VERSION 5.8 ;
BUSBITCHARS "[]" ;
DIVIDERCHAR "/" ;
UNITS
    DATABASE MICRONS 1000 ;
END UNITS

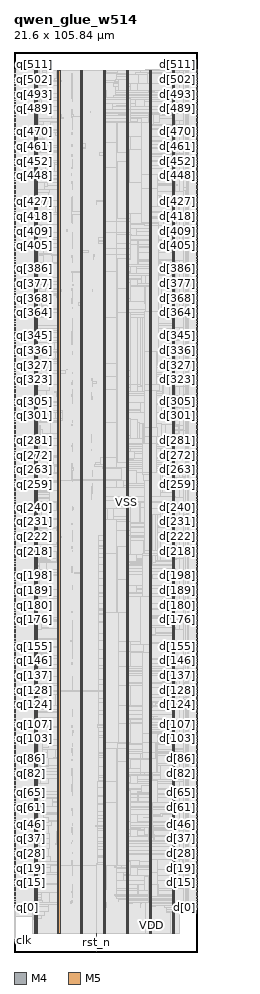
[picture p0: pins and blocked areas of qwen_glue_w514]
MACRO qwen_glue_w514
  FOREIGN qwen_glue_w514 0 0 ;
  CLASS BLOCK ;
  SIZE 21.6 BY 105.84 ;
  PIN clk
    DIRECTION INPUT ;
    USE SIGNAL ;
    PORT
      LAYER M4 ;
        RECT  0.054 1.296 0.138 1.32 ;
    END
    PORT
      LAYER M4 ;
        RECT  0.108 1.296 0.227 1.416 ;
    END
  END clk
  PIN d[0]
    DIRECTION INPUT ;
    USE SIGNAL ;
    PORT
      LAYER M4 ;
        RECT  21.462 5.28 21.546 5.304 ;
    END
  END d[0]
  PIN d[100]
    DIRECTION INPUT ;
    USE SIGNAL ;
    PORT
      LAYER M4 ;
        RECT  21.462 24.48 21.546 24.504 ;
    END
  END d[100]
  PIN d[101]
    DIRECTION INPUT ;
    USE SIGNAL ;
    PORT
      LAYER M4 ;
        RECT  21.462 24.672 21.546 24.696 ;
    END
  END d[101]
  PIN d[102]
    DIRECTION INPUT ;
    USE SIGNAL ;
    PORT
      LAYER M4 ;
        RECT  21.462 24.864 21.546 24.888 ;
    END
  END d[102]
  PIN d[103]
    DIRECTION INPUT ;
    USE SIGNAL ;
    PORT
      LAYER M4 ;
        RECT  21.462 25.056 21.546 25.08 ;
    END
  END d[103]
  PIN d[104]
    DIRECTION INPUT ;
    USE SIGNAL ;
    PORT
      LAYER M4 ;
        RECT  21.462 25.248 21.546 25.272 ;
    END
  END d[104]
  PIN d[105]
    DIRECTION INPUT ;
    USE SIGNAL ;
    PORT
      LAYER M4 ;
        RECT  21.462 25.44 21.546 25.464 ;
    END
  END d[105]
  PIN d[106]
    DIRECTION INPUT ;
    USE SIGNAL ;
    PORT
      LAYER M4 ;
        RECT  21.462 25.632 21.546 25.656 ;
    END
  END d[106]
  PIN d[107]
    DIRECTION INPUT ;
    USE SIGNAL ;
    PORT
      LAYER M4 ;
        RECT  21.462 25.824 21.546 25.848 ;
    END
  END d[107]
  PIN d[108]
    DIRECTION INPUT ;
    USE SIGNAL ;
    PORT
      LAYER M4 ;
        RECT  21.462 26.016 21.546 26.04 ;
    END
  END d[108]
  PIN d[109]
    DIRECTION INPUT ;
    USE SIGNAL ;
    PORT
      LAYER M4 ;
        RECT  21.462 26.208 21.546 26.232 ;
    END
  END d[109]
  PIN d[10]
    DIRECTION INPUT ;
    USE SIGNAL ;
    PORT
      LAYER M4 ;
        RECT  21.462 7.2 21.546 7.224 ;
    END
  END d[10]
  PIN d[110]
    DIRECTION INPUT ;
    USE SIGNAL ;
    PORT
      LAYER M4 ;
        RECT  21.462 26.4 21.546 26.424 ;
    END
  END d[110]
  PIN d[111]
    DIRECTION INPUT ;
    USE SIGNAL ;
    PORT
      LAYER M4 ;
        RECT  21.462 26.592 21.546 26.616 ;
    END
  END d[111]
  PIN d[112]
    DIRECTION INPUT ;
    USE SIGNAL ;
    PORT
      LAYER M4 ;
        RECT  21.462 26.784 21.546 26.808 ;
    END
  END d[112]
  PIN d[113]
    DIRECTION INPUT ;
    USE SIGNAL ;
    PORT
      LAYER M4 ;
        RECT  21.462 26.976 21.546 27 ;
    END
  END d[113]
  PIN d[114]
    DIRECTION INPUT ;
    USE SIGNAL ;
    PORT
      LAYER M4 ;
        RECT  21.462 27.168 21.546 27.192 ;
    END
  END d[114]
  PIN d[115]
    DIRECTION INPUT ;
    USE SIGNAL ;
    PORT
      LAYER M4 ;
        RECT  21.462 27.36 21.546 27.384 ;
    END
  END d[115]
  PIN d[116]
    DIRECTION INPUT ;
    USE SIGNAL ;
    PORT
      LAYER M4 ;
        RECT  21.462 27.552 21.546 27.576 ;
    END
  END d[116]
  PIN d[117]
    DIRECTION INPUT ;
    USE SIGNAL ;
    PORT
      LAYER M4 ;
        RECT  21.462 27.744 21.546 27.768 ;
    END
  END d[117]
  PIN d[118]
    DIRECTION INPUT ;
    USE SIGNAL ;
    PORT
      LAYER M4 ;
        RECT  21.462 27.936 21.546 27.96 ;
    END
  END d[118]
  PIN d[119]
    DIRECTION INPUT ;
    USE SIGNAL ;
    PORT
      LAYER M4 ;
        RECT  21.462 28.128 21.546 28.152 ;
    END
  END d[119]
  PIN d[11]
    DIRECTION INPUT ;
    USE SIGNAL ;
    PORT
      LAYER M4 ;
        RECT  21.462 7.392 21.546 7.416 ;
    END
  END d[11]
  PIN d[120]
    DIRECTION INPUT ;
    USE SIGNAL ;
    PORT
      LAYER M4 ;
        RECT  21.462 28.32 21.546 28.344 ;
    END
  END d[120]
  PIN d[121]
    DIRECTION INPUT ;
    USE SIGNAL ;
    PORT
      LAYER M4 ;
        RECT  21.462 28.512 21.546 28.536 ;
    END
  END d[121]
  PIN d[122]
    DIRECTION INPUT ;
    USE SIGNAL ;
    PORT
      LAYER M4 ;
        RECT  21.462 28.704 21.546 28.728 ;
    END
  END d[122]
  PIN d[123]
    DIRECTION INPUT ;
    USE SIGNAL ;
    PORT
      LAYER M4 ;
        RECT  21.462 28.896 21.546 28.92 ;
    END
  END d[123]
  PIN d[124]
    DIRECTION INPUT ;
    USE SIGNAL ;
    PORT
      LAYER M4 ;
        RECT  21.462 29.088 21.546 29.112 ;
    END
  END d[124]
  PIN d[125]
    DIRECTION INPUT ;
    USE SIGNAL ;
    PORT
      LAYER M4 ;
        RECT  21.462 29.28 21.546 29.304 ;
    END
  END d[125]
  PIN d[126]
    DIRECTION INPUT ;
    USE SIGNAL ;
    PORT
      LAYER M4 ;
        RECT  21.462 29.472 21.546 29.496 ;
    END
  END d[126]
  PIN d[127]
    DIRECTION INPUT ;
    USE SIGNAL ;
    PORT
      LAYER M4 ;
        RECT  21.462 29.664 21.546 29.688 ;
    END
  END d[127]
  PIN d[128]
    DIRECTION INPUT ;
    USE SIGNAL ;
    PORT
      LAYER M4 ;
        RECT  21.462 29.856 21.546 29.88 ;
    END
  END d[128]
  PIN d[129]
    DIRECTION INPUT ;
    USE SIGNAL ;
    PORT
      LAYER M4 ;
        RECT  21.462 30.048 21.546 30.072 ;
    END
  END d[129]
  PIN d[12]
    DIRECTION INPUT ;
    USE SIGNAL ;
    PORT
      LAYER M4 ;
        RECT  21.462 7.584 21.546 7.608 ;
    END
  END d[12]
  PIN d[130]
    DIRECTION INPUT ;
    USE SIGNAL ;
    PORT
      LAYER M4 ;
        RECT  21.462 30.24 21.546 30.264 ;
    END
  END d[130]
  PIN d[131]
    DIRECTION INPUT ;
    USE SIGNAL ;
    PORT
      LAYER M4 ;
        RECT  21.462 30.432 21.546 30.456 ;
    END
  END d[131]
  PIN d[132]
    DIRECTION INPUT ;
    USE SIGNAL ;
    PORT
      LAYER M4 ;
        RECT  21.462 30.624 21.546 30.648 ;
    END
  END d[132]
  PIN d[133]
    DIRECTION INPUT ;
    USE SIGNAL ;
    PORT
      LAYER M4 ;
        RECT  21.462 30.816 21.546 30.84 ;
    END
  END d[133]
  PIN d[134]
    DIRECTION INPUT ;
    USE SIGNAL ;
    PORT
      LAYER M4 ;
        RECT  21.462 31.008 21.546 31.032 ;
    END
  END d[134]
  PIN d[135]
    DIRECTION INPUT ;
    USE SIGNAL ;
    PORT
      LAYER M4 ;
        RECT  21.462 31.2 21.546 31.224 ;
    END
  END d[135]
  PIN d[136]
    DIRECTION INPUT ;
    USE SIGNAL ;
    PORT
      LAYER M4 ;
        RECT  21.462 31.392 21.546 31.416 ;
    END
  END d[136]
  PIN d[137]
    DIRECTION INPUT ;
    USE SIGNAL ;
    PORT
      LAYER M4 ;
        RECT  21.462 31.584 21.546 31.608 ;
    END
  END d[137]
  PIN d[138]
    DIRECTION INPUT ;
    USE SIGNAL ;
    PORT
      LAYER M4 ;
        RECT  21.462 31.776 21.546 31.8 ;
    END
  END d[138]
  PIN d[139]
    DIRECTION INPUT ;
    USE SIGNAL ;
    PORT
      LAYER M4 ;
        RECT  21.462 31.968 21.546 31.992 ;
    END
  END d[139]
  PIN d[13]
    DIRECTION INPUT ;
    USE SIGNAL ;
    PORT
      LAYER M4 ;
        RECT  21.462 7.776 21.546 7.8 ;
    END
  END d[13]
  PIN d[140]
    DIRECTION INPUT ;
    USE SIGNAL ;
    PORT
      LAYER M4 ;
        RECT  21.462 32.16 21.546 32.184 ;
    END
  END d[140]
  PIN d[141]
    DIRECTION INPUT ;
    USE SIGNAL ;
    PORT
      LAYER M4 ;
        RECT  21.462 32.352 21.546 32.376 ;
    END
  END d[141]
  PIN d[142]
    DIRECTION INPUT ;
    USE SIGNAL ;
    PORT
      LAYER M4 ;
        RECT  21.462 32.544 21.546 32.568 ;
    END
  END d[142]
  PIN d[143]
    DIRECTION INPUT ;
    USE SIGNAL ;
    PORT
      LAYER M4 ;
        RECT  21.462 32.736 21.546 32.76 ;
    END
  END d[143]
  PIN d[144]
    DIRECTION INPUT ;
    USE SIGNAL ;
    PORT
      LAYER M4 ;
        RECT  21.462 32.928 21.546 32.952 ;
    END
  END d[144]
  PIN d[145]
    DIRECTION INPUT ;
    USE SIGNAL ;
    PORT
      LAYER M4 ;
        RECT  21.462 33.12 21.546 33.144 ;
    END
  END d[145]
  PIN d[146]
    DIRECTION INPUT ;
    USE SIGNAL ;
    PORT
      LAYER M4 ;
        RECT  21.462 33.312 21.546 33.336 ;
    END
  END d[146]
  PIN d[147]
    DIRECTION INPUT ;
    USE SIGNAL ;
    PORT
      LAYER M4 ;
        RECT  21.462 33.504 21.546 33.528 ;
    END
  END d[147]
  PIN d[148]
    DIRECTION INPUT ;
    USE SIGNAL ;
    PORT
      LAYER M4 ;
        RECT  21.462 33.696 21.546 33.72 ;
    END
  END d[148]
  PIN d[149]
    DIRECTION INPUT ;
    USE SIGNAL ;
    PORT
      LAYER M4 ;
        RECT  21.462 33.888 21.546 33.912 ;
    END
  END d[149]
  PIN d[14]
    DIRECTION INPUT ;
    USE SIGNAL ;
    PORT
      LAYER M4 ;
        RECT  21.462 7.968 21.546 7.992 ;
    END
  END d[14]
  PIN d[150]
    DIRECTION INPUT ;
    USE SIGNAL ;
    PORT
      LAYER M4 ;
        RECT  21.462 34.08 21.546 34.104 ;
    END
  END d[150]
  PIN d[151]
    DIRECTION INPUT ;
    USE SIGNAL ;
    PORT
      LAYER M4 ;
        RECT  21.462 34.272 21.546 34.296 ;
    END
  END d[151]
  PIN d[152]
    DIRECTION INPUT ;
    USE SIGNAL ;
    PORT
      LAYER M4 ;
        RECT  21.462 34.464 21.546 34.488 ;
    END
  END d[152]
  PIN d[153]
    DIRECTION INPUT ;
    USE SIGNAL ;
    PORT
      LAYER M4 ;
        RECT  21.462 34.656 21.546 34.68 ;
    END
  END d[153]
  PIN d[154]
    DIRECTION INPUT ;
    USE SIGNAL ;
    PORT
      LAYER M4 ;
        RECT  21.462 34.848 21.546 34.872 ;
    END
  END d[154]
  PIN d[155]
    DIRECTION INPUT ;
    USE SIGNAL ;
    PORT
      LAYER M4 ;
        RECT  21.462 35.04 21.546 35.064 ;
    END
  END d[155]
  PIN d[156]
    DIRECTION INPUT ;
    USE SIGNAL ;
    PORT
      LAYER M4 ;
        RECT  21.462 35.232 21.546 35.256 ;
    END
  END d[156]
  PIN d[157]
    DIRECTION INPUT ;
    USE SIGNAL ;
    PORT
      LAYER M4 ;
        RECT  21.462 35.424 21.546 35.448 ;
    END
  END d[157]
  PIN d[158]
    DIRECTION INPUT ;
    USE SIGNAL ;
    PORT
      LAYER M4 ;
        RECT  21.462 35.616 21.546 35.64 ;
    END
  END d[158]
  PIN d[159]
    DIRECTION INPUT ;
    USE SIGNAL ;
    PORT
      LAYER M4 ;
        RECT  21.462 35.808 21.546 35.832 ;
    END
  END d[159]
  PIN d[15]
    DIRECTION INPUT ;
    USE SIGNAL ;
    PORT
      LAYER M4 ;
        RECT  21.462 8.16 21.546 8.184 ;
    END
  END d[15]
  PIN d[160]
    DIRECTION INPUT ;
    USE SIGNAL ;
    PORT
      LAYER M4 ;
        RECT  21.462 36 21.546 36.024 ;
    END
  END d[160]
  PIN d[161]
    DIRECTION INPUT ;
    USE SIGNAL ;
    PORT
      LAYER M4 ;
        RECT  21.462 36.192 21.546 36.216 ;
    END
  END d[161]
  PIN d[162]
    DIRECTION INPUT ;
    USE SIGNAL ;
    PORT
      LAYER M4 ;
        RECT  21.462 36.384 21.546 36.408 ;
    END
  END d[162]
  PIN d[163]
    DIRECTION INPUT ;
    USE SIGNAL ;
    PORT
      LAYER M4 ;
        RECT  21.462 36.576 21.546 36.6 ;
    END
  END d[163]
  PIN d[164]
    DIRECTION INPUT ;
    USE SIGNAL ;
    PORT
      LAYER M4 ;
        RECT  21.462 36.768 21.546 36.792 ;
    END
  END d[164]
  PIN d[165]
    DIRECTION INPUT ;
    USE SIGNAL ;
    PORT
      LAYER M4 ;
        RECT  21.462 36.96 21.546 36.984 ;
    END
  END d[165]
  PIN d[166]
    DIRECTION INPUT ;
    USE SIGNAL ;
    PORT
      LAYER M4 ;
        RECT  21.462 37.152 21.546 37.176 ;
    END
  END d[166]
  PIN d[167]
    DIRECTION INPUT ;
    USE SIGNAL ;
    PORT
      LAYER M4 ;
        RECT  21.462 37.344 21.546 37.368 ;
    END
  END d[167]
  PIN d[168]
    DIRECTION INPUT ;
    USE SIGNAL ;
    PORT
      LAYER M4 ;
        RECT  21.462 37.536 21.546 37.56 ;
    END
  END d[168]
  PIN d[169]
    DIRECTION INPUT ;
    USE SIGNAL ;
    PORT
      LAYER M4 ;
        RECT  21.462 37.728 21.546 37.752 ;
    END
  END d[169]
  PIN d[16]
    DIRECTION INPUT ;
    USE SIGNAL ;
    PORT
      LAYER M4 ;
        RECT  21.462 8.352 21.546 8.376 ;
    END
  END d[16]
  PIN d[170]
    DIRECTION INPUT ;
    USE SIGNAL ;
    PORT
      LAYER M4 ;
        RECT  21.462 37.92 21.546 37.944 ;
    END
  END d[170]
  PIN d[171]
    DIRECTION INPUT ;
    USE SIGNAL ;
    PORT
      LAYER M4 ;
        RECT  21.462 38.112 21.546 38.136 ;
    END
  END d[171]
  PIN d[172]
    DIRECTION INPUT ;
    USE SIGNAL ;
    PORT
      LAYER M4 ;
        RECT  21.462 38.304 21.546 38.328 ;
    END
  END d[172]
  PIN d[173]
    DIRECTION INPUT ;
    USE SIGNAL ;
    PORT
      LAYER M4 ;
        RECT  21.462 38.496 21.546 38.52 ;
    END
  END d[173]
  PIN d[174]
    DIRECTION INPUT ;
    USE SIGNAL ;
    PORT
      LAYER M4 ;
        RECT  21.462 38.688 21.546 38.712 ;
    END
  END d[174]
  PIN d[175]
    DIRECTION INPUT ;
    USE SIGNAL ;
    PORT
      LAYER M4 ;
        RECT  21.462 38.88 21.546 38.904 ;
    END
  END d[175]
  PIN d[176]
    DIRECTION INPUT ;
    USE SIGNAL ;
    PORT
      LAYER M4 ;
        RECT  21.462 39.072 21.546 39.096 ;
    END
  END d[176]
  PIN d[177]
    DIRECTION INPUT ;
    USE SIGNAL ;
    PORT
      LAYER M4 ;
        RECT  21.462 39.264 21.546 39.288 ;
    END
  END d[177]
  PIN d[178]
    DIRECTION INPUT ;
    USE SIGNAL ;
    PORT
      LAYER M4 ;
        RECT  21.462 39.456 21.546 39.48 ;
    END
  END d[178]
  PIN d[179]
    DIRECTION INPUT ;
    USE SIGNAL ;
    PORT
      LAYER M4 ;
        RECT  21.462 39.648 21.546 39.672 ;
    END
  END d[179]
  PIN d[17]
    DIRECTION INPUT ;
    USE SIGNAL ;
    PORT
      LAYER M4 ;
        RECT  21.462 8.544 21.546 8.568 ;
    END
  END d[17]
  PIN d[180]
    DIRECTION INPUT ;
    USE SIGNAL ;
    PORT
      LAYER M4 ;
        RECT  21.462 39.84 21.546 39.864 ;
    END
  END d[180]
  PIN d[181]
    DIRECTION INPUT ;
    USE SIGNAL ;
    PORT
      LAYER M4 ;
        RECT  21.462 40.032 21.546 40.056 ;
    END
  END d[181]
  PIN d[182]
    DIRECTION INPUT ;
    USE SIGNAL ;
    PORT
      LAYER M4 ;
        RECT  21.462 40.224 21.546 40.248 ;
    END
  END d[182]
  PIN d[183]
    DIRECTION INPUT ;
    USE SIGNAL ;
    PORT
      LAYER M4 ;
        RECT  21.462 40.416 21.546 40.44 ;
    END
  END d[183]
  PIN d[184]
    DIRECTION INPUT ;
    USE SIGNAL ;
    PORT
      LAYER M4 ;
        RECT  21.462 40.608 21.546 40.632 ;
    END
  END d[184]
  PIN d[185]
    DIRECTION INPUT ;
    USE SIGNAL ;
    PORT
      LAYER M4 ;
        RECT  21.462 40.8 21.546 40.824 ;
    END
  END d[185]
  PIN d[186]
    DIRECTION INPUT ;
    USE SIGNAL ;
    PORT
      LAYER M4 ;
        RECT  21.462 40.992 21.546 41.016 ;
    END
  END d[186]
  PIN d[187]
    DIRECTION INPUT ;
    USE SIGNAL ;
    PORT
      LAYER M4 ;
        RECT  21.462 41.184 21.546 41.208 ;
    END
  END d[187]
  PIN d[188]
    DIRECTION INPUT ;
    USE SIGNAL ;
    PORT
      LAYER M4 ;
        RECT  21.462 41.376 21.546 41.4 ;
    END
  END d[188]
  PIN d[189]
    DIRECTION INPUT ;
    USE SIGNAL ;
    PORT
      LAYER M4 ;
        RECT  21.462 41.568 21.546 41.592 ;
    END
  END d[189]
  PIN d[18]
    DIRECTION INPUT ;
    USE SIGNAL ;
    PORT
      LAYER M4 ;
        RECT  21.462 8.736 21.546 8.76 ;
    END
  END d[18]
  PIN d[190]
    DIRECTION INPUT ;
    USE SIGNAL ;
    PORT
      LAYER M4 ;
        RECT  21.462 41.76 21.546 41.784 ;
    END
  END d[190]
  PIN d[191]
    DIRECTION INPUT ;
    USE SIGNAL ;
    PORT
      LAYER M4 ;
        RECT  21.462 41.952 21.546 41.976 ;
    END
  END d[191]
  PIN d[192]
    DIRECTION INPUT ;
    USE SIGNAL ;
    PORT
      LAYER M4 ;
        RECT  21.462 42.144 21.546 42.168 ;
    END
  END d[192]
  PIN d[193]
    DIRECTION INPUT ;
    USE SIGNAL ;
    PORT
      LAYER M4 ;
        RECT  21.462 42.336 21.546 42.36 ;
    END
  END d[193]
  PIN d[194]
    DIRECTION INPUT ;
    USE SIGNAL ;
    PORT
      LAYER M4 ;
        RECT  21.462 42.528 21.546 42.552 ;
    END
  END d[194]
  PIN d[195]
    DIRECTION INPUT ;
    USE SIGNAL ;
    PORT
      LAYER M4 ;
        RECT  21.462 42.72 21.546 42.744 ;
    END
  END d[195]
  PIN d[196]
    DIRECTION INPUT ;
    USE SIGNAL ;
    PORT
      LAYER M4 ;
        RECT  21.462 42.912 21.546 42.936 ;
    END
  END d[196]
  PIN d[197]
    DIRECTION INPUT ;
    USE SIGNAL ;
    PORT
      LAYER M4 ;
        RECT  21.462 43.104 21.546 43.128 ;
    END
  END d[197]
  PIN d[198]
    DIRECTION INPUT ;
    USE SIGNAL ;
    PORT
      LAYER M4 ;
        RECT  21.462 43.296 21.546 43.32 ;
    END
  END d[198]
  PIN d[199]
    DIRECTION INPUT ;
    USE SIGNAL ;
    PORT
      LAYER M4 ;
        RECT  21.462 43.488 21.546 43.512 ;
    END
  END d[199]
  PIN d[19]
    DIRECTION INPUT ;
    USE SIGNAL ;
    PORT
      LAYER M4 ;
        RECT  21.462 8.928 21.546 8.952 ;
    END
  END d[19]
  PIN d[1]
    DIRECTION INPUT ;
    USE SIGNAL ;
    PORT
      LAYER M4 ;
        RECT  21.462 5.472 21.546 5.496 ;
    END
  END d[1]
  PIN d[200]
    DIRECTION INPUT ;
    USE SIGNAL ;
    PORT
      LAYER M4 ;
        RECT  21.462 43.68 21.546 43.704 ;
    END
  END d[200]
  PIN d[201]
    DIRECTION INPUT ;
    USE SIGNAL ;
    PORT
      LAYER M4 ;
        RECT  21.462 43.872 21.546 43.896 ;
    END
  END d[201]
  PIN d[202]
    DIRECTION INPUT ;
    USE SIGNAL ;
    PORT
      LAYER M4 ;
        RECT  21.462 44.064 21.546 44.088 ;
    END
  END d[202]
  PIN d[203]
    DIRECTION INPUT ;
    USE SIGNAL ;
    PORT
      LAYER M4 ;
        RECT  21.462 44.256 21.546 44.28 ;
    END
  END d[203]
  PIN d[204]
    DIRECTION INPUT ;
    USE SIGNAL ;
    PORT
      LAYER M4 ;
        RECT  21.462 44.448 21.546 44.472 ;
    END
  END d[204]
  PIN d[205]
    DIRECTION INPUT ;
    USE SIGNAL ;
    PORT
      LAYER M4 ;
        RECT  21.462 44.64 21.546 44.664 ;
    END
  END d[205]
  PIN d[206]
    DIRECTION INPUT ;
    USE SIGNAL ;
    PORT
      LAYER M4 ;
        RECT  21.462 44.832 21.546 44.856 ;
    END
  END d[206]
  PIN d[207]
    DIRECTION INPUT ;
    USE SIGNAL ;
    PORT
      LAYER M4 ;
        RECT  21.462 45.024 21.546 45.048 ;
    END
  END d[207]
  PIN d[208]
    DIRECTION INPUT ;
    USE SIGNAL ;
    PORT
      LAYER M4 ;
        RECT  21.462 45.216 21.546 45.24 ;
    END
  END d[208]
  PIN d[209]
    DIRECTION INPUT ;
    USE SIGNAL ;
    PORT
      LAYER M4 ;
        RECT  21.462 45.408 21.546 45.432 ;
    END
  END d[209]
  PIN d[20]
    DIRECTION INPUT ;
    USE SIGNAL ;
    PORT
      LAYER M4 ;
        RECT  21.462 9.12 21.546 9.144 ;
    END
  END d[20]
  PIN d[210]
    DIRECTION INPUT ;
    USE SIGNAL ;
    PORT
      LAYER M4 ;
        RECT  21.462 45.6 21.546 45.624 ;
    END
  END d[210]
  PIN d[211]
    DIRECTION INPUT ;
    USE SIGNAL ;
    PORT
      LAYER M4 ;
        RECT  21.462 45.792 21.546 45.816 ;
    END
  END d[211]
  PIN d[212]
    DIRECTION INPUT ;
    USE SIGNAL ;
    PORT
      LAYER M4 ;
        RECT  21.462 45.984 21.546 46.008 ;
    END
  END d[212]
  PIN d[213]
    DIRECTION INPUT ;
    USE SIGNAL ;
    PORT
      LAYER M4 ;
        RECT  21.462 46.176 21.546 46.2 ;
    END
  END d[213]
  PIN d[214]
    DIRECTION INPUT ;
    USE SIGNAL ;
    PORT
      LAYER M4 ;
        RECT  21.462 46.368 21.546 46.392 ;
    END
  END d[214]
  PIN d[215]
    DIRECTION INPUT ;
    USE SIGNAL ;
    PORT
      LAYER M4 ;
        RECT  21.462 46.56 21.546 46.584 ;
    END
  END d[215]
  PIN d[216]
    DIRECTION INPUT ;
    USE SIGNAL ;
    PORT
      LAYER M4 ;
        RECT  21.462 46.752 21.546 46.776 ;
    END
  END d[216]
  PIN d[217]
    DIRECTION INPUT ;
    USE SIGNAL ;
    PORT
      LAYER M4 ;
        RECT  21.462 46.944 21.546 46.968 ;
    END
  END d[217]
  PIN d[218]
    DIRECTION INPUT ;
    USE SIGNAL ;
    PORT
      LAYER M4 ;
        RECT  21.462 47.136 21.546 47.16 ;
    END
  END d[218]
  PIN d[219]
    DIRECTION INPUT ;
    USE SIGNAL ;
    PORT
      LAYER M4 ;
        RECT  21.462 47.328 21.546 47.352 ;
    END
  END d[219]
  PIN d[21]
    DIRECTION INPUT ;
    USE SIGNAL ;
    PORT
      LAYER M4 ;
        RECT  21.462 9.312 21.546 9.336 ;
    END
  END d[21]
  PIN d[220]
    DIRECTION INPUT ;
    USE SIGNAL ;
    PORT
      LAYER M4 ;
        RECT  21.462 47.52 21.546 47.544 ;
    END
  END d[220]
  PIN d[221]
    DIRECTION INPUT ;
    USE SIGNAL ;
    PORT
      LAYER M4 ;
        RECT  21.462 47.712 21.546 47.736 ;
    END
  END d[221]
  PIN d[222]
    DIRECTION INPUT ;
    USE SIGNAL ;
    PORT
      LAYER M4 ;
        RECT  21.462 47.904 21.546 47.928 ;
    END
  END d[222]
  PIN d[223]
    DIRECTION INPUT ;
    USE SIGNAL ;
    PORT
      LAYER M4 ;
        RECT  21.462 48.096 21.546 48.12 ;
    END
  END d[223]
  PIN d[224]
    DIRECTION INPUT ;
    USE SIGNAL ;
    PORT
      LAYER M4 ;
        RECT  21.462 48.288 21.546 48.312 ;
    END
  END d[224]
  PIN d[225]
    DIRECTION INPUT ;
    USE SIGNAL ;
    PORT
      LAYER M4 ;
        RECT  21.462 48.48 21.546 48.504 ;
    END
  END d[225]
  PIN d[226]
    DIRECTION INPUT ;
    USE SIGNAL ;
    PORT
      LAYER M4 ;
        RECT  21.462 48.672 21.546 48.696 ;
    END
  END d[226]
  PIN d[227]
    DIRECTION INPUT ;
    USE SIGNAL ;
    PORT
      LAYER M4 ;
        RECT  21.462 48.864 21.546 48.888 ;
    END
  END d[227]
  PIN d[228]
    DIRECTION INPUT ;
    USE SIGNAL ;
    PORT
      LAYER M4 ;
        RECT  21.462 49.056 21.546 49.08 ;
    END
  END d[228]
  PIN d[229]
    DIRECTION INPUT ;
    USE SIGNAL ;
    PORT
      LAYER M4 ;
        RECT  21.462 49.248 21.546 49.272 ;
    END
  END d[229]
  PIN d[22]
    DIRECTION INPUT ;
    USE SIGNAL ;
    PORT
      LAYER M4 ;
        RECT  21.462 9.504 21.546 9.528 ;
    END
  END d[22]
  PIN d[230]
    DIRECTION INPUT ;
    USE SIGNAL ;
    PORT
      LAYER M4 ;
        RECT  21.462 49.44 21.546 49.464 ;
    END
  END d[230]
  PIN d[231]
    DIRECTION INPUT ;
    USE SIGNAL ;
    PORT
      LAYER M4 ;
        RECT  21.462 49.632 21.546 49.656 ;
    END
  END d[231]
  PIN d[232]
    DIRECTION INPUT ;
    USE SIGNAL ;
    PORT
      LAYER M4 ;
        RECT  21.462 49.824 21.546 49.848 ;
    END
  END d[232]
  PIN d[233]
    DIRECTION INPUT ;
    USE SIGNAL ;
    PORT
      LAYER M4 ;
        RECT  21.462 50.016 21.546 50.04 ;
    END
  END d[233]
  PIN d[234]
    DIRECTION INPUT ;
    USE SIGNAL ;
    PORT
      LAYER M4 ;
        RECT  21.462 50.208 21.546 50.232 ;
    END
  END d[234]
  PIN d[235]
    DIRECTION INPUT ;
    USE SIGNAL ;
    PORT
      LAYER M4 ;
        RECT  21.462 50.4 21.546 50.424 ;
    END
  END d[235]
  PIN d[236]
    DIRECTION INPUT ;
    USE SIGNAL ;
    PORT
      LAYER M4 ;
        RECT  21.462 50.592 21.546 50.616 ;
    END
  END d[236]
  PIN d[237]
    DIRECTION INPUT ;
    USE SIGNAL ;
    PORT
      LAYER M4 ;
        RECT  21.462 50.784 21.546 50.808 ;
    END
  END d[237]
  PIN d[238]
    DIRECTION INPUT ;
    USE SIGNAL ;
    PORT
      LAYER M4 ;
        RECT  21.462 50.976 21.546 51 ;
    END
  END d[238]
  PIN d[239]
    DIRECTION INPUT ;
    USE SIGNAL ;
    PORT
      LAYER M4 ;
        RECT  21.462 51.168 21.546 51.192 ;
    END
  END d[239]
  PIN d[23]
    DIRECTION INPUT ;
    USE SIGNAL ;
    PORT
      LAYER M4 ;
        RECT  21.462 9.696 21.546 9.72 ;
    END
  END d[23]
  PIN d[240]
    DIRECTION INPUT ;
    USE SIGNAL ;
    PORT
      LAYER M4 ;
        RECT  21.462 51.36 21.546 51.384 ;
    END
  END d[240]
  PIN d[241]
    DIRECTION INPUT ;
    USE SIGNAL ;
    PORT
      LAYER M4 ;
        RECT  21.462 51.552 21.546 51.576 ;
    END
  END d[241]
  PIN d[242]
    DIRECTION INPUT ;
    USE SIGNAL ;
    PORT
      LAYER M4 ;
        RECT  21.462 51.744 21.546 51.768 ;
    END
  END d[242]
  PIN d[243]
    DIRECTION INPUT ;
    USE SIGNAL ;
    PORT
      LAYER M4 ;
        RECT  21.462 51.936 21.546 51.96 ;
    END
  END d[243]
  PIN d[244]
    DIRECTION INPUT ;
    USE SIGNAL ;
    PORT
      LAYER M4 ;
        RECT  21.462 52.128 21.546 52.152 ;
    END
  END d[244]
  PIN d[245]
    DIRECTION INPUT ;
    USE SIGNAL ;
    PORT
      LAYER M4 ;
        RECT  21.462 52.32 21.546 52.344 ;
    END
  END d[245]
  PIN d[246]
    DIRECTION INPUT ;
    USE SIGNAL ;
    PORT
      LAYER M4 ;
        RECT  21.462 52.512 21.546 52.536 ;
    END
  END d[246]
  PIN d[247]
    DIRECTION INPUT ;
    USE SIGNAL ;
    PORT
      LAYER M4 ;
        RECT  21.462 52.704 21.546 52.728 ;
    END
  END d[247]
  PIN d[248]
    DIRECTION INPUT ;
    USE SIGNAL ;
    PORT
      LAYER M4 ;
        RECT  21.462 52.896 21.546 52.92 ;
    END
  END d[248]
  PIN d[249]
    DIRECTION INPUT ;
    USE SIGNAL ;
    PORT
      LAYER M4 ;
        RECT  21.462 53.088 21.546 53.112 ;
    END
  END d[249]
  PIN d[24]
    DIRECTION INPUT ;
    USE SIGNAL ;
    PORT
      LAYER M4 ;
        RECT  21.462 9.888 21.546 9.912 ;
    END
  END d[24]
  PIN d[250]
    DIRECTION INPUT ;
    USE SIGNAL ;
    PORT
      LAYER M4 ;
        RECT  21.462 53.28 21.546 53.304 ;
    END
  END d[250]
  PIN d[251]
    DIRECTION INPUT ;
    USE SIGNAL ;
    PORT
      LAYER M4 ;
        RECT  21.462 53.472 21.546 53.496 ;
    END
  END d[251]
  PIN d[252]
    DIRECTION INPUT ;
    USE SIGNAL ;
    PORT
      LAYER M4 ;
        RECT  21.462 53.664 21.546 53.688 ;
    END
  END d[252]
  PIN d[253]
    DIRECTION INPUT ;
    USE SIGNAL ;
    PORT
      LAYER M4 ;
        RECT  21.462 53.856 21.546 53.88 ;
    END
  END d[253]
  PIN d[254]
    DIRECTION INPUT ;
    USE SIGNAL ;
    PORT
      LAYER M4 ;
        RECT  21.462 54.048 21.546 54.072 ;
    END
  END d[254]
  PIN d[255]
    DIRECTION INPUT ;
    USE SIGNAL ;
    PORT
      LAYER M4 ;
        RECT  21.462 54.24 21.546 54.264 ;
    END
  END d[255]
  PIN d[256]
    DIRECTION INPUT ;
    USE SIGNAL ;
    PORT
      LAYER M4 ;
        RECT  21.462 54.432 21.546 54.456 ;
    END
  END d[256]
  PIN d[257]
    DIRECTION INPUT ;
    USE SIGNAL ;
    PORT
      LAYER M4 ;
        RECT  21.462 54.624 21.546 54.648 ;
    END
  END d[257]
  PIN d[258]
    DIRECTION INPUT ;
    USE SIGNAL ;
    PORT
      LAYER M4 ;
        RECT  21.462 54.816 21.546 54.84 ;
    END
  END d[258]
  PIN d[259]
    DIRECTION INPUT ;
    USE SIGNAL ;
    PORT
      LAYER M4 ;
        RECT  21.462 55.008 21.546 55.032 ;
    END
  END d[259]
  PIN d[25]
    DIRECTION INPUT ;
    USE SIGNAL ;
    PORT
      LAYER M4 ;
        RECT  21.462 10.08 21.546 10.104 ;
    END
  END d[25]
  PIN d[260]
    DIRECTION INPUT ;
    USE SIGNAL ;
    PORT
      LAYER M4 ;
        RECT  21.462 55.2 21.546 55.224 ;
    END
  END d[260]
  PIN d[261]
    DIRECTION INPUT ;
    USE SIGNAL ;
    PORT
      LAYER M4 ;
        RECT  21.462 55.392 21.546 55.416 ;
    END
  END d[261]
  PIN d[262]
    DIRECTION INPUT ;
    USE SIGNAL ;
    PORT
      LAYER M4 ;
        RECT  21.462 55.584 21.546 55.608 ;
    END
  END d[262]
  PIN d[263]
    DIRECTION INPUT ;
    USE SIGNAL ;
    PORT
      LAYER M4 ;
        RECT  21.462 55.776 21.546 55.8 ;
    END
  END d[263]
  PIN d[264]
    DIRECTION INPUT ;
    USE SIGNAL ;
    PORT
      LAYER M4 ;
        RECT  21.462 55.968 21.546 55.992 ;
    END
  END d[264]
  PIN d[265]
    DIRECTION INPUT ;
    USE SIGNAL ;
    PORT
      LAYER M4 ;
        RECT  21.462 56.16 21.546 56.184 ;
    END
  END d[265]
  PIN d[266]
    DIRECTION INPUT ;
    USE SIGNAL ;
    PORT
      LAYER M4 ;
        RECT  21.462 56.352 21.546 56.376 ;
    END
  END d[266]
  PIN d[267]
    DIRECTION INPUT ;
    USE SIGNAL ;
    PORT
      LAYER M4 ;
        RECT  21.462 56.544 21.546 56.568 ;
    END
  END d[267]
  PIN d[268]
    DIRECTION INPUT ;
    USE SIGNAL ;
    PORT
      LAYER M4 ;
        RECT  21.462 56.736 21.546 56.76 ;
    END
  END d[268]
  PIN d[269]
    DIRECTION INPUT ;
    USE SIGNAL ;
    PORT
      LAYER M4 ;
        RECT  21.462 56.928 21.546 56.952 ;
    END
  END d[269]
  PIN d[26]
    DIRECTION INPUT ;
    USE SIGNAL ;
    PORT
      LAYER M4 ;
        RECT  21.462 10.272 21.546 10.296 ;
    END
  END d[26]
  PIN d[270]
    DIRECTION INPUT ;
    USE SIGNAL ;
    PORT
      LAYER M4 ;
        RECT  21.462 57.12 21.546 57.144 ;
    END
  END d[270]
  PIN d[271]
    DIRECTION INPUT ;
    USE SIGNAL ;
    PORT
      LAYER M4 ;
        RECT  21.462 57.312 21.546 57.336 ;
    END
  END d[271]
  PIN d[272]
    DIRECTION INPUT ;
    USE SIGNAL ;
    PORT
      LAYER M4 ;
        RECT  21.462 57.504 21.546 57.528 ;
    END
  END d[272]
  PIN d[273]
    DIRECTION INPUT ;
    USE SIGNAL ;
    PORT
      LAYER M4 ;
        RECT  21.462 57.696 21.546 57.72 ;
    END
  END d[273]
  PIN d[274]
    DIRECTION INPUT ;
    USE SIGNAL ;
    PORT
      LAYER M4 ;
        RECT  21.462 57.888 21.546 57.912 ;
    END
  END d[274]
  PIN d[275]
    DIRECTION INPUT ;
    USE SIGNAL ;
    PORT
      LAYER M4 ;
        RECT  21.462 58.08 21.546 58.104 ;
    END
  END d[275]
  PIN d[276]
    DIRECTION INPUT ;
    USE SIGNAL ;
    PORT
      LAYER M4 ;
        RECT  21.462 58.272 21.546 58.296 ;
    END
  END d[276]
  PIN d[277]
    DIRECTION INPUT ;
    USE SIGNAL ;
    PORT
      LAYER M4 ;
        RECT  21.462 58.464 21.546 58.488 ;
    END
  END d[277]
  PIN d[278]
    DIRECTION INPUT ;
    USE SIGNAL ;
    PORT
      LAYER M4 ;
        RECT  21.462 58.656 21.546 58.68 ;
    END
  END d[278]
  PIN d[279]
    DIRECTION INPUT ;
    USE SIGNAL ;
    PORT
      LAYER M4 ;
        RECT  21.462 58.848 21.546 58.872 ;
    END
  END d[279]
  PIN d[27]
    DIRECTION INPUT ;
    USE SIGNAL ;
    PORT
      LAYER M4 ;
        RECT  21.462 10.464 21.546 10.488 ;
    END
  END d[27]
  PIN d[280]
    DIRECTION INPUT ;
    USE SIGNAL ;
    PORT
      LAYER M4 ;
        RECT  21.462 59.04 21.546 59.064 ;
    END
  END d[280]
  PIN d[281]
    DIRECTION INPUT ;
    USE SIGNAL ;
    PORT
      LAYER M4 ;
        RECT  21.462 59.232 21.546 59.256 ;
    END
  END d[281]
  PIN d[282]
    DIRECTION INPUT ;
    USE SIGNAL ;
    PORT
      LAYER M4 ;
        RECT  21.462 59.424 21.546 59.448 ;
    END
  END d[282]
  PIN d[283]
    DIRECTION INPUT ;
    USE SIGNAL ;
    PORT
      LAYER M4 ;
        RECT  21.462 59.616 21.546 59.64 ;
    END
  END d[283]
  PIN d[284]
    DIRECTION INPUT ;
    USE SIGNAL ;
    PORT
      LAYER M4 ;
        RECT  21.462 59.808 21.546 59.832 ;
    END
  END d[284]
  PIN d[285]
    DIRECTION INPUT ;
    USE SIGNAL ;
    PORT
      LAYER M4 ;
        RECT  21.462 60 21.546 60.024 ;
    END
  END d[285]
  PIN d[286]
    DIRECTION INPUT ;
    USE SIGNAL ;
    PORT
      LAYER M4 ;
        RECT  21.462 60.192 21.546 60.216 ;
    END
  END d[286]
  PIN d[287]
    DIRECTION INPUT ;
    USE SIGNAL ;
    PORT
      LAYER M4 ;
        RECT  21.462 60.384 21.546 60.408 ;
    END
  END d[287]
  PIN d[288]
    DIRECTION INPUT ;
    USE SIGNAL ;
    PORT
      LAYER M4 ;
        RECT  21.462 60.576 21.546 60.6 ;
    END
  END d[288]
  PIN d[289]
    DIRECTION INPUT ;
    USE SIGNAL ;
    PORT
      LAYER M4 ;
        RECT  21.462 60.768 21.546 60.792 ;
    END
  END d[289]
  PIN d[28]
    DIRECTION INPUT ;
    USE SIGNAL ;
    PORT
      LAYER M4 ;
        RECT  21.462 10.656 21.546 10.68 ;
    END
  END d[28]
  PIN d[290]
    DIRECTION INPUT ;
    USE SIGNAL ;
    PORT
      LAYER M4 ;
        RECT  21.462 60.96 21.546 60.984 ;
    END
  END d[290]
  PIN d[291]
    DIRECTION INPUT ;
    USE SIGNAL ;
    PORT
      LAYER M4 ;
        RECT  21.462 61.152 21.546 61.176 ;
    END
  END d[291]
  PIN d[292]
    DIRECTION INPUT ;
    USE SIGNAL ;
    PORT
      LAYER M4 ;
        RECT  21.462 61.344 21.546 61.368 ;
    END
  END d[292]
  PIN d[293]
    DIRECTION INPUT ;
    USE SIGNAL ;
    PORT
      LAYER M4 ;
        RECT  21.462 61.536 21.546 61.56 ;
    END
  END d[293]
  PIN d[294]
    DIRECTION INPUT ;
    USE SIGNAL ;
    PORT
      LAYER M4 ;
        RECT  21.462 61.728 21.546 61.752 ;
    END
  END d[294]
  PIN d[295]
    DIRECTION INPUT ;
    USE SIGNAL ;
    PORT
      LAYER M4 ;
        RECT  21.462 61.92 21.546 61.944 ;
    END
  END d[295]
  PIN d[296]
    DIRECTION INPUT ;
    USE SIGNAL ;
    PORT
      LAYER M4 ;
        RECT  21.462 62.112 21.546 62.136 ;
    END
  END d[296]
  PIN d[297]
    DIRECTION INPUT ;
    USE SIGNAL ;
    PORT
      LAYER M4 ;
        RECT  21.462 62.304 21.546 62.328 ;
    END
  END d[297]
  PIN d[298]
    DIRECTION INPUT ;
    USE SIGNAL ;
    PORT
      LAYER M4 ;
        RECT  21.462 62.496 21.546 62.52 ;
    END
  END d[298]
  PIN d[299]
    DIRECTION INPUT ;
    USE SIGNAL ;
    PORT
      LAYER M4 ;
        RECT  21.462 62.688 21.546 62.712 ;
    END
  END d[299]
  PIN d[29]
    DIRECTION INPUT ;
    USE SIGNAL ;
    PORT
      LAYER M4 ;
        RECT  21.462 10.848 21.546 10.872 ;
    END
  END d[29]
  PIN d[2]
    DIRECTION INPUT ;
    USE SIGNAL ;
    PORT
      LAYER M4 ;
        RECT  21.462 5.664 21.546 5.688 ;
    END
  END d[2]
  PIN d[300]
    DIRECTION INPUT ;
    USE SIGNAL ;
    PORT
      LAYER M4 ;
        RECT  21.462 62.88 21.546 62.904 ;
    END
  END d[300]
  PIN d[301]
    DIRECTION INPUT ;
    USE SIGNAL ;
    PORT
      LAYER M4 ;
        RECT  21.462 63.072 21.546 63.096 ;
    END
  END d[301]
  PIN d[302]
    DIRECTION INPUT ;
    USE SIGNAL ;
    PORT
      LAYER M4 ;
        RECT  21.462 63.264 21.546 63.288 ;
    END
  END d[302]
  PIN d[303]
    DIRECTION INPUT ;
    USE SIGNAL ;
    PORT
      LAYER M4 ;
        RECT  21.462 63.456 21.546 63.48 ;
    END
  END d[303]
  PIN d[304]
    DIRECTION INPUT ;
    USE SIGNAL ;
    PORT
      LAYER M4 ;
        RECT  21.462 63.648 21.546 63.672 ;
    END
  END d[304]
  PIN d[305]
    DIRECTION INPUT ;
    USE SIGNAL ;
    PORT
      LAYER M4 ;
        RECT  21.462 63.84 21.546 63.864 ;
    END
  END d[305]
  PIN d[306]
    DIRECTION INPUT ;
    USE SIGNAL ;
    PORT
      LAYER M4 ;
        RECT  21.462 64.032 21.546 64.056 ;
    END
  END d[306]
  PIN d[307]
    DIRECTION INPUT ;
    USE SIGNAL ;
    PORT
      LAYER M4 ;
        RECT  21.462 64.224 21.546 64.248 ;
    END
  END d[307]
  PIN d[308]
    DIRECTION INPUT ;
    USE SIGNAL ;
    PORT
      LAYER M4 ;
        RECT  21.462 64.416 21.546 64.44 ;
    END
  END d[308]
  PIN d[309]
    DIRECTION INPUT ;
    USE SIGNAL ;
    PORT
      LAYER M4 ;
        RECT  21.462 64.608 21.546 64.632 ;
    END
  END d[309]
  PIN d[30]
    DIRECTION INPUT ;
    USE SIGNAL ;
    PORT
      LAYER M4 ;
        RECT  21.462 11.04 21.546 11.064 ;
    END
  END d[30]
  PIN d[310]
    DIRECTION INPUT ;
    USE SIGNAL ;
    PORT
      LAYER M4 ;
        RECT  21.462 64.8 21.546 64.824 ;
    END
  END d[310]
  PIN d[311]
    DIRECTION INPUT ;
    USE SIGNAL ;
    PORT
      LAYER M4 ;
        RECT  21.462 64.992 21.546 65.016 ;
    END
  END d[311]
  PIN d[312]
    DIRECTION INPUT ;
    USE SIGNAL ;
    PORT
      LAYER M4 ;
        RECT  21.462 65.184 21.546 65.208 ;
    END
  END d[312]
  PIN d[313]
    DIRECTION INPUT ;
    USE SIGNAL ;
    PORT
      LAYER M4 ;
        RECT  21.462 65.376 21.546 65.4 ;
    END
  END d[313]
  PIN d[314]
    DIRECTION INPUT ;
    USE SIGNAL ;
    PORT
      LAYER M4 ;
        RECT  21.462 65.568 21.546 65.592 ;
    END
  END d[314]
  PIN d[315]
    DIRECTION INPUT ;
    USE SIGNAL ;
    PORT
      LAYER M4 ;
        RECT  21.462 65.76 21.546 65.784 ;
    END
  END d[315]
  PIN d[316]
    DIRECTION INPUT ;
    USE SIGNAL ;
    PORT
      LAYER M4 ;
        RECT  21.462 65.952 21.546 65.976 ;
    END
  END d[316]
  PIN d[317]
    DIRECTION INPUT ;
    USE SIGNAL ;
    PORT
      LAYER M4 ;
        RECT  21.462 66.144 21.546 66.168 ;
    END
  END d[317]
  PIN d[318]
    DIRECTION INPUT ;
    USE SIGNAL ;
    PORT
      LAYER M4 ;
        RECT  21.462 66.336 21.546 66.36 ;
    END
  END d[318]
  PIN d[319]
    DIRECTION INPUT ;
    USE SIGNAL ;
    PORT
      LAYER M4 ;
        RECT  21.462 66.528 21.546 66.552 ;
    END
  END d[319]
  PIN d[31]
    DIRECTION INPUT ;
    USE SIGNAL ;
    PORT
      LAYER M4 ;
        RECT  21.462 11.232 21.546 11.256 ;
    END
  END d[31]
  PIN d[320]
    DIRECTION INPUT ;
    USE SIGNAL ;
    PORT
      LAYER M4 ;
        RECT  21.462 66.72 21.546 66.744 ;
    END
  END d[320]
  PIN d[321]
    DIRECTION INPUT ;
    USE SIGNAL ;
    PORT
      LAYER M4 ;
        RECT  21.462 66.912 21.546 66.936 ;
    END
  END d[321]
  PIN d[322]
    DIRECTION INPUT ;
    USE SIGNAL ;
    PORT
      LAYER M4 ;
        RECT  21.462 67.104 21.546 67.128 ;
    END
  END d[322]
  PIN d[323]
    DIRECTION INPUT ;
    USE SIGNAL ;
    PORT
      LAYER M4 ;
        RECT  21.462 67.296 21.546 67.32 ;
    END
  END d[323]
  PIN d[324]
    DIRECTION INPUT ;
    USE SIGNAL ;
    PORT
      LAYER M4 ;
        RECT  21.462 67.488 21.546 67.512 ;
    END
  END d[324]
  PIN d[325]
    DIRECTION INPUT ;
    USE SIGNAL ;
    PORT
      LAYER M4 ;
        RECT  21.462 67.68 21.546 67.704 ;
    END
  END d[325]
  PIN d[326]
    DIRECTION INPUT ;
    USE SIGNAL ;
    PORT
      LAYER M4 ;
        RECT  21.462 67.872 21.546 67.896 ;
    END
  END d[326]
  PIN d[327]
    DIRECTION INPUT ;
    USE SIGNAL ;
    PORT
      LAYER M4 ;
        RECT  21.462 68.064 21.546 68.088 ;
    END
  END d[327]
  PIN d[328]
    DIRECTION INPUT ;
    USE SIGNAL ;
    PORT
      LAYER M4 ;
        RECT  21.462 68.256 21.546 68.28 ;
    END
  END d[328]
  PIN d[329]
    DIRECTION INPUT ;
    USE SIGNAL ;
    PORT
      LAYER M4 ;
        RECT  21.462 68.448 21.546 68.472 ;
    END
  END d[329]
  PIN d[32]
    DIRECTION INPUT ;
    USE SIGNAL ;
    PORT
      LAYER M4 ;
        RECT  21.462 11.424 21.546 11.448 ;
    END
  END d[32]
  PIN d[330]
    DIRECTION INPUT ;
    USE SIGNAL ;
    PORT
      LAYER M4 ;
        RECT  21.462 68.64 21.546 68.664 ;
    END
  END d[330]
  PIN d[331]
    DIRECTION INPUT ;
    USE SIGNAL ;
    PORT
      LAYER M4 ;
        RECT  21.462 68.832 21.546 68.856 ;
    END
  END d[331]
  PIN d[332]
    DIRECTION INPUT ;
    USE SIGNAL ;
    PORT
      LAYER M4 ;
        RECT  21.462 69.024 21.546 69.048 ;
    END
  END d[332]
  PIN d[333]
    DIRECTION INPUT ;
    USE SIGNAL ;
    PORT
      LAYER M4 ;
        RECT  21.462 69.216 21.546 69.24 ;
    END
  END d[333]
  PIN d[334]
    DIRECTION INPUT ;
    USE SIGNAL ;
    PORT
      LAYER M4 ;
        RECT  21.462 69.408 21.546 69.432 ;
    END
  END d[334]
  PIN d[335]
    DIRECTION INPUT ;
    USE SIGNAL ;
    PORT
      LAYER M4 ;
        RECT  21.462 69.6 21.546 69.624 ;
    END
  END d[335]
  PIN d[336]
    DIRECTION INPUT ;
    USE SIGNAL ;
    PORT
      LAYER M4 ;
        RECT  21.462 69.792 21.546 69.816 ;
    END
  END d[336]
  PIN d[337]
    DIRECTION INPUT ;
    USE SIGNAL ;
    PORT
      LAYER M4 ;
        RECT  21.462 69.984 21.546 70.008 ;
    END
  END d[337]
  PIN d[338]
    DIRECTION INPUT ;
    USE SIGNAL ;
    PORT
      LAYER M4 ;
        RECT  21.462 70.176 21.546 70.2 ;
    END
  END d[338]
  PIN d[339]
    DIRECTION INPUT ;
    USE SIGNAL ;
    PORT
      LAYER M4 ;
        RECT  21.462 70.368 21.546 70.392 ;
    END
  END d[339]
  PIN d[33]
    DIRECTION INPUT ;
    USE SIGNAL ;
    PORT
      LAYER M4 ;
        RECT  21.462 11.616 21.546 11.64 ;
    END
  END d[33]
  PIN d[340]
    DIRECTION INPUT ;
    USE SIGNAL ;
    PORT
      LAYER M4 ;
        RECT  21.462 70.56 21.546 70.584 ;
    END
  END d[340]
  PIN d[341]
    DIRECTION INPUT ;
    USE SIGNAL ;
    PORT
      LAYER M4 ;
        RECT  21.462 70.752 21.546 70.776 ;
    END
  END d[341]
  PIN d[342]
    DIRECTION INPUT ;
    USE SIGNAL ;
    PORT
      LAYER M4 ;
        RECT  21.462 70.944 21.546 70.968 ;
    END
  END d[342]
  PIN d[343]
    DIRECTION INPUT ;
    USE SIGNAL ;
    PORT
      LAYER M4 ;
        RECT  21.462 71.136 21.546 71.16 ;
    END
  END d[343]
  PIN d[344]
    DIRECTION INPUT ;
    USE SIGNAL ;
    PORT
      LAYER M4 ;
        RECT  21.462 71.328 21.546 71.352 ;
    END
  END d[344]
  PIN d[345]
    DIRECTION INPUT ;
    USE SIGNAL ;
    PORT
      LAYER M4 ;
        RECT  21.462 71.52 21.546 71.544 ;
    END
  END d[345]
  PIN d[346]
    DIRECTION INPUT ;
    USE SIGNAL ;
    PORT
      LAYER M4 ;
        RECT  21.462 71.712 21.546 71.736 ;
    END
  END d[346]
  PIN d[347]
    DIRECTION INPUT ;
    USE SIGNAL ;
    PORT
      LAYER M4 ;
        RECT  21.462 71.904 21.546 71.928 ;
    END
  END d[347]
  PIN d[348]
    DIRECTION INPUT ;
    USE SIGNAL ;
    PORT
      LAYER M4 ;
        RECT  21.462 72.096 21.546 72.12 ;
    END
  END d[348]
  PIN d[349]
    DIRECTION INPUT ;
    USE SIGNAL ;
    PORT
      LAYER M4 ;
        RECT  21.462 72.288 21.546 72.312 ;
    END
  END d[349]
  PIN d[34]
    DIRECTION INPUT ;
    USE SIGNAL ;
    PORT
      LAYER M4 ;
        RECT  21.462 11.808 21.546 11.832 ;
    END
  END d[34]
  PIN d[350]
    DIRECTION INPUT ;
    USE SIGNAL ;
    PORT
      LAYER M4 ;
        RECT  21.462 72.48 21.546 72.504 ;
    END
  END d[350]
  PIN d[351]
    DIRECTION INPUT ;
    USE SIGNAL ;
    PORT
      LAYER M4 ;
        RECT  21.462 72.672 21.546 72.696 ;
    END
  END d[351]
  PIN d[352]
    DIRECTION INPUT ;
    USE SIGNAL ;
    PORT
      LAYER M4 ;
        RECT  21.462 72.864 21.546 72.888 ;
    END
  END d[352]
  PIN d[353]
    DIRECTION INPUT ;
    USE SIGNAL ;
    PORT
      LAYER M4 ;
        RECT  21.462 73.056 21.546 73.08 ;
    END
  END d[353]
  PIN d[354]
    DIRECTION INPUT ;
    USE SIGNAL ;
    PORT
      LAYER M4 ;
        RECT  21.462 73.248 21.546 73.272 ;
    END
  END d[354]
  PIN d[355]
    DIRECTION INPUT ;
    USE SIGNAL ;
    PORT
      LAYER M4 ;
        RECT  21.462 73.44 21.546 73.464 ;
    END
  END d[355]
  PIN d[356]
    DIRECTION INPUT ;
    USE SIGNAL ;
    PORT
      LAYER M4 ;
        RECT  21.462 73.632 21.546 73.656 ;
    END
  END d[356]
  PIN d[357]
    DIRECTION INPUT ;
    USE SIGNAL ;
    PORT
      LAYER M4 ;
        RECT  21.462 73.824 21.546 73.848 ;
    END
  END d[357]
  PIN d[358]
    DIRECTION INPUT ;
    USE SIGNAL ;
    PORT
      LAYER M4 ;
        RECT  21.462 74.016 21.546 74.04 ;
    END
  END d[358]
  PIN d[359]
    DIRECTION INPUT ;
    USE SIGNAL ;
    PORT
      LAYER M4 ;
        RECT  21.462 74.208 21.546 74.232 ;
    END
  END d[359]
  PIN d[35]
    DIRECTION INPUT ;
    USE SIGNAL ;
    PORT
      LAYER M4 ;
        RECT  21.462 12 21.546 12.024 ;
    END
  END d[35]
  PIN d[360]
    DIRECTION INPUT ;
    USE SIGNAL ;
    PORT
      LAYER M4 ;
        RECT  21.462 74.4 21.546 74.424 ;
    END
  END d[360]
  PIN d[361]
    DIRECTION INPUT ;
    USE SIGNAL ;
    PORT
      LAYER M4 ;
        RECT  21.462 74.592 21.546 74.616 ;
    END
  END d[361]
  PIN d[362]
    DIRECTION INPUT ;
    USE SIGNAL ;
    PORT
      LAYER M4 ;
        RECT  21.462 74.784 21.546 74.808 ;
    END
  END d[362]
  PIN d[363]
    DIRECTION INPUT ;
    USE SIGNAL ;
    PORT
      LAYER M4 ;
        RECT  21.462 74.976 21.546 75 ;
    END
  END d[363]
  PIN d[364]
    DIRECTION INPUT ;
    USE SIGNAL ;
    PORT
      LAYER M4 ;
        RECT  21.462 75.168 21.546 75.192 ;
    END
  END d[364]
  PIN d[365]
    DIRECTION INPUT ;
    USE SIGNAL ;
    PORT
      LAYER M4 ;
        RECT  21.462 75.36 21.546 75.384 ;
    END
  END d[365]
  PIN d[366]
    DIRECTION INPUT ;
    USE SIGNAL ;
    PORT
      LAYER M4 ;
        RECT  21.462 75.552 21.546 75.576 ;
    END
  END d[366]
  PIN d[367]
    DIRECTION INPUT ;
    USE SIGNAL ;
    PORT
      LAYER M4 ;
        RECT  21.462 75.744 21.546 75.768 ;
    END
  END d[367]
  PIN d[368]
    DIRECTION INPUT ;
    USE SIGNAL ;
    PORT
      LAYER M4 ;
        RECT  21.462 75.936 21.546 75.96 ;
    END
  END d[368]
  PIN d[369]
    DIRECTION INPUT ;
    USE SIGNAL ;
    PORT
      LAYER M4 ;
        RECT  21.462 76.128 21.546 76.152 ;
    END
  END d[369]
  PIN d[36]
    DIRECTION INPUT ;
    USE SIGNAL ;
    PORT
      LAYER M4 ;
        RECT  21.462 12.192 21.546 12.216 ;
    END
  END d[36]
  PIN d[370]
    DIRECTION INPUT ;
    USE SIGNAL ;
    PORT
      LAYER M4 ;
        RECT  21.462 76.32 21.546 76.344 ;
    END
  END d[370]
  PIN d[371]
    DIRECTION INPUT ;
    USE SIGNAL ;
    PORT
      LAYER M4 ;
        RECT  21.462 76.512 21.546 76.536 ;
    END
  END d[371]
  PIN d[372]
    DIRECTION INPUT ;
    USE SIGNAL ;
    PORT
      LAYER M4 ;
        RECT  21.462 76.704 21.546 76.728 ;
    END
  END d[372]
  PIN d[373]
    DIRECTION INPUT ;
    USE SIGNAL ;
    PORT
      LAYER M4 ;
        RECT  21.462 76.896 21.546 76.92 ;
    END
  END d[373]
  PIN d[374]
    DIRECTION INPUT ;
    USE SIGNAL ;
    PORT
      LAYER M4 ;
        RECT  21.462 77.088 21.546 77.112 ;
    END
  END d[374]
  PIN d[375]
    DIRECTION INPUT ;
    USE SIGNAL ;
    PORT
      LAYER M4 ;
        RECT  21.462 77.28 21.546 77.304 ;
    END
  END d[375]
  PIN d[376]
    DIRECTION INPUT ;
    USE SIGNAL ;
    PORT
      LAYER M4 ;
        RECT  21.462 77.472 21.546 77.496 ;
    END
  END d[376]
  PIN d[377]
    DIRECTION INPUT ;
    USE SIGNAL ;
    PORT
      LAYER M4 ;
        RECT  21.462 77.664 21.546 77.688 ;
    END
  END d[377]
  PIN d[378]
    DIRECTION INPUT ;
    USE SIGNAL ;
    PORT
      LAYER M4 ;
        RECT  21.462 77.856 21.546 77.88 ;
    END
  END d[378]
  PIN d[379]
    DIRECTION INPUT ;
    USE SIGNAL ;
    PORT
      LAYER M4 ;
        RECT  21.462 78.048 21.546 78.072 ;
    END
  END d[379]
  PIN d[37]
    DIRECTION INPUT ;
    USE SIGNAL ;
    PORT
      LAYER M4 ;
        RECT  21.462 12.384 21.546 12.408 ;
    END
  END d[37]
  PIN d[380]
    DIRECTION INPUT ;
    USE SIGNAL ;
    PORT
      LAYER M4 ;
        RECT  21.462 78.24 21.546 78.264 ;
    END
  END d[380]
  PIN d[381]
    DIRECTION INPUT ;
    USE SIGNAL ;
    PORT
      LAYER M4 ;
        RECT  21.462 78.432 21.546 78.456 ;
    END
  END d[381]
  PIN d[382]
    DIRECTION INPUT ;
    USE SIGNAL ;
    PORT
      LAYER M4 ;
        RECT  21.462 78.624 21.546 78.648 ;
    END
  END d[382]
  PIN d[383]
    DIRECTION INPUT ;
    USE SIGNAL ;
    PORT
      LAYER M4 ;
        RECT  21.462 78.816 21.546 78.84 ;
    END
  END d[383]
  PIN d[384]
    DIRECTION INPUT ;
    USE SIGNAL ;
    PORT
      LAYER M4 ;
        RECT  21.462 79.008 21.546 79.032 ;
    END
  END d[384]
  PIN d[385]
    DIRECTION INPUT ;
    USE SIGNAL ;
    PORT
      LAYER M4 ;
        RECT  21.462 79.2 21.546 79.224 ;
    END
  END d[385]
  PIN d[386]
    DIRECTION INPUT ;
    USE SIGNAL ;
    PORT
      LAYER M4 ;
        RECT  21.462 79.392 21.546 79.416 ;
    END
  END d[386]
  PIN d[387]
    DIRECTION INPUT ;
    USE SIGNAL ;
    PORT
      LAYER M4 ;
        RECT  21.462 79.584 21.546 79.608 ;
    END
  END d[387]
  PIN d[388]
    DIRECTION INPUT ;
    USE SIGNAL ;
    PORT
      LAYER M4 ;
        RECT  21.462 79.776 21.546 79.8 ;
    END
  END d[388]
  PIN d[389]
    DIRECTION INPUT ;
    USE SIGNAL ;
    PORT
      LAYER M4 ;
        RECT  21.462 79.968 21.546 79.992 ;
    END
  END d[389]
  PIN d[38]
    DIRECTION INPUT ;
    USE SIGNAL ;
    PORT
      LAYER M4 ;
        RECT  21.462 12.576 21.546 12.6 ;
    END
  END d[38]
  PIN d[390]
    DIRECTION INPUT ;
    USE SIGNAL ;
    PORT
      LAYER M4 ;
        RECT  21.462 80.16 21.546 80.184 ;
    END
  END d[390]
  PIN d[391]
    DIRECTION INPUT ;
    USE SIGNAL ;
    PORT
      LAYER M4 ;
        RECT  21.462 80.352 21.546 80.376 ;
    END
  END d[391]
  PIN d[392]
    DIRECTION INPUT ;
    USE SIGNAL ;
    PORT
      LAYER M4 ;
        RECT  21.462 80.544 21.546 80.568 ;
    END
  END d[392]
  PIN d[393]
    DIRECTION INPUT ;
    USE SIGNAL ;
    PORT
      LAYER M4 ;
        RECT  21.462 80.736 21.546 80.76 ;
    END
  END d[393]
  PIN d[394]
    DIRECTION INPUT ;
    USE SIGNAL ;
    PORT
      LAYER M4 ;
        RECT  21.462 80.928 21.546 80.952 ;
    END
  END d[394]
  PIN d[395]
    DIRECTION INPUT ;
    USE SIGNAL ;
    PORT
      LAYER M4 ;
        RECT  21.462 81.12 21.546 81.144 ;
    END
  END d[395]
  PIN d[396]
    DIRECTION INPUT ;
    USE SIGNAL ;
    PORT
      LAYER M4 ;
        RECT  21.462 81.312 21.546 81.336 ;
    END
  END d[396]
  PIN d[397]
    DIRECTION INPUT ;
    USE SIGNAL ;
    PORT
      LAYER M4 ;
        RECT  21.462 81.504 21.546 81.528 ;
    END
  END d[397]
  PIN d[398]
    DIRECTION INPUT ;
    USE SIGNAL ;
    PORT
      LAYER M4 ;
        RECT  21.462 81.696 21.546 81.72 ;
    END
  END d[398]
  PIN d[399]
    DIRECTION INPUT ;
    USE SIGNAL ;
    PORT
      LAYER M4 ;
        RECT  21.462 81.888 21.546 81.912 ;
    END
  END d[399]
  PIN d[39]
    DIRECTION INPUT ;
    USE SIGNAL ;
    PORT
      LAYER M4 ;
        RECT  21.462 12.768 21.546 12.792 ;
    END
  END d[39]
  PIN d[3]
    DIRECTION INPUT ;
    USE SIGNAL ;
    PORT
      LAYER M4 ;
        RECT  21.462 5.856 21.546 5.88 ;
    END
  END d[3]
  PIN d[400]
    DIRECTION INPUT ;
    USE SIGNAL ;
    PORT
      LAYER M4 ;
        RECT  21.462 82.08 21.546 82.104 ;
    END
  END d[400]
  PIN d[401]
    DIRECTION INPUT ;
    USE SIGNAL ;
    PORT
      LAYER M4 ;
        RECT  21.462 82.272 21.546 82.296 ;
    END
  END d[401]
  PIN d[402]
    DIRECTION INPUT ;
    USE SIGNAL ;
    PORT
      LAYER M4 ;
        RECT  21.462 82.464 21.546 82.488 ;
    END
  END d[402]
  PIN d[403]
    DIRECTION INPUT ;
    USE SIGNAL ;
    PORT
      LAYER M4 ;
        RECT  21.462 82.656 21.546 82.68 ;
    END
  END d[403]
  PIN d[404]
    DIRECTION INPUT ;
    USE SIGNAL ;
    PORT
      LAYER M4 ;
        RECT  21.462 82.848 21.546 82.872 ;
    END
  END d[404]
  PIN d[405]
    DIRECTION INPUT ;
    USE SIGNAL ;
    PORT
      LAYER M4 ;
        RECT  21.462 83.04 21.546 83.064 ;
    END
  END d[405]
  PIN d[406]
    DIRECTION INPUT ;
    USE SIGNAL ;
    PORT
      LAYER M4 ;
        RECT  21.462 83.232 21.546 83.256 ;
    END
  END d[406]
  PIN d[407]
    DIRECTION INPUT ;
    USE SIGNAL ;
    PORT
      LAYER M4 ;
        RECT  21.462 83.424 21.546 83.448 ;
    END
  END d[407]
  PIN d[408]
    DIRECTION INPUT ;
    USE SIGNAL ;
    PORT
      LAYER M4 ;
        RECT  21.462 83.616 21.546 83.64 ;
    END
  END d[408]
  PIN d[409]
    DIRECTION INPUT ;
    USE SIGNAL ;
    PORT
      LAYER M4 ;
        RECT  21.462 83.808 21.546 83.832 ;
    END
  END d[409]
  PIN d[40]
    DIRECTION INPUT ;
    USE SIGNAL ;
    PORT
      LAYER M4 ;
        RECT  21.462 12.96 21.546 12.984 ;
    END
  END d[40]
  PIN d[410]
    DIRECTION INPUT ;
    USE SIGNAL ;
    PORT
      LAYER M4 ;
        RECT  21.462 84 21.546 84.024 ;
    END
  END d[410]
  PIN d[411]
    DIRECTION INPUT ;
    USE SIGNAL ;
    PORT
      LAYER M4 ;
        RECT  21.462 84.192 21.546 84.216 ;
    END
  END d[411]
  PIN d[412]
    DIRECTION INPUT ;
    USE SIGNAL ;
    PORT
      LAYER M4 ;
        RECT  21.462 84.384 21.546 84.408 ;
    END
  END d[412]
  PIN d[413]
    DIRECTION INPUT ;
    USE SIGNAL ;
    PORT
      LAYER M4 ;
        RECT  21.462 84.576 21.546 84.6 ;
    END
  END d[413]
  PIN d[414]
    DIRECTION INPUT ;
    USE SIGNAL ;
    PORT
      LAYER M4 ;
        RECT  21.462 84.768 21.546 84.792 ;
    END
  END d[414]
  PIN d[415]
    DIRECTION INPUT ;
    USE SIGNAL ;
    PORT
      LAYER M4 ;
        RECT  21.462 84.96 21.546 84.984 ;
    END
  END d[415]
  PIN d[416]
    DIRECTION INPUT ;
    USE SIGNAL ;
    PORT
      LAYER M4 ;
        RECT  21.462 85.152 21.546 85.176 ;
    END
  END d[416]
  PIN d[417]
    DIRECTION INPUT ;
    USE SIGNAL ;
    PORT
      LAYER M4 ;
        RECT  21.462 85.344 21.546 85.368 ;
    END
  END d[417]
  PIN d[418]
    DIRECTION INPUT ;
    USE SIGNAL ;
    PORT
      LAYER M4 ;
        RECT  21.462 85.536 21.546 85.56 ;
    END
  END d[418]
  PIN d[419]
    DIRECTION INPUT ;
    USE SIGNAL ;
    PORT
      LAYER M4 ;
        RECT  21.462 85.728 21.546 85.752 ;
    END
  END d[419]
  PIN d[41]
    DIRECTION INPUT ;
    USE SIGNAL ;
    PORT
      LAYER M4 ;
        RECT  21.462 13.152 21.546 13.176 ;
    END
  END d[41]
  PIN d[420]
    DIRECTION INPUT ;
    USE SIGNAL ;
    PORT
      LAYER M4 ;
        RECT  21.462 85.92 21.546 85.944 ;
    END
  END d[420]
  PIN d[421]
    DIRECTION INPUT ;
    USE SIGNAL ;
    PORT
      LAYER M4 ;
        RECT  21.462 86.112 21.546 86.136 ;
    END
  END d[421]
  PIN d[422]
    DIRECTION INPUT ;
    USE SIGNAL ;
    PORT
      LAYER M4 ;
        RECT  21.462 86.304 21.546 86.328 ;
    END
  END d[422]
  PIN d[423]
    DIRECTION INPUT ;
    USE SIGNAL ;
    PORT
      LAYER M4 ;
        RECT  21.462 86.496 21.546 86.52 ;
    END
  END d[423]
  PIN d[424]
    DIRECTION INPUT ;
    USE SIGNAL ;
    PORT
      LAYER M4 ;
        RECT  21.462 86.688 21.546 86.712 ;
    END
  END d[424]
  PIN d[425]
    DIRECTION INPUT ;
    USE SIGNAL ;
    PORT
      LAYER M4 ;
        RECT  21.462 86.88 21.546 86.904 ;
    END
  END d[425]
  PIN d[426]
    DIRECTION INPUT ;
    USE SIGNAL ;
    PORT
      LAYER M4 ;
        RECT  21.462 87.072 21.546 87.096 ;
    END
  END d[426]
  PIN d[427]
    DIRECTION INPUT ;
    USE SIGNAL ;
    PORT
      LAYER M4 ;
        RECT  21.462 87.264 21.546 87.288 ;
    END
  END d[427]
  PIN d[428]
    DIRECTION INPUT ;
    USE SIGNAL ;
    PORT
      LAYER M4 ;
        RECT  21.462 87.456 21.546 87.48 ;
    END
  END d[428]
  PIN d[429]
    DIRECTION INPUT ;
    USE SIGNAL ;
    PORT
      LAYER M4 ;
        RECT  21.462 87.648 21.546 87.672 ;
    END
  END d[429]
  PIN d[42]
    DIRECTION INPUT ;
    USE SIGNAL ;
    PORT
      LAYER M4 ;
        RECT  21.462 13.344 21.546 13.368 ;
    END
  END d[42]
  PIN d[430]
    DIRECTION INPUT ;
    USE SIGNAL ;
    PORT
      LAYER M4 ;
        RECT  21.462 87.84 21.546 87.864 ;
    END
  END d[430]
  PIN d[431]
    DIRECTION INPUT ;
    USE SIGNAL ;
    PORT
      LAYER M4 ;
        RECT  21.462 88.032 21.546 88.056 ;
    END
  END d[431]
  PIN d[432]
    DIRECTION INPUT ;
    USE SIGNAL ;
    PORT
      LAYER M4 ;
        RECT  21.462 88.224 21.546 88.248 ;
    END
  END d[432]
  PIN d[433]
    DIRECTION INPUT ;
    USE SIGNAL ;
    PORT
      LAYER M4 ;
        RECT  21.462 88.416 21.546 88.44 ;
    END
  END d[433]
  PIN d[434]
    DIRECTION INPUT ;
    USE SIGNAL ;
    PORT
      LAYER M4 ;
        RECT  21.462 88.608 21.546 88.632 ;
    END
  END d[434]
  PIN d[435]
    DIRECTION INPUT ;
    USE SIGNAL ;
    PORT
      LAYER M4 ;
        RECT  21.462 88.8 21.546 88.824 ;
    END
  END d[435]
  PIN d[436]
    DIRECTION INPUT ;
    USE SIGNAL ;
    PORT
      LAYER M4 ;
        RECT  21.462 88.992 21.546 89.016 ;
    END
  END d[436]
  PIN d[437]
    DIRECTION INPUT ;
    USE SIGNAL ;
    PORT
      LAYER M4 ;
        RECT  21.462 89.184 21.546 89.208 ;
    END
  END d[437]
  PIN d[438]
    DIRECTION INPUT ;
    USE SIGNAL ;
    PORT
      LAYER M4 ;
        RECT  21.462 89.376 21.546 89.4 ;
    END
  END d[438]
  PIN d[439]
    DIRECTION INPUT ;
    USE SIGNAL ;
    PORT
      LAYER M4 ;
        RECT  21.462 89.568 21.546 89.592 ;
    END
  END d[439]
  PIN d[43]
    DIRECTION INPUT ;
    USE SIGNAL ;
    PORT
      LAYER M4 ;
        RECT  21.462 13.536 21.546 13.56 ;
    END
  END d[43]
  PIN d[440]
    DIRECTION INPUT ;
    USE SIGNAL ;
    PORT
      LAYER M4 ;
        RECT  21.462 89.76 21.546 89.784 ;
    END
  END d[440]
  PIN d[441]
    DIRECTION INPUT ;
    USE SIGNAL ;
    PORT
      LAYER M4 ;
        RECT  21.462 89.952 21.546 89.976 ;
    END
  END d[441]
  PIN d[442]
    DIRECTION INPUT ;
    USE SIGNAL ;
    PORT
      LAYER M4 ;
        RECT  21.462 90.144 21.546 90.168 ;
    END
  END d[442]
  PIN d[443]
    DIRECTION INPUT ;
    USE SIGNAL ;
    PORT
      LAYER M4 ;
        RECT  21.462 90.336 21.546 90.36 ;
    END
  END d[443]
  PIN d[444]
    DIRECTION INPUT ;
    USE SIGNAL ;
    PORT
      LAYER M4 ;
        RECT  21.462 90.528 21.546 90.552 ;
    END
  END d[444]
  PIN d[445]
    DIRECTION INPUT ;
    USE SIGNAL ;
    PORT
      LAYER M4 ;
        RECT  21.462 90.72 21.546 90.744 ;
    END
  END d[445]
  PIN d[446]
    DIRECTION INPUT ;
    USE SIGNAL ;
    PORT
      LAYER M4 ;
        RECT  21.462 90.912 21.546 90.936 ;
    END
  END d[446]
  PIN d[447]
    DIRECTION INPUT ;
    USE SIGNAL ;
    PORT
      LAYER M4 ;
        RECT  21.462 91.104 21.546 91.128 ;
    END
  END d[447]
  PIN d[448]
    DIRECTION INPUT ;
    USE SIGNAL ;
    PORT
      LAYER M4 ;
        RECT  21.462 91.296 21.546 91.32 ;
    END
  END d[448]
  PIN d[449]
    DIRECTION INPUT ;
    USE SIGNAL ;
    PORT
      LAYER M4 ;
        RECT  21.462 91.488 21.546 91.512 ;
    END
  END d[449]
  PIN d[44]
    DIRECTION INPUT ;
    USE SIGNAL ;
    PORT
      LAYER M4 ;
        RECT  21.462 13.728 21.546 13.752 ;
    END
  END d[44]
  PIN d[450]
    DIRECTION INPUT ;
    USE SIGNAL ;
    PORT
      LAYER M4 ;
        RECT  21.462 91.68 21.546 91.704 ;
    END
  END d[450]
  PIN d[451]
    DIRECTION INPUT ;
    USE SIGNAL ;
    PORT
      LAYER M4 ;
        RECT  21.462 91.872 21.546 91.896 ;
    END
  END d[451]
  PIN d[452]
    DIRECTION INPUT ;
    USE SIGNAL ;
    PORT
      LAYER M4 ;
        RECT  21.462 92.064 21.546 92.088 ;
    END
  END d[452]
  PIN d[453]
    DIRECTION INPUT ;
    USE SIGNAL ;
    PORT
      LAYER M4 ;
        RECT  21.462 92.256 21.546 92.28 ;
    END
  END d[453]
  PIN d[454]
    DIRECTION INPUT ;
    USE SIGNAL ;
    PORT
      LAYER M4 ;
        RECT  21.462 92.448 21.546 92.472 ;
    END
  END d[454]
  PIN d[455]
    DIRECTION INPUT ;
    USE SIGNAL ;
    PORT
      LAYER M4 ;
        RECT  21.462 92.64 21.546 92.664 ;
    END
  END d[455]
  PIN d[456]
    DIRECTION INPUT ;
    USE SIGNAL ;
    PORT
      LAYER M4 ;
        RECT  21.462 92.832 21.546 92.856 ;
    END
  END d[456]
  PIN d[457]
    DIRECTION INPUT ;
    USE SIGNAL ;
    PORT
      LAYER M4 ;
        RECT  21.462 93.024 21.546 93.048 ;
    END
  END d[457]
  PIN d[458]
    DIRECTION INPUT ;
    USE SIGNAL ;
    PORT
      LAYER M4 ;
        RECT  21.462 93.216 21.546 93.24 ;
    END
  END d[458]
  PIN d[459]
    DIRECTION INPUT ;
    USE SIGNAL ;
    PORT
      LAYER M4 ;
        RECT  21.462 93.408 21.546 93.432 ;
    END
  END d[459]
  PIN d[45]
    DIRECTION INPUT ;
    USE SIGNAL ;
    PORT
      LAYER M4 ;
        RECT  21.462 13.92 21.546 13.944 ;
    END
  END d[45]
  PIN d[460]
    DIRECTION INPUT ;
    USE SIGNAL ;
    PORT
      LAYER M4 ;
        RECT  21.462 93.6 21.546 93.624 ;
    END
  END d[460]
  PIN d[461]
    DIRECTION INPUT ;
    USE SIGNAL ;
    PORT
      LAYER M4 ;
        RECT  21.462 93.792 21.546 93.816 ;
    END
  END d[461]
  PIN d[462]
    DIRECTION INPUT ;
    USE SIGNAL ;
    PORT
      LAYER M4 ;
        RECT  21.462 93.984 21.546 94.008 ;
    END
  END d[462]
  PIN d[463]
    DIRECTION INPUT ;
    USE SIGNAL ;
    PORT
      LAYER M4 ;
        RECT  21.462 94.176 21.546 94.2 ;
    END
  END d[463]
  PIN d[464]
    DIRECTION INPUT ;
    USE SIGNAL ;
    PORT
      LAYER M4 ;
        RECT  21.462 94.368 21.546 94.392 ;
    END
  END d[464]
  PIN d[465]
    DIRECTION INPUT ;
    USE SIGNAL ;
    PORT
      LAYER M4 ;
        RECT  21.462 94.56 21.546 94.584 ;
    END
  END d[465]
  PIN d[466]
    DIRECTION INPUT ;
    USE SIGNAL ;
    PORT
      LAYER M4 ;
        RECT  21.462 94.752 21.546 94.776 ;
    END
  END d[466]
  PIN d[467]
    DIRECTION INPUT ;
    USE SIGNAL ;
    PORT
      LAYER M4 ;
        RECT  21.462 94.944 21.546 94.968 ;
    END
  END d[467]
  PIN d[468]
    DIRECTION INPUT ;
    USE SIGNAL ;
    PORT
      LAYER M4 ;
        RECT  21.462 95.136 21.546 95.16 ;
    END
  END d[468]
  PIN d[469]
    DIRECTION INPUT ;
    USE SIGNAL ;
    PORT
      LAYER M4 ;
        RECT  21.462 95.328 21.546 95.352 ;
    END
  END d[469]
  PIN d[46]
    DIRECTION INPUT ;
    USE SIGNAL ;
    PORT
      LAYER M4 ;
        RECT  21.462 14.112 21.546 14.136 ;
    END
  END d[46]
  PIN d[470]
    DIRECTION INPUT ;
    USE SIGNAL ;
    PORT
      LAYER M4 ;
        RECT  21.462 95.52 21.546 95.544 ;
    END
  END d[470]
  PIN d[471]
    DIRECTION INPUT ;
    USE SIGNAL ;
    PORT
      LAYER M4 ;
        RECT  21.462 95.712 21.546 95.736 ;
    END
  END d[471]
  PIN d[472]
    DIRECTION INPUT ;
    USE SIGNAL ;
    PORT
      LAYER M4 ;
        RECT  21.462 95.904 21.546 95.928 ;
    END
  END d[472]
  PIN d[473]
    DIRECTION INPUT ;
    USE SIGNAL ;
    PORT
      LAYER M4 ;
        RECT  21.462 96.096 21.546 96.12 ;
    END
  END d[473]
  PIN d[474]
    DIRECTION INPUT ;
    USE SIGNAL ;
    PORT
      LAYER M4 ;
        RECT  21.462 96.288 21.546 96.312 ;
    END
  END d[474]
  PIN d[475]
    DIRECTION INPUT ;
    USE SIGNAL ;
    PORT
      LAYER M4 ;
        RECT  21.462 96.48 21.546 96.504 ;
    END
  END d[475]
  PIN d[476]
    DIRECTION INPUT ;
    USE SIGNAL ;
    PORT
      LAYER M4 ;
        RECT  21.462 96.672 21.546 96.696 ;
    END
  END d[476]
  PIN d[477]
    DIRECTION INPUT ;
    USE SIGNAL ;
    PORT
      LAYER M4 ;
        RECT  21.462 96.864 21.546 96.888 ;
    END
  END d[477]
  PIN d[478]
    DIRECTION INPUT ;
    USE SIGNAL ;
    PORT
      LAYER M4 ;
        RECT  21.462 97.056 21.546 97.08 ;
    END
  END d[478]
  PIN d[479]
    DIRECTION INPUT ;
    USE SIGNAL ;
    PORT
      LAYER M4 ;
        RECT  21.462 97.248 21.546 97.272 ;
    END
  END d[479]
  PIN d[47]
    DIRECTION INPUT ;
    USE SIGNAL ;
    PORT
      LAYER M4 ;
        RECT  21.462 14.304 21.546 14.328 ;
    END
  END d[47]
  PIN d[480]
    DIRECTION INPUT ;
    USE SIGNAL ;
    PORT
      LAYER M4 ;
        RECT  21.462 97.44 21.546 97.464 ;
    END
  END d[480]
  PIN d[481]
    DIRECTION INPUT ;
    USE SIGNAL ;
    PORT
      LAYER M4 ;
        RECT  21.462 97.632 21.546 97.656 ;
    END
  END d[481]
  PIN d[482]
    DIRECTION INPUT ;
    USE SIGNAL ;
    PORT
      LAYER M4 ;
        RECT  21.462 97.824 21.546 97.848 ;
    END
  END d[482]
  PIN d[483]
    DIRECTION INPUT ;
    USE SIGNAL ;
    PORT
      LAYER M4 ;
        RECT  21.462 98.016 21.546 98.04 ;
    END
  END d[483]
  PIN d[484]
    DIRECTION INPUT ;
    USE SIGNAL ;
    PORT
      LAYER M4 ;
        RECT  21.462 98.208 21.546 98.232 ;
    END
  END d[484]
  PIN d[485]
    DIRECTION INPUT ;
    USE SIGNAL ;
    PORT
      LAYER M4 ;
        RECT  21.462 98.4 21.546 98.424 ;
    END
  END d[485]
  PIN d[486]
    DIRECTION INPUT ;
    USE SIGNAL ;
    PORT
      LAYER M4 ;
        RECT  21.462 98.592 21.546 98.616 ;
    END
  END d[486]
  PIN d[487]
    DIRECTION INPUT ;
    USE SIGNAL ;
    PORT
      LAYER M4 ;
        RECT  21.462 98.784 21.546 98.808 ;
    END
  END d[487]
  PIN d[488]
    DIRECTION INPUT ;
    USE SIGNAL ;
    PORT
      LAYER M4 ;
        RECT  21.462 98.976 21.546 99 ;
    END
  END d[488]
  PIN d[489]
    DIRECTION INPUT ;
    USE SIGNAL ;
    PORT
      LAYER M4 ;
        RECT  21.462 99.168 21.546 99.192 ;
    END
  END d[489]
  PIN d[48]
    DIRECTION INPUT ;
    USE SIGNAL ;
    PORT
      LAYER M4 ;
        RECT  21.462 14.496 21.546 14.52 ;
    END
  END d[48]
  PIN d[490]
    DIRECTION INPUT ;
    USE SIGNAL ;
    PORT
      LAYER M4 ;
        RECT  21.462 99.36 21.546 99.384 ;
    END
  END d[490]
  PIN d[491]
    DIRECTION INPUT ;
    USE SIGNAL ;
    PORT
      LAYER M4 ;
        RECT  21.462 99.552 21.546 99.576 ;
    END
  END d[491]
  PIN d[492]
    DIRECTION INPUT ;
    USE SIGNAL ;
    PORT
      LAYER M4 ;
        RECT  21.462 99.744 21.546 99.768 ;
    END
  END d[492]
  PIN d[493]
    DIRECTION INPUT ;
    USE SIGNAL ;
    PORT
      LAYER M4 ;
        RECT  21.462 99.936 21.546 99.96 ;
    END
  END d[493]
  PIN d[494]
    DIRECTION INPUT ;
    USE SIGNAL ;
    PORT
      LAYER M4 ;
        RECT  21.462 100.128 21.546 100.152 ;
    END
  END d[494]
  PIN d[495]
    DIRECTION INPUT ;
    USE SIGNAL ;
    PORT
      LAYER M4 ;
        RECT  21.462 100.32 21.546 100.344 ;
    END
  END d[495]
  PIN d[496]
    DIRECTION INPUT ;
    USE SIGNAL ;
    PORT
      LAYER M4 ;
        RECT  21.462 100.512 21.546 100.536 ;
    END
  END d[496]
  PIN d[497]
    DIRECTION INPUT ;
    USE SIGNAL ;
    PORT
      LAYER M4 ;
        RECT  21.462 100.704 21.546 100.728 ;
    END
  END d[497]
  PIN d[498]
    DIRECTION INPUT ;
    USE SIGNAL ;
    PORT
      LAYER M4 ;
        RECT  21.462 100.896 21.546 100.92 ;
    END
  END d[498]
  PIN d[499]
    DIRECTION INPUT ;
    USE SIGNAL ;
    PORT
      LAYER M4 ;
        RECT  21.462 101.088 21.546 101.112 ;
    END
  END d[499]
  PIN d[49]
    DIRECTION INPUT ;
    USE SIGNAL ;
    PORT
      LAYER M4 ;
        RECT  21.462 14.688 21.546 14.712 ;
    END
  END d[49]
  PIN d[4]
    DIRECTION INPUT ;
    USE SIGNAL ;
    PORT
      LAYER M4 ;
        RECT  21.462 6.048 21.546 6.072 ;
    END
  END d[4]
  PIN d[500]
    DIRECTION INPUT ;
    USE SIGNAL ;
    PORT
      LAYER M4 ;
        RECT  21.462 101.28 21.546 101.304 ;
    END
  END d[500]
  PIN d[501]
    DIRECTION INPUT ;
    USE SIGNAL ;
    PORT
      LAYER M4 ;
        RECT  21.462 101.472 21.546 101.496 ;
    END
  END d[501]
  PIN d[502]
    DIRECTION INPUT ;
    USE SIGNAL ;
    PORT
      LAYER M4 ;
        RECT  21.462 101.664 21.546 101.688 ;
    END
  END d[502]
  PIN d[503]
    DIRECTION INPUT ;
    USE SIGNAL ;
    PORT
      LAYER M4 ;
        RECT  21.462 101.856 21.546 101.88 ;
    END
  END d[503]
  PIN d[504]
    DIRECTION INPUT ;
    USE SIGNAL ;
    PORT
      LAYER M4 ;
        RECT  21.462 102.048 21.546 102.072 ;
    END
  END d[504]
  PIN d[505]
    DIRECTION INPUT ;
    USE SIGNAL ;
    PORT
      LAYER M4 ;
        RECT  21.462 102.24 21.546 102.264 ;
    END
  END d[505]
  PIN d[506]
    DIRECTION INPUT ;
    USE SIGNAL ;
    PORT
      LAYER M4 ;
        RECT  21.462 102.432 21.546 102.456 ;
    END
  END d[506]
  PIN d[507]
    DIRECTION INPUT ;
    USE SIGNAL ;
    PORT
      LAYER M4 ;
        RECT  21.462 102.624 21.546 102.648 ;
    END
  END d[507]
  PIN d[508]
    DIRECTION INPUT ;
    USE SIGNAL ;
    PORT
      LAYER M4 ;
        RECT  21.462 102.816 21.546 102.84 ;
    END
  END d[508]
  PIN d[509]
    DIRECTION INPUT ;
    USE SIGNAL ;
    PORT
      LAYER M4 ;
        RECT  21.462 103.008 21.546 103.032 ;
    END
  END d[509]
  PIN d[50]
    DIRECTION INPUT ;
    USE SIGNAL ;
    PORT
      LAYER M4 ;
        RECT  21.462 14.88 21.546 14.904 ;
    END
  END d[50]
  PIN d[510]
    DIRECTION INPUT ;
    USE SIGNAL ;
    PORT
      LAYER M4 ;
        RECT  21.462 103.2 21.546 103.224 ;
    END
  END d[510]
  PIN d[511]
    DIRECTION INPUT ;
    USE SIGNAL ;
    PORT
      LAYER M4 ;
        RECT  21.462 103.392 21.546 103.416 ;
    END
  END d[511]
  PIN d[512]
    DIRECTION INPUT ;
    USE SIGNAL ;
    PORT
      LAYER M4 ;
        RECT  21.462 103.584 21.546 103.608 ;
    END
  END d[512]
  PIN d[513]
    DIRECTION INPUT ;
    USE SIGNAL ;
    PORT
      LAYER M4 ;
        RECT  21.462 103.776 21.546 103.8 ;
    END
  END d[513]
  PIN d[51]
    DIRECTION INPUT ;
    USE SIGNAL ;
    PORT
      LAYER M4 ;
        RECT  21.462 15.072 21.546 15.096 ;
    END
  END d[51]
  PIN d[52]
    DIRECTION INPUT ;
    USE SIGNAL ;
    PORT
      LAYER M4 ;
        RECT  21.462 15.264 21.546 15.288 ;
    END
  END d[52]
  PIN d[53]
    DIRECTION INPUT ;
    USE SIGNAL ;
    PORT
      LAYER M4 ;
        RECT  21.462 15.456 21.546 15.48 ;
    END
  END d[53]
  PIN d[54]
    DIRECTION INPUT ;
    USE SIGNAL ;
    PORT
      LAYER M4 ;
        RECT  21.462 15.648 21.546 15.672 ;
    END
  END d[54]
  PIN d[55]
    DIRECTION INPUT ;
    USE SIGNAL ;
    PORT
      LAYER M4 ;
        RECT  21.462 15.84 21.546 15.864 ;
    END
  END d[55]
  PIN d[56]
    DIRECTION INPUT ;
    USE SIGNAL ;
    PORT
      LAYER M4 ;
        RECT  21.462 16.032 21.546 16.056 ;
    END
  END d[56]
  PIN d[57]
    DIRECTION INPUT ;
    USE SIGNAL ;
    PORT
      LAYER M4 ;
        RECT  21.462 16.224 21.546 16.248 ;
    END
  END d[57]
  PIN d[58]
    DIRECTION INPUT ;
    USE SIGNAL ;
    PORT
      LAYER M4 ;
        RECT  21.462 16.416 21.546 16.44 ;
    END
  END d[58]
  PIN d[59]
    DIRECTION INPUT ;
    USE SIGNAL ;
    PORT
      LAYER M4 ;
        RECT  21.462 16.608 21.546 16.632 ;
    END
  END d[59]
  PIN d[5]
    DIRECTION INPUT ;
    USE SIGNAL ;
    PORT
      LAYER M4 ;
        RECT  21.462 6.24 21.546 6.264 ;
    END
  END d[5]
  PIN d[60]
    DIRECTION INPUT ;
    USE SIGNAL ;
    PORT
      LAYER M4 ;
        RECT  21.462 16.8 21.546 16.824 ;
    END
  END d[60]
  PIN d[61]
    DIRECTION INPUT ;
    USE SIGNAL ;
    PORT
      LAYER M4 ;
        RECT  21.462 16.992 21.546 17.016 ;
    END
  END d[61]
  PIN d[62]
    DIRECTION INPUT ;
    USE SIGNAL ;
    PORT
      LAYER M4 ;
        RECT  21.462 17.184 21.546 17.208 ;
    END
  END d[62]
  PIN d[63]
    DIRECTION INPUT ;
    USE SIGNAL ;
    PORT
      LAYER M4 ;
        RECT  21.462 17.376 21.546 17.4 ;
    END
  END d[63]
  PIN d[64]
    DIRECTION INPUT ;
    USE SIGNAL ;
    PORT
      LAYER M4 ;
        RECT  21.462 17.568 21.546 17.592 ;
    END
  END d[64]
  PIN d[65]
    DIRECTION INPUT ;
    USE SIGNAL ;
    PORT
      LAYER M4 ;
        RECT  21.462 17.76 21.546 17.784 ;
    END
  END d[65]
  PIN d[66]
    DIRECTION INPUT ;
    USE SIGNAL ;
    PORT
      LAYER M4 ;
        RECT  21.462 17.952 21.546 17.976 ;
    END
  END d[66]
  PIN d[67]
    DIRECTION INPUT ;
    USE SIGNAL ;
    PORT
      LAYER M4 ;
        RECT  21.462 18.144 21.546 18.168 ;
    END
  END d[67]
  PIN d[68]
    DIRECTION INPUT ;
    USE SIGNAL ;
    PORT
      LAYER M4 ;
        RECT  21.462 18.336 21.546 18.36 ;
    END
  END d[68]
  PIN d[69]
    DIRECTION INPUT ;
    USE SIGNAL ;
    PORT
      LAYER M4 ;
        RECT  21.462 18.528 21.546 18.552 ;
    END
  END d[69]
  PIN d[6]
    DIRECTION INPUT ;
    USE SIGNAL ;
    PORT
      LAYER M4 ;
        RECT  21.462 6.432 21.546 6.456 ;
    END
  END d[6]
  PIN d[70]
    DIRECTION INPUT ;
    USE SIGNAL ;
    PORT
      LAYER M4 ;
        RECT  21.462 18.72 21.546 18.744 ;
    END
  END d[70]
  PIN d[71]
    DIRECTION INPUT ;
    USE SIGNAL ;
    PORT
      LAYER M4 ;
        RECT  21.462 18.912 21.546 18.936 ;
    END
  END d[71]
  PIN d[72]
    DIRECTION INPUT ;
    USE SIGNAL ;
    PORT
      LAYER M4 ;
        RECT  21.462 19.104 21.546 19.128 ;
    END
  END d[72]
  PIN d[73]
    DIRECTION INPUT ;
    USE SIGNAL ;
    PORT
      LAYER M4 ;
        RECT  21.462 19.296 21.546 19.32 ;
    END
  END d[73]
  PIN d[74]
    DIRECTION INPUT ;
    USE SIGNAL ;
    PORT
      LAYER M4 ;
        RECT  21.462 19.488 21.546 19.512 ;
    END
  END d[74]
  PIN d[75]
    DIRECTION INPUT ;
    USE SIGNAL ;
    PORT
      LAYER M4 ;
        RECT  21.462 19.68 21.546 19.704 ;
    END
  END d[75]
  PIN d[76]
    DIRECTION INPUT ;
    USE SIGNAL ;
    PORT
      LAYER M4 ;
        RECT  21.462 19.872 21.546 19.896 ;
    END
  END d[76]
  PIN d[77]
    DIRECTION INPUT ;
    USE SIGNAL ;
    PORT
      LAYER M4 ;
        RECT  21.462 20.064 21.546 20.088 ;
    END
  END d[77]
  PIN d[78]
    DIRECTION INPUT ;
    USE SIGNAL ;
    PORT
      LAYER M4 ;
        RECT  21.462 20.256 21.546 20.28 ;
    END
  END d[78]
  PIN d[79]
    DIRECTION INPUT ;
    USE SIGNAL ;
    PORT
      LAYER M4 ;
        RECT  21.462 20.448 21.546 20.472 ;
    END
  END d[79]
  PIN d[7]
    DIRECTION INPUT ;
    USE SIGNAL ;
    PORT
      LAYER M4 ;
        RECT  21.462 6.624 21.546 6.648 ;
    END
  END d[7]
  PIN d[80]
    DIRECTION INPUT ;
    USE SIGNAL ;
    PORT
      LAYER M4 ;
        RECT  21.462 20.64 21.546 20.664 ;
    END
  END d[80]
  PIN d[81]
    DIRECTION INPUT ;
    USE SIGNAL ;
    PORT
      LAYER M4 ;
        RECT  21.462 20.832 21.546 20.856 ;
    END
  END d[81]
  PIN d[82]
    DIRECTION INPUT ;
    USE SIGNAL ;
    PORT
      LAYER M4 ;
        RECT  21.462 21.024 21.546 21.048 ;
    END
  END d[82]
  PIN d[83]
    DIRECTION INPUT ;
    USE SIGNAL ;
    PORT
      LAYER M4 ;
        RECT  21.462 21.216 21.546 21.24 ;
    END
  END d[83]
  PIN d[84]
    DIRECTION INPUT ;
    USE SIGNAL ;
    PORT
      LAYER M4 ;
        RECT  21.462 21.408 21.546 21.432 ;
    END
  END d[84]
  PIN d[85]
    DIRECTION INPUT ;
    USE SIGNAL ;
    PORT
      LAYER M4 ;
        RECT  21.462 21.6 21.546 21.624 ;
    END
  END d[85]
  PIN d[86]
    DIRECTION INPUT ;
    USE SIGNAL ;
    PORT
      LAYER M4 ;
        RECT  21.462 21.792 21.546 21.816 ;
    END
  END d[86]
  PIN d[87]
    DIRECTION INPUT ;
    USE SIGNAL ;
    PORT
      LAYER M4 ;
        RECT  21.462 21.984 21.546 22.008 ;
    END
  END d[87]
  PIN d[88]
    DIRECTION INPUT ;
    USE SIGNAL ;
    PORT
      LAYER M4 ;
        RECT  21.462 22.176 21.546 22.2 ;
    END
  END d[88]
  PIN d[89]
    DIRECTION INPUT ;
    USE SIGNAL ;
    PORT
      LAYER M4 ;
        RECT  21.462 22.368 21.546 22.392 ;
    END
  END d[89]
  PIN d[8]
    DIRECTION INPUT ;
    USE SIGNAL ;
    PORT
      LAYER M4 ;
        RECT  21.462 6.816 21.546 6.84 ;
    END
  END d[8]
  PIN d[90]
    DIRECTION INPUT ;
    USE SIGNAL ;
    PORT
      LAYER M4 ;
        RECT  21.462 22.56 21.546 22.584 ;
    END
  END d[90]
  PIN d[91]
    DIRECTION INPUT ;
    USE SIGNAL ;
    PORT
      LAYER M4 ;
        RECT  21.462 22.752 21.546 22.776 ;
    END
  END d[91]
  PIN d[92]
    DIRECTION INPUT ;
    USE SIGNAL ;
    PORT
      LAYER M4 ;
        RECT  21.462 22.944 21.546 22.968 ;
    END
  END d[92]
  PIN d[93]
    DIRECTION INPUT ;
    USE SIGNAL ;
    PORT
      LAYER M4 ;
        RECT  21.462 23.136 21.546 23.16 ;
    END
  END d[93]
  PIN d[94]
    DIRECTION INPUT ;
    USE SIGNAL ;
    PORT
      LAYER M4 ;
        RECT  21.462 23.328 21.546 23.352 ;
    END
  END d[94]
  PIN d[95]
    DIRECTION INPUT ;
    USE SIGNAL ;
    PORT
      LAYER M4 ;
        RECT  21.462 23.52 21.546 23.544 ;
    END
  END d[95]
  PIN d[96]
    DIRECTION INPUT ;
    USE SIGNAL ;
    PORT
      LAYER M4 ;
        RECT  21.462 23.712 21.546 23.736 ;
    END
  END d[96]
  PIN d[97]
    DIRECTION INPUT ;
    USE SIGNAL ;
    PORT
      LAYER M4 ;
        RECT  21.462 23.904 21.546 23.928 ;
    END
  END d[97]
  PIN d[98]
    DIRECTION INPUT ;
    USE SIGNAL ;
    PORT
      LAYER M4 ;
        RECT  21.462 24.096 21.546 24.12 ;
    END
  END d[98]
  PIN d[99]
    DIRECTION INPUT ;
    USE SIGNAL ;
    PORT
      LAYER M4 ;
        RECT  21.462 24.288 21.546 24.312 ;
    END
  END d[99]
  PIN d[9]
    DIRECTION INPUT ;
    USE SIGNAL ;
    PORT
      LAYER M4 ;
        RECT  21.462 7.008 21.546 7.032 ;
    END
  END d[9]
  PIN q[0]
    DIRECTION OUTPUT ;
    USE SIGNAL ;
    PORT
      LAYER M4 ;
        RECT  0.054 5.28 0.138 5.304 ;
    END
  END q[0]
  PIN q[100]
    DIRECTION OUTPUT ;
    USE SIGNAL ;
    PORT
      LAYER M4 ;
        RECT  0.054 24.48 0.138 24.504 ;
    END
  END q[100]
  PIN q[101]
    DIRECTION OUTPUT ;
    USE SIGNAL ;
    PORT
      LAYER M4 ;
        RECT  0.054 24.672 0.138 24.696 ;
    END
  END q[101]
  PIN q[102]
    DIRECTION OUTPUT ;
    USE SIGNAL ;
    PORT
      LAYER M4 ;
        RECT  0.054 24.864 0.138 24.888 ;
    END
  END q[102]
  PIN q[103]
    DIRECTION OUTPUT ;
    USE SIGNAL ;
    PORT
      LAYER M4 ;
        RECT  0.054 25.056 0.138 25.08 ;
    END
  END q[103]
  PIN q[104]
    DIRECTION OUTPUT ;
    USE SIGNAL ;
    PORT
      LAYER M4 ;
        RECT  0.054 25.248 0.138 25.272 ;
    END
  END q[104]
  PIN q[105]
    DIRECTION OUTPUT ;
    USE SIGNAL ;
    PORT
      LAYER M4 ;
        RECT  0.054 25.44 0.138 25.464 ;
    END
  END q[105]
  PIN q[106]
    DIRECTION OUTPUT ;
    USE SIGNAL ;
    PORT
      LAYER M4 ;
        RECT  0.054 25.632 0.138 25.656 ;
    END
  END q[106]
  PIN q[107]
    DIRECTION OUTPUT ;
    USE SIGNAL ;
    PORT
      LAYER M4 ;
        RECT  0.054 25.824 0.138 25.848 ;
    END
  END q[107]
  PIN q[108]
    DIRECTION OUTPUT ;
    USE SIGNAL ;
    PORT
      LAYER M4 ;
        RECT  0.054 26.016 0.138 26.04 ;
    END
  END q[108]
  PIN q[109]
    DIRECTION OUTPUT ;
    USE SIGNAL ;
    PORT
      LAYER M4 ;
        RECT  0.054 26.208 0.138 26.232 ;
    END
  END q[109]
  PIN q[10]
    DIRECTION OUTPUT ;
    USE SIGNAL ;
    PORT
      LAYER M4 ;
        RECT  0.054 7.2 0.138 7.224 ;
    END
  END q[10]
  PIN q[110]
    DIRECTION OUTPUT ;
    USE SIGNAL ;
    PORT
      LAYER M4 ;
        RECT  0.054 26.4 0.138 26.424 ;
    END
  END q[110]
  PIN q[111]
    DIRECTION OUTPUT ;
    USE SIGNAL ;
    PORT
      LAYER M4 ;
        RECT  0.054 26.592 0.138 26.616 ;
    END
  END q[111]
  PIN q[112]
    DIRECTION OUTPUT ;
    USE SIGNAL ;
    PORT
      LAYER M4 ;
        RECT  0.054 26.784 0.138 26.808 ;
    END
  END q[112]
  PIN q[113]
    DIRECTION OUTPUT ;
    USE SIGNAL ;
    PORT
      LAYER M4 ;
        RECT  0.054 26.976 0.138 27 ;
    END
  END q[113]
  PIN q[114]
    DIRECTION OUTPUT ;
    USE SIGNAL ;
    PORT
      LAYER M4 ;
        RECT  0.054 27.168 0.138 27.192 ;
    END
  END q[114]
  PIN q[115]
    DIRECTION OUTPUT ;
    USE SIGNAL ;
    PORT
      LAYER M4 ;
        RECT  0.054 27.36 0.138 27.384 ;
    END
  END q[115]
  PIN q[116]
    DIRECTION OUTPUT ;
    USE SIGNAL ;
    PORT
      LAYER M4 ;
        RECT  0.054 27.552 0.138 27.576 ;
    END
  END q[116]
  PIN q[117]
    DIRECTION OUTPUT ;
    USE SIGNAL ;
    PORT
      LAYER M4 ;
        RECT  0.054 27.744 0.138 27.768 ;
    END
  END q[117]
  PIN q[118]
    DIRECTION OUTPUT ;
    USE SIGNAL ;
    PORT
      LAYER M4 ;
        RECT  0.054 27.936 0.138 27.96 ;
    END
  END q[118]
  PIN q[119]
    DIRECTION OUTPUT ;
    USE SIGNAL ;
    PORT
      LAYER M4 ;
        RECT  0.054 28.128 0.138 28.152 ;
    END
  END q[119]
  PIN q[11]
    DIRECTION OUTPUT ;
    USE SIGNAL ;
    PORT
      LAYER M4 ;
        RECT  0.054 7.392 0.138 7.416 ;
    END
  END q[11]
  PIN q[120]
    DIRECTION OUTPUT ;
    USE SIGNAL ;
    PORT
      LAYER M4 ;
        RECT  0.054 28.32 0.138 28.344 ;
    END
  END q[120]
  PIN q[121]
    DIRECTION OUTPUT ;
    USE SIGNAL ;
    PORT
      LAYER M4 ;
        RECT  0.054 28.512 0.138 28.536 ;
    END
  END q[121]
  PIN q[122]
    DIRECTION OUTPUT ;
    USE SIGNAL ;
    PORT
      LAYER M4 ;
        RECT  0.054 28.704 0.138 28.728 ;
    END
  END q[122]
  PIN q[123]
    DIRECTION OUTPUT ;
    USE SIGNAL ;
    PORT
      LAYER M4 ;
        RECT  0.054 28.896 0.138 28.92 ;
    END
  END q[123]
  PIN q[124]
    DIRECTION OUTPUT ;
    USE SIGNAL ;
    PORT
      LAYER M4 ;
        RECT  0.054 29.088 0.138 29.112 ;
    END
  END q[124]
  PIN q[125]
    DIRECTION OUTPUT ;
    USE SIGNAL ;
    PORT
      LAYER M4 ;
        RECT  0.054 29.28 0.138 29.304 ;
    END
  END q[125]
  PIN q[126]
    DIRECTION OUTPUT ;
    USE SIGNAL ;
    PORT
      LAYER M4 ;
        RECT  0.054 29.472 0.138 29.496 ;
    END
  END q[126]
  PIN q[127]
    DIRECTION OUTPUT ;
    USE SIGNAL ;
    PORT
      LAYER M4 ;
        RECT  0.054 29.664 0.138 29.688 ;
    END
  END q[127]
  PIN q[128]
    DIRECTION OUTPUT ;
    USE SIGNAL ;
    PORT
      LAYER M4 ;
        RECT  0.054 29.856 0.138 29.88 ;
    END
  END q[128]
  PIN q[129]
    DIRECTION OUTPUT ;
    USE SIGNAL ;
    PORT
      LAYER M4 ;
        RECT  0.054 30.048 0.138 30.072 ;
    END
  END q[129]
  PIN q[12]
    DIRECTION OUTPUT ;
    USE SIGNAL ;
    PORT
      LAYER M4 ;
        RECT  0.054 7.584 0.138 7.608 ;
    END
  END q[12]
  PIN q[130]
    DIRECTION OUTPUT ;
    USE SIGNAL ;
    PORT
      LAYER M4 ;
        RECT  0.054 30.24 0.138 30.264 ;
    END
  END q[130]
  PIN q[131]
    DIRECTION OUTPUT ;
    USE SIGNAL ;
    PORT
      LAYER M4 ;
        RECT  0.054 30.432 0.138 30.456 ;
    END
  END q[131]
  PIN q[132]
    DIRECTION OUTPUT ;
    USE SIGNAL ;
    PORT
      LAYER M4 ;
        RECT  0.054 30.624 0.138 30.648 ;
    END
  END q[132]
  PIN q[133]
    DIRECTION OUTPUT ;
    USE SIGNAL ;
    PORT
      LAYER M4 ;
        RECT  0.054 30.816 0.138 30.84 ;
    END
  END q[133]
  PIN q[134]
    DIRECTION OUTPUT ;
    USE SIGNAL ;
    PORT
      LAYER M4 ;
        RECT  0.054 31.008 0.138 31.032 ;
    END
  END q[134]
  PIN q[135]
    DIRECTION OUTPUT ;
    USE SIGNAL ;
    PORT
      LAYER M4 ;
        RECT  0.054 31.2 0.138 31.224 ;
    END
  END q[135]
  PIN q[136]
    DIRECTION OUTPUT ;
    USE SIGNAL ;
    PORT
      LAYER M4 ;
        RECT  0.054 31.392 0.138 31.416 ;
    END
  END q[136]
  PIN q[137]
    DIRECTION OUTPUT ;
    USE SIGNAL ;
    PORT
      LAYER M4 ;
        RECT  0.054 31.584 0.138 31.608 ;
    END
  END q[137]
  PIN q[138]
    DIRECTION OUTPUT ;
    USE SIGNAL ;
    PORT
      LAYER M4 ;
        RECT  0.054 31.776 0.138 31.8 ;
    END
  END q[138]
  PIN q[139]
    DIRECTION OUTPUT ;
    USE SIGNAL ;
    PORT
      LAYER M4 ;
        RECT  0.054 31.968 0.138 31.992 ;
    END
  END q[139]
  PIN q[13]
    DIRECTION OUTPUT ;
    USE SIGNAL ;
    PORT
      LAYER M4 ;
        RECT  0.054 7.776 0.138 7.8 ;
    END
  END q[13]
  PIN q[140]
    DIRECTION OUTPUT ;
    USE SIGNAL ;
    PORT
      LAYER M4 ;
        RECT  0.054 32.16 0.138 32.184 ;
    END
  END q[140]
  PIN q[141]
    DIRECTION OUTPUT ;
    USE SIGNAL ;
    PORT
      LAYER M4 ;
        RECT  0.054 32.352 0.138 32.376 ;
    END
  END q[141]
  PIN q[142]
    DIRECTION OUTPUT ;
    USE SIGNAL ;
    PORT
      LAYER M4 ;
        RECT  0.054 32.544 0.138 32.568 ;
    END
  END q[142]
  PIN q[143]
    DIRECTION OUTPUT ;
    USE SIGNAL ;
    PORT
      LAYER M4 ;
        RECT  0.054 32.736 0.138 32.76 ;
    END
  END q[143]
  PIN q[144]
    DIRECTION OUTPUT ;
    USE SIGNAL ;
    PORT
      LAYER M4 ;
        RECT  0.054 32.928 0.138 32.952 ;
    END
  END q[144]
  PIN q[145]
    DIRECTION OUTPUT ;
    USE SIGNAL ;
    PORT
      LAYER M4 ;
        RECT  0.054 33.12 0.138 33.144 ;
    END
  END q[145]
  PIN q[146]
    DIRECTION OUTPUT ;
    USE SIGNAL ;
    PORT
      LAYER M4 ;
        RECT  0.054 33.312 0.138 33.336 ;
    END
  END q[146]
  PIN q[147]
    DIRECTION OUTPUT ;
    USE SIGNAL ;
    PORT
      LAYER M4 ;
        RECT  0.054 33.504 0.138 33.528 ;
    END
  END q[147]
  PIN q[148]
    DIRECTION OUTPUT ;
    USE SIGNAL ;
    PORT
      LAYER M4 ;
        RECT  0.054 33.696 0.138 33.72 ;
    END
  END q[148]
  PIN q[149]
    DIRECTION OUTPUT ;
    USE SIGNAL ;
    PORT
      LAYER M4 ;
        RECT  0.054 33.888 0.138 33.912 ;
    END
  END q[149]
  PIN q[14]
    DIRECTION OUTPUT ;
    USE SIGNAL ;
    PORT
      LAYER M4 ;
        RECT  0.054 7.968 0.138 7.992 ;
    END
  END q[14]
  PIN q[150]
    DIRECTION OUTPUT ;
    USE SIGNAL ;
    PORT
      LAYER M4 ;
        RECT  0.054 34.08 0.138 34.104 ;
    END
  END q[150]
  PIN q[151]
    DIRECTION OUTPUT ;
    USE SIGNAL ;
    PORT
      LAYER M4 ;
        RECT  0.054 34.272 0.138 34.296 ;
    END
  END q[151]
  PIN q[152]
    DIRECTION OUTPUT ;
    USE SIGNAL ;
    PORT
      LAYER M4 ;
        RECT  0.054 34.464 0.138 34.488 ;
    END
  END q[152]
  PIN q[153]
    DIRECTION OUTPUT ;
    USE SIGNAL ;
    PORT
      LAYER M4 ;
        RECT  0.054 34.656 0.138 34.68 ;
    END
  END q[153]
  PIN q[154]
    DIRECTION OUTPUT ;
    USE SIGNAL ;
    PORT
      LAYER M4 ;
        RECT  0.054 34.848 0.138 34.872 ;
    END
  END q[154]
  PIN q[155]
    DIRECTION OUTPUT ;
    USE SIGNAL ;
    PORT
      LAYER M4 ;
        RECT  0.054 35.04 0.138 35.064 ;
    END
  END q[155]
  PIN q[156]
    DIRECTION OUTPUT ;
    USE SIGNAL ;
    PORT
      LAYER M4 ;
        RECT  0.054 35.232 0.138 35.256 ;
    END
  END q[156]
  PIN q[157]
    DIRECTION OUTPUT ;
    USE SIGNAL ;
    PORT
      LAYER M4 ;
        RECT  0.054 35.424 0.138 35.448 ;
    END
  END q[157]
  PIN q[158]
    DIRECTION OUTPUT ;
    USE SIGNAL ;
    PORT
      LAYER M4 ;
        RECT  0.054 35.616 0.138 35.64 ;
    END
  END q[158]
  PIN q[159]
    DIRECTION OUTPUT ;
    USE SIGNAL ;
    PORT
      LAYER M4 ;
        RECT  0.054 35.808 0.138 35.832 ;
    END
  END q[159]
  PIN q[15]
    DIRECTION OUTPUT ;
    USE SIGNAL ;
    PORT
      LAYER M4 ;
        RECT  0.054 8.16 0.138 8.184 ;
    END
  END q[15]
  PIN q[160]
    DIRECTION OUTPUT ;
    USE SIGNAL ;
    PORT
      LAYER M4 ;
        RECT  0.054 36 0.138 36.024 ;
    END
  END q[160]
  PIN q[161]
    DIRECTION OUTPUT ;
    USE SIGNAL ;
    PORT
      LAYER M4 ;
        RECT  0.054 36.192 0.138 36.216 ;
    END
  END q[161]
  PIN q[162]
    DIRECTION OUTPUT ;
    USE SIGNAL ;
    PORT
      LAYER M4 ;
        RECT  0.054 36.384 0.138 36.408 ;
    END
  END q[162]
  PIN q[163]
    DIRECTION OUTPUT ;
    USE SIGNAL ;
    PORT
      LAYER M4 ;
        RECT  0.054 36.576 0.138 36.6 ;
    END
  END q[163]
  PIN q[164]
    DIRECTION OUTPUT ;
    USE SIGNAL ;
    PORT
      LAYER M4 ;
        RECT  0.054 36.768 0.138 36.792 ;
    END
  END q[164]
  PIN q[165]
    DIRECTION OUTPUT ;
    USE SIGNAL ;
    PORT
      LAYER M4 ;
        RECT  0.054 36.96 0.138 36.984 ;
    END
  END q[165]
  PIN q[166]
    DIRECTION OUTPUT ;
    USE SIGNAL ;
    PORT
      LAYER M4 ;
        RECT  0.054 37.152 0.138 37.176 ;
    END
  END q[166]
  PIN q[167]
    DIRECTION OUTPUT ;
    USE SIGNAL ;
    PORT
      LAYER M4 ;
        RECT  0.054 37.344 0.138 37.368 ;
    END
  END q[167]
  PIN q[168]
    DIRECTION OUTPUT ;
    USE SIGNAL ;
    PORT
      LAYER M4 ;
        RECT  0.054 37.536 0.138 37.56 ;
    END
  END q[168]
  PIN q[169]
    DIRECTION OUTPUT ;
    USE SIGNAL ;
    PORT
      LAYER M4 ;
        RECT  0.054 37.728 0.138 37.752 ;
    END
  END q[169]
  PIN q[16]
    DIRECTION OUTPUT ;
    USE SIGNAL ;
    PORT
      LAYER M4 ;
        RECT  0.054 8.352 0.138 8.376 ;
    END
  END q[16]
  PIN q[170]
    DIRECTION OUTPUT ;
    USE SIGNAL ;
    PORT
      LAYER M4 ;
        RECT  0.054 37.92 0.138 37.944 ;
    END
  END q[170]
  PIN q[171]
    DIRECTION OUTPUT ;
    USE SIGNAL ;
    PORT
      LAYER M4 ;
        RECT  0.054 38.112 0.138 38.136 ;
    END
  END q[171]
  PIN q[172]
    DIRECTION OUTPUT ;
    USE SIGNAL ;
    PORT
      LAYER M4 ;
        RECT  0.054 38.304 0.138 38.328 ;
    END
  END q[172]
  PIN q[173]
    DIRECTION OUTPUT ;
    USE SIGNAL ;
    PORT
      LAYER M4 ;
        RECT  0.054 38.496 0.138 38.52 ;
    END
  END q[173]
  PIN q[174]
    DIRECTION OUTPUT ;
    USE SIGNAL ;
    PORT
      LAYER M4 ;
        RECT  0.054 38.688 0.138 38.712 ;
    END
  END q[174]
  PIN q[175]
    DIRECTION OUTPUT ;
    USE SIGNAL ;
    PORT
      LAYER M4 ;
        RECT  0.054 38.88 0.138 38.904 ;
    END
  END q[175]
  PIN q[176]
    DIRECTION OUTPUT ;
    USE SIGNAL ;
    PORT
      LAYER M4 ;
        RECT  0.054 39.072 0.138 39.096 ;
    END
  END q[176]
  PIN q[177]
    DIRECTION OUTPUT ;
    USE SIGNAL ;
    PORT
      LAYER M4 ;
        RECT  0.054 39.264 0.138 39.288 ;
    END
  END q[177]
  PIN q[178]
    DIRECTION OUTPUT ;
    USE SIGNAL ;
    PORT
      LAYER M4 ;
        RECT  0.054 39.456 0.138 39.48 ;
    END
  END q[178]
  PIN q[179]
    DIRECTION OUTPUT ;
    USE SIGNAL ;
    PORT
      LAYER M4 ;
        RECT  0.054 39.648 0.138 39.672 ;
    END
  END q[179]
  PIN q[17]
    DIRECTION OUTPUT ;
    USE SIGNAL ;
    PORT
      LAYER M4 ;
        RECT  0.054 8.544 0.138 8.568 ;
    END
  END q[17]
  PIN q[180]
    DIRECTION OUTPUT ;
    USE SIGNAL ;
    PORT
      LAYER M4 ;
        RECT  0.054 39.84 0.138 39.864 ;
    END
  END q[180]
  PIN q[181]
    DIRECTION OUTPUT ;
    USE SIGNAL ;
    PORT
      LAYER M4 ;
        RECT  0.054 40.032 0.138 40.056 ;
    END
  END q[181]
  PIN q[182]
    DIRECTION OUTPUT ;
    USE SIGNAL ;
    PORT
      LAYER M4 ;
        RECT  0.054 40.224 0.138 40.248 ;
    END
  END q[182]
  PIN q[183]
    DIRECTION OUTPUT ;
    USE SIGNAL ;
    PORT
      LAYER M4 ;
        RECT  0.054 40.416 0.138 40.44 ;
    END
  END q[183]
  PIN q[184]
    DIRECTION OUTPUT ;
    USE SIGNAL ;
    PORT
      LAYER M4 ;
        RECT  0.054 40.608 0.138 40.632 ;
    END
  END q[184]
  PIN q[185]
    DIRECTION OUTPUT ;
    USE SIGNAL ;
    PORT
      LAYER M4 ;
        RECT  0.054 40.8 0.138 40.824 ;
    END
  END q[185]
  PIN q[186]
    DIRECTION OUTPUT ;
    USE SIGNAL ;
    PORT
      LAYER M4 ;
        RECT  0.054 40.992 0.138 41.016 ;
    END
  END q[186]
  PIN q[187]
    DIRECTION OUTPUT ;
    USE SIGNAL ;
    PORT
      LAYER M4 ;
        RECT  0.054 41.184 0.138 41.208 ;
    END
  END q[187]
  PIN q[188]
    DIRECTION OUTPUT ;
    USE SIGNAL ;
    PORT
      LAYER M4 ;
        RECT  0.054 41.376 0.138 41.4 ;
    END
  END q[188]
  PIN q[189]
    DIRECTION OUTPUT ;
    USE SIGNAL ;
    PORT
      LAYER M4 ;
        RECT  0.054 41.568 0.138 41.592 ;
    END
  END q[189]
  PIN q[18]
    DIRECTION OUTPUT ;
    USE SIGNAL ;
    PORT
      LAYER M4 ;
        RECT  0.054 8.736 0.138 8.76 ;
    END
  END q[18]
  PIN q[190]
    DIRECTION OUTPUT ;
    USE SIGNAL ;
    PORT
      LAYER M4 ;
        RECT  0.054 41.76 0.138 41.784 ;
    END
  END q[190]
  PIN q[191]
    DIRECTION OUTPUT ;
    USE SIGNAL ;
    PORT
      LAYER M4 ;
        RECT  0.054 41.952 0.138 41.976 ;
    END
  END q[191]
  PIN q[192]
    DIRECTION OUTPUT ;
    USE SIGNAL ;
    PORT
      LAYER M4 ;
        RECT  0.054 42.144 0.138 42.168 ;
    END
  END q[192]
  PIN q[193]
    DIRECTION OUTPUT ;
    USE SIGNAL ;
    PORT
      LAYER M4 ;
        RECT  0.054 42.336 0.138 42.36 ;
    END
  END q[193]
  PIN q[194]
    DIRECTION OUTPUT ;
    USE SIGNAL ;
    PORT
      LAYER M4 ;
        RECT  0.054 42.528 0.138 42.552 ;
    END
  END q[194]
  PIN q[195]
    DIRECTION OUTPUT ;
    USE SIGNAL ;
    PORT
      LAYER M4 ;
        RECT  0.054 42.72 0.138 42.744 ;
    END
  END q[195]
  PIN q[196]
    DIRECTION OUTPUT ;
    USE SIGNAL ;
    PORT
      LAYER M4 ;
        RECT  0.054 42.912 0.138 42.936 ;
    END
  END q[196]
  PIN q[197]
    DIRECTION OUTPUT ;
    USE SIGNAL ;
    PORT
      LAYER M4 ;
        RECT  0.054 43.104 0.138 43.128 ;
    END
  END q[197]
  PIN q[198]
    DIRECTION OUTPUT ;
    USE SIGNAL ;
    PORT
      LAYER M4 ;
        RECT  0.054 43.296 0.138 43.32 ;
    END
  END q[198]
  PIN q[199]
    DIRECTION OUTPUT ;
    USE SIGNAL ;
    PORT
      LAYER M4 ;
        RECT  0.054 43.488 0.138 43.512 ;
    END
  END q[199]
  PIN q[19]
    DIRECTION OUTPUT ;
    USE SIGNAL ;
    PORT
      LAYER M4 ;
        RECT  0.054 8.928 0.138 8.952 ;
    END
  END q[19]
  PIN q[1]
    DIRECTION OUTPUT ;
    USE SIGNAL ;
    PORT
      LAYER M4 ;
        RECT  0.054 5.472 0.138 5.496 ;
    END
  END q[1]
  PIN q[200]
    DIRECTION OUTPUT ;
    USE SIGNAL ;
    PORT
      LAYER M4 ;
        RECT  0.054 43.68 0.138 43.704 ;
    END
  END q[200]
  PIN q[201]
    DIRECTION OUTPUT ;
    USE SIGNAL ;
    PORT
      LAYER M4 ;
        RECT  0.054 43.872 0.138 43.896 ;
    END
  END q[201]
  PIN q[202]
    DIRECTION OUTPUT ;
    USE SIGNAL ;
    PORT
      LAYER M4 ;
        RECT  0.054 44.064 0.138 44.088 ;
    END
  END q[202]
  PIN q[203]
    DIRECTION OUTPUT ;
    USE SIGNAL ;
    PORT
      LAYER M4 ;
        RECT  0.054 44.256 0.138 44.28 ;
    END
  END q[203]
  PIN q[204]
    DIRECTION OUTPUT ;
    USE SIGNAL ;
    PORT
      LAYER M4 ;
        RECT  0.054 44.448 0.138 44.472 ;
    END
  END q[204]
  PIN q[205]
    DIRECTION OUTPUT ;
    USE SIGNAL ;
    PORT
      LAYER M4 ;
        RECT  0.054 44.64 0.138 44.664 ;
    END
  END q[205]
  PIN q[206]
    DIRECTION OUTPUT ;
    USE SIGNAL ;
    PORT
      LAYER M4 ;
        RECT  0.054 44.832 0.138 44.856 ;
    END
  END q[206]
  PIN q[207]
    DIRECTION OUTPUT ;
    USE SIGNAL ;
    PORT
      LAYER M4 ;
        RECT  0.054 45.024 0.138 45.048 ;
    END
  END q[207]
  PIN q[208]
    DIRECTION OUTPUT ;
    USE SIGNAL ;
    PORT
      LAYER M4 ;
        RECT  0.054 45.216 0.138 45.24 ;
    END
  END q[208]
  PIN q[209]
    DIRECTION OUTPUT ;
    USE SIGNAL ;
    PORT
      LAYER M4 ;
        RECT  0.054 45.408 0.138 45.432 ;
    END
  END q[209]
  PIN q[20]
    DIRECTION OUTPUT ;
    USE SIGNAL ;
    PORT
      LAYER M4 ;
        RECT  0.054 9.12 0.138 9.144 ;
    END
  END q[20]
  PIN q[210]
    DIRECTION OUTPUT ;
    USE SIGNAL ;
    PORT
      LAYER M4 ;
        RECT  0.054 45.6 0.138 45.624 ;
    END
  END q[210]
  PIN q[211]
    DIRECTION OUTPUT ;
    USE SIGNAL ;
    PORT
      LAYER M4 ;
        RECT  0.054 45.792 0.138 45.816 ;
    END
  END q[211]
  PIN q[212]
    DIRECTION OUTPUT ;
    USE SIGNAL ;
    PORT
      LAYER M4 ;
        RECT  0.054 45.984 0.138 46.008 ;
    END
  END q[212]
  PIN q[213]
    DIRECTION OUTPUT ;
    USE SIGNAL ;
    PORT
      LAYER M4 ;
        RECT  0.054 46.176 0.138 46.2 ;
    END
  END q[213]
  PIN q[214]
    DIRECTION OUTPUT ;
    USE SIGNAL ;
    PORT
      LAYER M4 ;
        RECT  0.054 46.368 0.138 46.392 ;
    END
  END q[214]
  PIN q[215]
    DIRECTION OUTPUT ;
    USE SIGNAL ;
    PORT
      LAYER M4 ;
        RECT  0.054 46.56 0.138 46.584 ;
    END
  END q[215]
  PIN q[216]
    DIRECTION OUTPUT ;
    USE SIGNAL ;
    PORT
      LAYER M4 ;
        RECT  0.054 46.752 0.138 46.776 ;
    END
  END q[216]
  PIN q[217]
    DIRECTION OUTPUT ;
    USE SIGNAL ;
    PORT
      LAYER M4 ;
        RECT  0.054 46.944 0.138 46.968 ;
    END
  END q[217]
  PIN q[218]
    DIRECTION OUTPUT ;
    USE SIGNAL ;
    PORT
      LAYER M4 ;
        RECT  0.054 47.136 0.138 47.16 ;
    END
  END q[218]
  PIN q[219]
    DIRECTION OUTPUT ;
    USE SIGNAL ;
    PORT
      LAYER M4 ;
        RECT  0.054 47.328 0.138 47.352 ;
    END
  END q[219]
  PIN q[21]
    DIRECTION OUTPUT ;
    USE SIGNAL ;
    PORT
      LAYER M4 ;
        RECT  0.054 9.312 0.138 9.336 ;
    END
  END q[21]
  PIN q[220]
    DIRECTION OUTPUT ;
    USE SIGNAL ;
    PORT
      LAYER M4 ;
        RECT  0.054 47.52 0.138 47.544 ;
    END
  END q[220]
  PIN q[221]
    DIRECTION OUTPUT ;
    USE SIGNAL ;
    PORT
      LAYER M4 ;
        RECT  0.054 47.712 0.138 47.736 ;
    END
  END q[221]
  PIN q[222]
    DIRECTION OUTPUT ;
    USE SIGNAL ;
    PORT
      LAYER M4 ;
        RECT  0.054 47.904 0.138 47.928 ;
    END
  END q[222]
  PIN q[223]
    DIRECTION OUTPUT ;
    USE SIGNAL ;
    PORT
      LAYER M4 ;
        RECT  0.054 48.096 0.138 48.12 ;
    END
  END q[223]
  PIN q[224]
    DIRECTION OUTPUT ;
    USE SIGNAL ;
    PORT
      LAYER M4 ;
        RECT  0.054 48.288 0.138 48.312 ;
    END
  END q[224]
  PIN q[225]
    DIRECTION OUTPUT ;
    USE SIGNAL ;
    PORT
      LAYER M4 ;
        RECT  0.054 48.48 0.138 48.504 ;
    END
  END q[225]
  PIN q[226]
    DIRECTION OUTPUT ;
    USE SIGNAL ;
    PORT
      LAYER M4 ;
        RECT  0.054 48.672 0.138 48.696 ;
    END
  END q[226]
  PIN q[227]
    DIRECTION OUTPUT ;
    USE SIGNAL ;
    PORT
      LAYER M4 ;
        RECT  0.054 48.864 0.138 48.888 ;
    END
  END q[227]
  PIN q[228]
    DIRECTION OUTPUT ;
    USE SIGNAL ;
    PORT
      LAYER M4 ;
        RECT  0.054 49.056 0.138 49.08 ;
    END
  END q[228]
  PIN q[229]
    DIRECTION OUTPUT ;
    USE SIGNAL ;
    PORT
      LAYER M4 ;
        RECT  0.054 49.248 0.138 49.272 ;
    END
  END q[229]
  PIN q[22]
    DIRECTION OUTPUT ;
    USE SIGNAL ;
    PORT
      LAYER M4 ;
        RECT  0.054 9.504 0.138 9.528 ;
    END
  END q[22]
  PIN q[230]
    DIRECTION OUTPUT ;
    USE SIGNAL ;
    PORT
      LAYER M4 ;
        RECT  0.054 49.44 0.138 49.464 ;
    END
  END q[230]
  PIN q[231]
    DIRECTION OUTPUT ;
    USE SIGNAL ;
    PORT
      LAYER M4 ;
        RECT  0.054 49.632 0.138 49.656 ;
    END
  END q[231]
  PIN q[232]
    DIRECTION OUTPUT ;
    USE SIGNAL ;
    PORT
      LAYER M4 ;
        RECT  0.054 49.824 0.138 49.848 ;
    END
  END q[232]
  PIN q[233]
    DIRECTION OUTPUT ;
    USE SIGNAL ;
    PORT
      LAYER M4 ;
        RECT  0.054 50.016 0.138 50.04 ;
    END
  END q[233]
  PIN q[234]
    DIRECTION OUTPUT ;
    USE SIGNAL ;
    PORT
      LAYER M4 ;
        RECT  0.054 50.208 0.138 50.232 ;
    END
  END q[234]
  PIN q[235]
    DIRECTION OUTPUT ;
    USE SIGNAL ;
    PORT
      LAYER M4 ;
        RECT  0.054 50.4 0.138 50.424 ;
    END
  END q[235]
  PIN q[236]
    DIRECTION OUTPUT ;
    USE SIGNAL ;
    PORT
      LAYER M4 ;
        RECT  0.054 50.592 0.138 50.616 ;
    END
  END q[236]
  PIN q[237]
    DIRECTION OUTPUT ;
    USE SIGNAL ;
    PORT
      LAYER M4 ;
        RECT  0.054 50.784 0.138 50.808 ;
    END
  END q[237]
  PIN q[238]
    DIRECTION OUTPUT ;
    USE SIGNAL ;
    PORT
      LAYER M4 ;
        RECT  0.054 50.976 0.138 51 ;
    END
  END q[238]
  PIN q[239]
    DIRECTION OUTPUT ;
    USE SIGNAL ;
    PORT
      LAYER M4 ;
        RECT  0.054 51.168 0.138 51.192 ;
    END
  END q[239]
  PIN q[23]
    DIRECTION OUTPUT ;
    USE SIGNAL ;
    PORT
      LAYER M4 ;
        RECT  0.054 9.696 0.138 9.72 ;
    END
  END q[23]
  PIN q[240]
    DIRECTION OUTPUT ;
    USE SIGNAL ;
    PORT
      LAYER M4 ;
        RECT  0.054 51.36 0.138 51.384 ;
    END
  END q[240]
  PIN q[241]
    DIRECTION OUTPUT ;
    USE SIGNAL ;
    PORT
      LAYER M4 ;
        RECT  0.054 51.552 0.138 51.576 ;
    END
  END q[241]
  PIN q[242]
    DIRECTION OUTPUT ;
    USE SIGNAL ;
    PORT
      LAYER M4 ;
        RECT  0.054 51.744 0.138 51.768 ;
    END
  END q[242]
  PIN q[243]
    DIRECTION OUTPUT ;
    USE SIGNAL ;
    PORT
      LAYER M4 ;
        RECT  0.054 51.936 0.138 51.96 ;
    END
  END q[243]
  PIN q[244]
    DIRECTION OUTPUT ;
    USE SIGNAL ;
    PORT
      LAYER M4 ;
        RECT  0.054 52.128 0.138 52.152 ;
    END
  END q[244]
  PIN q[245]
    DIRECTION OUTPUT ;
    USE SIGNAL ;
    PORT
      LAYER M4 ;
        RECT  0.054 52.32 0.138 52.344 ;
    END
  END q[245]
  PIN q[246]
    DIRECTION OUTPUT ;
    USE SIGNAL ;
    PORT
      LAYER M4 ;
        RECT  0.054 52.512 0.138 52.536 ;
    END
  END q[246]
  PIN q[247]
    DIRECTION OUTPUT ;
    USE SIGNAL ;
    PORT
      LAYER M4 ;
        RECT  0.054 52.704 0.138 52.728 ;
    END
  END q[247]
  PIN q[248]
    DIRECTION OUTPUT ;
    USE SIGNAL ;
    PORT
      LAYER M4 ;
        RECT  0.054 52.896 0.138 52.92 ;
    END
  END q[248]
  PIN q[249]
    DIRECTION OUTPUT ;
    USE SIGNAL ;
    PORT
      LAYER M4 ;
        RECT  0.054 53.088 0.138 53.112 ;
    END
  END q[249]
  PIN q[24]
    DIRECTION OUTPUT ;
    USE SIGNAL ;
    PORT
      LAYER M4 ;
        RECT  0.054 9.888 0.138 9.912 ;
    END
  END q[24]
  PIN q[250]
    DIRECTION OUTPUT ;
    USE SIGNAL ;
    PORT
      LAYER M4 ;
        RECT  0.054 53.28 0.138 53.304 ;
    END
  END q[250]
  PIN q[251]
    DIRECTION OUTPUT ;
    USE SIGNAL ;
    PORT
      LAYER M4 ;
        RECT  0.054 53.472 0.138 53.496 ;
    END
  END q[251]
  PIN q[252]
    DIRECTION OUTPUT ;
    USE SIGNAL ;
    PORT
      LAYER M4 ;
        RECT  0.054 53.664 0.138 53.688 ;
    END
  END q[252]
  PIN q[253]
    DIRECTION OUTPUT ;
    USE SIGNAL ;
    PORT
      LAYER M4 ;
        RECT  0.054 53.856 0.138 53.88 ;
    END
  END q[253]
  PIN q[254]
    DIRECTION OUTPUT ;
    USE SIGNAL ;
    PORT
      LAYER M4 ;
        RECT  0.054 54.048 0.138 54.072 ;
    END
  END q[254]
  PIN q[255]
    DIRECTION OUTPUT ;
    USE SIGNAL ;
    PORT
      LAYER M4 ;
        RECT  0.054 54.24 0.138 54.264 ;
    END
  END q[255]
  PIN q[256]
    DIRECTION OUTPUT ;
    USE SIGNAL ;
    PORT
      LAYER M4 ;
        RECT  0.054 54.432 0.138 54.456 ;
    END
  END q[256]
  PIN q[257]
    DIRECTION OUTPUT ;
    USE SIGNAL ;
    PORT
      LAYER M4 ;
        RECT  0.054 54.624 0.138 54.648 ;
    END
  END q[257]
  PIN q[258]
    DIRECTION OUTPUT ;
    USE SIGNAL ;
    PORT
      LAYER M4 ;
        RECT  0.054 54.816 0.138 54.84 ;
    END
  END q[258]
  PIN q[259]
    DIRECTION OUTPUT ;
    USE SIGNAL ;
    PORT
      LAYER M4 ;
        RECT  0.054 55.008 0.138 55.032 ;
    END
  END q[259]
  PIN q[25]
    DIRECTION OUTPUT ;
    USE SIGNAL ;
    PORT
      LAYER M4 ;
        RECT  0.054 10.08 0.138 10.104 ;
    END
  END q[25]
  PIN q[260]
    DIRECTION OUTPUT ;
    USE SIGNAL ;
    PORT
      LAYER M4 ;
        RECT  0.054 55.2 0.138 55.224 ;
    END
  END q[260]
  PIN q[261]
    DIRECTION OUTPUT ;
    USE SIGNAL ;
    PORT
      LAYER M4 ;
        RECT  0.054 55.392 0.138 55.416 ;
    END
  END q[261]
  PIN q[262]
    DIRECTION OUTPUT ;
    USE SIGNAL ;
    PORT
      LAYER M4 ;
        RECT  0.054 55.584 0.138 55.608 ;
    END
  END q[262]
  PIN q[263]
    DIRECTION OUTPUT ;
    USE SIGNAL ;
    PORT
      LAYER M4 ;
        RECT  0.054 55.776 0.138 55.8 ;
    END
  END q[263]
  PIN q[264]
    DIRECTION OUTPUT ;
    USE SIGNAL ;
    PORT
      LAYER M4 ;
        RECT  0.054 55.968 0.138 55.992 ;
    END
  END q[264]
  PIN q[265]
    DIRECTION OUTPUT ;
    USE SIGNAL ;
    PORT
      LAYER M4 ;
        RECT  0.054 56.16 0.138 56.184 ;
    END
  END q[265]
  PIN q[266]
    DIRECTION OUTPUT ;
    USE SIGNAL ;
    PORT
      LAYER M4 ;
        RECT  0.054 56.352 0.138 56.376 ;
    END
  END q[266]
  PIN q[267]
    DIRECTION OUTPUT ;
    USE SIGNAL ;
    PORT
      LAYER M4 ;
        RECT  0.054 56.544 0.138 56.568 ;
    END
  END q[267]
  PIN q[268]
    DIRECTION OUTPUT ;
    USE SIGNAL ;
    PORT
      LAYER M4 ;
        RECT  0.054 56.736 0.138 56.76 ;
    END
  END q[268]
  PIN q[269]
    DIRECTION OUTPUT ;
    USE SIGNAL ;
    PORT
      LAYER M4 ;
        RECT  0.054 56.928 0.138 56.952 ;
    END
  END q[269]
  PIN q[26]
    DIRECTION OUTPUT ;
    USE SIGNAL ;
    PORT
      LAYER M4 ;
        RECT  0.054 10.272 0.138 10.296 ;
    END
  END q[26]
  PIN q[270]
    DIRECTION OUTPUT ;
    USE SIGNAL ;
    PORT
      LAYER M4 ;
        RECT  0.054 57.12 0.138 57.144 ;
    END
  END q[270]
  PIN q[271]
    DIRECTION OUTPUT ;
    USE SIGNAL ;
    PORT
      LAYER M4 ;
        RECT  0.054 57.312 0.138 57.336 ;
    END
  END q[271]
  PIN q[272]
    DIRECTION OUTPUT ;
    USE SIGNAL ;
    PORT
      LAYER M4 ;
        RECT  0.054 57.504 0.138 57.528 ;
    END
  END q[272]
  PIN q[273]
    DIRECTION OUTPUT ;
    USE SIGNAL ;
    PORT
      LAYER M4 ;
        RECT  0.054 57.696 0.138 57.72 ;
    END
  END q[273]
  PIN q[274]
    DIRECTION OUTPUT ;
    USE SIGNAL ;
    PORT
      LAYER M4 ;
        RECT  0.054 57.888 0.138 57.912 ;
    END
  END q[274]
  PIN q[275]
    DIRECTION OUTPUT ;
    USE SIGNAL ;
    PORT
      LAYER M4 ;
        RECT  0.054 58.08 0.138 58.104 ;
    END
  END q[275]
  PIN q[276]
    DIRECTION OUTPUT ;
    USE SIGNAL ;
    PORT
      LAYER M4 ;
        RECT  0.054 58.272 0.138 58.296 ;
    END
  END q[276]
  PIN q[277]
    DIRECTION OUTPUT ;
    USE SIGNAL ;
    PORT
      LAYER M4 ;
        RECT  0.054 58.464 0.138 58.488 ;
    END
  END q[277]
  PIN q[278]
    DIRECTION OUTPUT ;
    USE SIGNAL ;
    PORT
      LAYER M4 ;
        RECT  0.054 58.656 0.138 58.68 ;
    END
  END q[278]
  PIN q[279]
    DIRECTION OUTPUT ;
    USE SIGNAL ;
    PORT
      LAYER M4 ;
        RECT  0.054 58.848 0.138 58.872 ;
    END
  END q[279]
  PIN q[27]
    DIRECTION OUTPUT ;
    USE SIGNAL ;
    PORT
      LAYER M4 ;
        RECT  0.054 10.464 0.138 10.488 ;
    END
  END q[27]
  PIN q[280]
    DIRECTION OUTPUT ;
    USE SIGNAL ;
    PORT
      LAYER M4 ;
        RECT  0.054 59.04 0.138 59.064 ;
    END
  END q[280]
  PIN q[281]
    DIRECTION OUTPUT ;
    USE SIGNAL ;
    PORT
      LAYER M4 ;
        RECT  0.054 59.232 0.138 59.256 ;
    END
  END q[281]
  PIN q[282]
    DIRECTION OUTPUT ;
    USE SIGNAL ;
    PORT
      LAYER M4 ;
        RECT  0.054 59.424 0.138 59.448 ;
    END
  END q[282]
  PIN q[283]
    DIRECTION OUTPUT ;
    USE SIGNAL ;
    PORT
      LAYER M4 ;
        RECT  0.054 59.616 0.138 59.64 ;
    END
  END q[283]
  PIN q[284]
    DIRECTION OUTPUT ;
    USE SIGNAL ;
    PORT
      LAYER M4 ;
        RECT  0.054 59.808 0.138 59.832 ;
    END
  END q[284]
  PIN q[285]
    DIRECTION OUTPUT ;
    USE SIGNAL ;
    PORT
      LAYER M4 ;
        RECT  0.054 60 0.138 60.024 ;
    END
  END q[285]
  PIN q[286]
    DIRECTION OUTPUT ;
    USE SIGNAL ;
    PORT
      LAYER M4 ;
        RECT  0.054 60.192 0.138 60.216 ;
    END
  END q[286]
  PIN q[287]
    DIRECTION OUTPUT ;
    USE SIGNAL ;
    PORT
      LAYER M4 ;
        RECT  0.054 60.384 0.138 60.408 ;
    END
  END q[287]
  PIN q[288]
    DIRECTION OUTPUT ;
    USE SIGNAL ;
    PORT
      LAYER M4 ;
        RECT  0.054 60.576 0.138 60.6 ;
    END
  END q[288]
  PIN q[289]
    DIRECTION OUTPUT ;
    USE SIGNAL ;
    PORT
      LAYER M4 ;
        RECT  0.054 60.768 0.138 60.792 ;
    END
  END q[289]
  PIN q[28]
    DIRECTION OUTPUT ;
    USE SIGNAL ;
    PORT
      LAYER M4 ;
        RECT  0.054 10.656 0.138 10.68 ;
    END
  END q[28]
  PIN q[290]
    DIRECTION OUTPUT ;
    USE SIGNAL ;
    PORT
      LAYER M4 ;
        RECT  0.054 60.96 0.138 60.984 ;
    END
  END q[290]
  PIN q[291]
    DIRECTION OUTPUT ;
    USE SIGNAL ;
    PORT
      LAYER M4 ;
        RECT  0.054 61.152 0.138 61.176 ;
    END
  END q[291]
  PIN q[292]
    DIRECTION OUTPUT ;
    USE SIGNAL ;
    PORT
      LAYER M4 ;
        RECT  0.054 61.344 0.138 61.368 ;
    END
  END q[292]
  PIN q[293]
    DIRECTION OUTPUT ;
    USE SIGNAL ;
    PORT
      LAYER M4 ;
        RECT  0.054 61.536 0.138 61.56 ;
    END
  END q[293]
  PIN q[294]
    DIRECTION OUTPUT ;
    USE SIGNAL ;
    PORT
      LAYER M4 ;
        RECT  0.054 61.728 0.138 61.752 ;
    END
  END q[294]
  PIN q[295]
    DIRECTION OUTPUT ;
    USE SIGNAL ;
    PORT
      LAYER M4 ;
        RECT  0.054 61.92 0.138 61.944 ;
    END
  END q[295]
  PIN q[296]
    DIRECTION OUTPUT ;
    USE SIGNAL ;
    PORT
      LAYER M4 ;
        RECT  0.054 62.112 0.138 62.136 ;
    END
  END q[296]
  PIN q[297]
    DIRECTION OUTPUT ;
    USE SIGNAL ;
    PORT
      LAYER M4 ;
        RECT  0.054 62.304 0.138 62.328 ;
    END
  END q[297]
  PIN q[298]
    DIRECTION OUTPUT ;
    USE SIGNAL ;
    PORT
      LAYER M4 ;
        RECT  0.054 62.496 0.138 62.52 ;
    END
  END q[298]
  PIN q[299]
    DIRECTION OUTPUT ;
    USE SIGNAL ;
    PORT
      LAYER M4 ;
        RECT  0.054 62.688 0.138 62.712 ;
    END
  END q[299]
  PIN q[29]
    DIRECTION OUTPUT ;
    USE SIGNAL ;
    PORT
      LAYER M4 ;
        RECT  0.054 10.848 0.138 10.872 ;
    END
  END q[29]
  PIN q[2]
    DIRECTION OUTPUT ;
    USE SIGNAL ;
    PORT
      LAYER M4 ;
        RECT  0.054 5.664 0.138 5.688 ;
    END
  END q[2]
  PIN q[300]
    DIRECTION OUTPUT ;
    USE SIGNAL ;
    PORT
      LAYER M4 ;
        RECT  0.054 62.88 0.138 62.904 ;
    END
  END q[300]
  PIN q[301]
    DIRECTION OUTPUT ;
    USE SIGNAL ;
    PORT
      LAYER M4 ;
        RECT  0.054 63.072 0.138 63.096 ;
    END
  END q[301]
  PIN q[302]
    DIRECTION OUTPUT ;
    USE SIGNAL ;
    PORT
      LAYER M4 ;
        RECT  0.054 63.264 0.138 63.288 ;
    END
  END q[302]
  PIN q[303]
    DIRECTION OUTPUT ;
    USE SIGNAL ;
    PORT
      LAYER M4 ;
        RECT  0.054 63.456 0.138 63.48 ;
    END
  END q[303]
  PIN q[304]
    DIRECTION OUTPUT ;
    USE SIGNAL ;
    PORT
      LAYER M4 ;
        RECT  0.054 63.648 0.138 63.672 ;
    END
  END q[304]
  PIN q[305]
    DIRECTION OUTPUT ;
    USE SIGNAL ;
    PORT
      LAYER M4 ;
        RECT  0.054 63.84 0.138 63.864 ;
    END
  END q[305]
  PIN q[306]
    DIRECTION OUTPUT ;
    USE SIGNAL ;
    PORT
      LAYER M4 ;
        RECT  0.054 64.032 0.138 64.056 ;
    END
  END q[306]
  PIN q[307]
    DIRECTION OUTPUT ;
    USE SIGNAL ;
    PORT
      LAYER M4 ;
        RECT  0.054 64.224 0.138 64.248 ;
    END
  END q[307]
  PIN q[308]
    DIRECTION OUTPUT ;
    USE SIGNAL ;
    PORT
      LAYER M4 ;
        RECT  0.054 64.416 0.138 64.44 ;
    END
  END q[308]
  PIN q[309]
    DIRECTION OUTPUT ;
    USE SIGNAL ;
    PORT
      LAYER M4 ;
        RECT  0.054 64.608 0.138 64.632 ;
    END
  END q[309]
  PIN q[30]
    DIRECTION OUTPUT ;
    USE SIGNAL ;
    PORT
      LAYER M4 ;
        RECT  0.054 11.04 0.138 11.064 ;
    END
  END q[30]
  PIN q[310]
    DIRECTION OUTPUT ;
    USE SIGNAL ;
    PORT
      LAYER M4 ;
        RECT  0.054 64.8 0.138 64.824 ;
    END
  END q[310]
  PIN q[311]
    DIRECTION OUTPUT ;
    USE SIGNAL ;
    PORT
      LAYER M4 ;
        RECT  0.054 64.992 0.138 65.016 ;
    END
  END q[311]
  PIN q[312]
    DIRECTION OUTPUT ;
    USE SIGNAL ;
    PORT
      LAYER M4 ;
        RECT  0.054 65.184 0.138 65.208 ;
    END
  END q[312]
  PIN q[313]
    DIRECTION OUTPUT ;
    USE SIGNAL ;
    PORT
      LAYER M4 ;
        RECT  0.054 65.376 0.138 65.4 ;
    END
  END q[313]
  PIN q[314]
    DIRECTION OUTPUT ;
    USE SIGNAL ;
    PORT
      LAYER M4 ;
        RECT  0.054 65.568 0.138 65.592 ;
    END
  END q[314]
  PIN q[315]
    DIRECTION OUTPUT ;
    USE SIGNAL ;
    PORT
      LAYER M4 ;
        RECT  0.054 65.76 0.138 65.784 ;
    END
  END q[315]
  PIN q[316]
    DIRECTION OUTPUT ;
    USE SIGNAL ;
    PORT
      LAYER M4 ;
        RECT  0.054 65.952 0.138 65.976 ;
    END
  END q[316]
  PIN q[317]
    DIRECTION OUTPUT ;
    USE SIGNAL ;
    PORT
      LAYER M4 ;
        RECT  0.054 66.144 0.138 66.168 ;
    END
  END q[317]
  PIN q[318]
    DIRECTION OUTPUT ;
    USE SIGNAL ;
    PORT
      LAYER M4 ;
        RECT  0.054 66.336 0.138 66.36 ;
    END
  END q[318]
  PIN q[319]
    DIRECTION OUTPUT ;
    USE SIGNAL ;
    PORT
      LAYER M4 ;
        RECT  0.054 66.528 0.138 66.552 ;
    END
  END q[319]
  PIN q[31]
    DIRECTION OUTPUT ;
    USE SIGNAL ;
    PORT
      LAYER M4 ;
        RECT  0.054 11.232 0.138 11.256 ;
    END
  END q[31]
  PIN q[320]
    DIRECTION OUTPUT ;
    USE SIGNAL ;
    PORT
      LAYER M4 ;
        RECT  0.054 66.72 0.138 66.744 ;
    END
  END q[320]
  PIN q[321]
    DIRECTION OUTPUT ;
    USE SIGNAL ;
    PORT
      LAYER M4 ;
        RECT  0.054 66.912 0.138 66.936 ;
    END
  END q[321]
  PIN q[322]
    DIRECTION OUTPUT ;
    USE SIGNAL ;
    PORT
      LAYER M4 ;
        RECT  0.054 67.104 0.138 67.128 ;
    END
  END q[322]
  PIN q[323]
    DIRECTION OUTPUT ;
    USE SIGNAL ;
    PORT
      LAYER M4 ;
        RECT  0.054 67.296 0.138 67.32 ;
    END
  END q[323]
  PIN q[324]
    DIRECTION OUTPUT ;
    USE SIGNAL ;
    PORT
      LAYER M4 ;
        RECT  0.054 67.488 0.138 67.512 ;
    END
  END q[324]
  PIN q[325]
    DIRECTION OUTPUT ;
    USE SIGNAL ;
    PORT
      LAYER M4 ;
        RECT  0.054 67.68 0.138 67.704 ;
    END
  END q[325]
  PIN q[326]
    DIRECTION OUTPUT ;
    USE SIGNAL ;
    PORT
      LAYER M4 ;
        RECT  0.054 67.872 0.138 67.896 ;
    END
  END q[326]
  PIN q[327]
    DIRECTION OUTPUT ;
    USE SIGNAL ;
    PORT
      LAYER M4 ;
        RECT  0.054 68.064 0.138 68.088 ;
    END
  END q[327]
  PIN q[328]
    DIRECTION OUTPUT ;
    USE SIGNAL ;
    PORT
      LAYER M4 ;
        RECT  0.054 68.256 0.138 68.28 ;
    END
  END q[328]
  PIN q[329]
    DIRECTION OUTPUT ;
    USE SIGNAL ;
    PORT
      LAYER M4 ;
        RECT  0.054 68.448 0.138 68.472 ;
    END
  END q[329]
  PIN q[32]
    DIRECTION OUTPUT ;
    USE SIGNAL ;
    PORT
      LAYER M4 ;
        RECT  0.054 11.424 0.138 11.448 ;
    END
  END q[32]
  PIN q[330]
    DIRECTION OUTPUT ;
    USE SIGNAL ;
    PORT
      LAYER M4 ;
        RECT  0.054 68.64 0.138 68.664 ;
    END
  END q[330]
  PIN q[331]
    DIRECTION OUTPUT ;
    USE SIGNAL ;
    PORT
      LAYER M4 ;
        RECT  0.054 68.832 0.138 68.856 ;
    END
  END q[331]
  PIN q[332]
    DIRECTION OUTPUT ;
    USE SIGNAL ;
    PORT
      LAYER M4 ;
        RECT  0.054 69.024 0.138 69.048 ;
    END
  END q[332]
  PIN q[333]
    DIRECTION OUTPUT ;
    USE SIGNAL ;
    PORT
      LAYER M4 ;
        RECT  0.054 69.216 0.138 69.24 ;
    END
  END q[333]
  PIN q[334]
    DIRECTION OUTPUT ;
    USE SIGNAL ;
    PORT
      LAYER M4 ;
        RECT  0.054 69.408 0.138 69.432 ;
    END
  END q[334]
  PIN q[335]
    DIRECTION OUTPUT ;
    USE SIGNAL ;
    PORT
      LAYER M4 ;
        RECT  0.054 69.6 0.138 69.624 ;
    END
  END q[335]
  PIN q[336]
    DIRECTION OUTPUT ;
    USE SIGNAL ;
    PORT
      LAYER M4 ;
        RECT  0.054 69.792 0.138 69.816 ;
    END
  END q[336]
  PIN q[337]
    DIRECTION OUTPUT ;
    USE SIGNAL ;
    PORT
      LAYER M4 ;
        RECT  0.054 69.984 0.138 70.008 ;
    END
  END q[337]
  PIN q[338]
    DIRECTION OUTPUT ;
    USE SIGNAL ;
    PORT
      LAYER M4 ;
        RECT  0.054 70.176 0.138 70.2 ;
    END
  END q[338]
  PIN q[339]
    DIRECTION OUTPUT ;
    USE SIGNAL ;
    PORT
      LAYER M4 ;
        RECT  0.054 70.368 0.138 70.392 ;
    END
  END q[339]
  PIN q[33]
    DIRECTION OUTPUT ;
    USE SIGNAL ;
    PORT
      LAYER M4 ;
        RECT  0.054 11.616 0.138 11.64 ;
    END
  END q[33]
  PIN q[340]
    DIRECTION OUTPUT ;
    USE SIGNAL ;
    PORT
      LAYER M4 ;
        RECT  0.054 70.56 0.138 70.584 ;
    END
  END q[340]
  PIN q[341]
    DIRECTION OUTPUT ;
    USE SIGNAL ;
    PORT
      LAYER M4 ;
        RECT  0.054 70.752 0.138 70.776 ;
    END
  END q[341]
  PIN q[342]
    DIRECTION OUTPUT ;
    USE SIGNAL ;
    PORT
      LAYER M4 ;
        RECT  0.054 70.944 0.138 70.968 ;
    END
  END q[342]
  PIN q[343]
    DIRECTION OUTPUT ;
    USE SIGNAL ;
    PORT
      LAYER M4 ;
        RECT  0.054 71.136 0.138 71.16 ;
    END
  END q[343]
  PIN q[344]
    DIRECTION OUTPUT ;
    USE SIGNAL ;
    PORT
      LAYER M4 ;
        RECT  0.054 71.328 0.138 71.352 ;
    END
  END q[344]
  PIN q[345]
    DIRECTION OUTPUT ;
    USE SIGNAL ;
    PORT
      LAYER M4 ;
        RECT  0.054 71.52 0.138 71.544 ;
    END
  END q[345]
  PIN q[346]
    DIRECTION OUTPUT ;
    USE SIGNAL ;
    PORT
      LAYER M4 ;
        RECT  0.054 71.712 0.138 71.736 ;
    END
  END q[346]
  PIN q[347]
    DIRECTION OUTPUT ;
    USE SIGNAL ;
    PORT
      LAYER M4 ;
        RECT  0.054 71.904 0.138 71.928 ;
    END
  END q[347]
  PIN q[348]
    DIRECTION OUTPUT ;
    USE SIGNAL ;
    PORT
      LAYER M4 ;
        RECT  0.054 72.096 0.138 72.12 ;
    END
  END q[348]
  PIN q[349]
    DIRECTION OUTPUT ;
    USE SIGNAL ;
    PORT
      LAYER M4 ;
        RECT  0.054 72.288 0.138 72.312 ;
    END
  END q[349]
  PIN q[34]
    DIRECTION OUTPUT ;
    USE SIGNAL ;
    PORT
      LAYER M4 ;
        RECT  0.054 11.808 0.138 11.832 ;
    END
  END q[34]
  PIN q[350]
    DIRECTION OUTPUT ;
    USE SIGNAL ;
    PORT
      LAYER M4 ;
        RECT  0.054 72.48 0.138 72.504 ;
    END
  END q[350]
  PIN q[351]
    DIRECTION OUTPUT ;
    USE SIGNAL ;
    PORT
      LAYER M4 ;
        RECT  0.054 72.672 0.138 72.696 ;
    END
  END q[351]
  PIN q[352]
    DIRECTION OUTPUT ;
    USE SIGNAL ;
    PORT
      LAYER M4 ;
        RECT  0.054 72.864 0.138 72.888 ;
    END
  END q[352]
  PIN q[353]
    DIRECTION OUTPUT ;
    USE SIGNAL ;
    PORT
      LAYER M4 ;
        RECT  0.054 73.056 0.138 73.08 ;
    END
  END q[353]
  PIN q[354]
    DIRECTION OUTPUT ;
    USE SIGNAL ;
    PORT
      LAYER M4 ;
        RECT  0.054 73.248 0.138 73.272 ;
    END
  END q[354]
  PIN q[355]
    DIRECTION OUTPUT ;
    USE SIGNAL ;
    PORT
      LAYER M4 ;
        RECT  0.054 73.44 0.138 73.464 ;
    END
  END q[355]
  PIN q[356]
    DIRECTION OUTPUT ;
    USE SIGNAL ;
    PORT
      LAYER M4 ;
        RECT  0.054 73.632 0.138 73.656 ;
    END
  END q[356]
  PIN q[357]
    DIRECTION OUTPUT ;
    USE SIGNAL ;
    PORT
      LAYER M4 ;
        RECT  0.054 73.824 0.138 73.848 ;
    END
  END q[357]
  PIN q[358]
    DIRECTION OUTPUT ;
    USE SIGNAL ;
    PORT
      LAYER M4 ;
        RECT  0.054 74.016 0.138 74.04 ;
    END
  END q[358]
  PIN q[359]
    DIRECTION OUTPUT ;
    USE SIGNAL ;
    PORT
      LAYER M4 ;
        RECT  0.054 74.208 0.138 74.232 ;
    END
  END q[359]
  PIN q[35]
    DIRECTION OUTPUT ;
    USE SIGNAL ;
    PORT
      LAYER M4 ;
        RECT  0.054 12 0.138 12.024 ;
    END
  END q[35]
  PIN q[360]
    DIRECTION OUTPUT ;
    USE SIGNAL ;
    PORT
      LAYER M4 ;
        RECT  0.054 74.4 0.138 74.424 ;
    END
  END q[360]
  PIN q[361]
    DIRECTION OUTPUT ;
    USE SIGNAL ;
    PORT
      LAYER M4 ;
        RECT  0.054 74.592 0.138 74.616 ;
    END
  END q[361]
  PIN q[362]
    DIRECTION OUTPUT ;
    USE SIGNAL ;
    PORT
      LAYER M4 ;
        RECT  0.054 74.784 0.138 74.808 ;
    END
  END q[362]
  PIN q[363]
    DIRECTION OUTPUT ;
    USE SIGNAL ;
    PORT
      LAYER M4 ;
        RECT  0.054 74.976 0.138 75 ;
    END
  END q[363]
  PIN q[364]
    DIRECTION OUTPUT ;
    USE SIGNAL ;
    PORT
      LAYER M4 ;
        RECT  0.054 75.168 0.138 75.192 ;
    END
  END q[364]
  PIN q[365]
    DIRECTION OUTPUT ;
    USE SIGNAL ;
    PORT
      LAYER M4 ;
        RECT  0.054 75.36 0.138 75.384 ;
    END
  END q[365]
  PIN q[366]
    DIRECTION OUTPUT ;
    USE SIGNAL ;
    PORT
      LAYER M4 ;
        RECT  0.054 75.552 0.138 75.576 ;
    END
  END q[366]
  PIN q[367]
    DIRECTION OUTPUT ;
    USE SIGNAL ;
    PORT
      LAYER M4 ;
        RECT  0.054 75.744 0.138 75.768 ;
    END
  END q[367]
  PIN q[368]
    DIRECTION OUTPUT ;
    USE SIGNAL ;
    PORT
      LAYER M4 ;
        RECT  0.054 75.936 0.138 75.96 ;
    END
  END q[368]
  PIN q[369]
    DIRECTION OUTPUT ;
    USE SIGNAL ;
    PORT
      LAYER M4 ;
        RECT  0.054 76.128 0.138 76.152 ;
    END
  END q[369]
  PIN q[36]
    DIRECTION OUTPUT ;
    USE SIGNAL ;
    PORT
      LAYER M4 ;
        RECT  0.054 12.192 0.138 12.216 ;
    END
  END q[36]
  PIN q[370]
    DIRECTION OUTPUT ;
    USE SIGNAL ;
    PORT
      LAYER M4 ;
        RECT  0.054 76.32 0.138 76.344 ;
    END
  END q[370]
  PIN q[371]
    DIRECTION OUTPUT ;
    USE SIGNAL ;
    PORT
      LAYER M4 ;
        RECT  0.054 76.512 0.138 76.536 ;
    END
  END q[371]
  PIN q[372]
    DIRECTION OUTPUT ;
    USE SIGNAL ;
    PORT
      LAYER M4 ;
        RECT  0.054 76.704 0.138 76.728 ;
    END
  END q[372]
  PIN q[373]
    DIRECTION OUTPUT ;
    USE SIGNAL ;
    PORT
      LAYER M4 ;
        RECT  0.054 76.896 0.138 76.92 ;
    END
  END q[373]
  PIN q[374]
    DIRECTION OUTPUT ;
    USE SIGNAL ;
    PORT
      LAYER M4 ;
        RECT  0.054 77.088 0.138 77.112 ;
    END
  END q[374]
  PIN q[375]
    DIRECTION OUTPUT ;
    USE SIGNAL ;
    PORT
      LAYER M4 ;
        RECT  0.054 77.28 0.138 77.304 ;
    END
  END q[375]
  PIN q[376]
    DIRECTION OUTPUT ;
    USE SIGNAL ;
    PORT
      LAYER M4 ;
        RECT  0.054 77.472 0.138 77.496 ;
    END
  END q[376]
  PIN q[377]
    DIRECTION OUTPUT ;
    USE SIGNAL ;
    PORT
      LAYER M4 ;
        RECT  0.054 77.664 0.138 77.688 ;
    END
  END q[377]
  PIN q[378]
    DIRECTION OUTPUT ;
    USE SIGNAL ;
    PORT
      LAYER M4 ;
        RECT  0.054 77.856 0.138 77.88 ;
    END
  END q[378]
  PIN q[379]
    DIRECTION OUTPUT ;
    USE SIGNAL ;
    PORT
      LAYER M4 ;
        RECT  0.054 78.048 0.138 78.072 ;
    END
  END q[379]
  PIN q[37]
    DIRECTION OUTPUT ;
    USE SIGNAL ;
    PORT
      LAYER M4 ;
        RECT  0.054 12.384 0.138 12.408 ;
    END
  END q[37]
  PIN q[380]
    DIRECTION OUTPUT ;
    USE SIGNAL ;
    PORT
      LAYER M4 ;
        RECT  0.054 78.24 0.138 78.264 ;
    END
  END q[380]
  PIN q[381]
    DIRECTION OUTPUT ;
    USE SIGNAL ;
    PORT
      LAYER M4 ;
        RECT  0.054 78.432 0.138 78.456 ;
    END
  END q[381]
  PIN q[382]
    DIRECTION OUTPUT ;
    USE SIGNAL ;
    PORT
      LAYER M4 ;
        RECT  0.054 78.624 0.138 78.648 ;
    END
  END q[382]
  PIN q[383]
    DIRECTION OUTPUT ;
    USE SIGNAL ;
    PORT
      LAYER M4 ;
        RECT  0.054 78.816 0.138 78.84 ;
    END
  END q[383]
  PIN q[384]
    DIRECTION OUTPUT ;
    USE SIGNAL ;
    PORT
      LAYER M4 ;
        RECT  0.054 79.008 0.138 79.032 ;
    END
  END q[384]
  PIN q[385]
    DIRECTION OUTPUT ;
    USE SIGNAL ;
    PORT
      LAYER M4 ;
        RECT  0.054 79.2 0.138 79.224 ;
    END
  END q[385]
  PIN q[386]
    DIRECTION OUTPUT ;
    USE SIGNAL ;
    PORT
      LAYER M4 ;
        RECT  0.054 79.392 0.138 79.416 ;
    END
  END q[386]
  PIN q[387]
    DIRECTION OUTPUT ;
    USE SIGNAL ;
    PORT
      LAYER M4 ;
        RECT  0.054 79.584 0.138 79.608 ;
    END
  END q[387]
  PIN q[388]
    DIRECTION OUTPUT ;
    USE SIGNAL ;
    PORT
      LAYER M4 ;
        RECT  0.054 79.776 0.138 79.8 ;
    END
  END q[388]
  PIN q[389]
    DIRECTION OUTPUT ;
    USE SIGNAL ;
    PORT
      LAYER M4 ;
        RECT  0.054 79.968 0.138 79.992 ;
    END
  END q[389]
  PIN q[38]
    DIRECTION OUTPUT ;
    USE SIGNAL ;
    PORT
      LAYER M4 ;
        RECT  0.054 12.576 0.138 12.6 ;
    END
  END q[38]
  PIN q[390]
    DIRECTION OUTPUT ;
    USE SIGNAL ;
    PORT
      LAYER M4 ;
        RECT  0.054 80.16 0.138 80.184 ;
    END
  END q[390]
  PIN q[391]
    DIRECTION OUTPUT ;
    USE SIGNAL ;
    PORT
      LAYER M4 ;
        RECT  0.054 80.352 0.138 80.376 ;
    END
  END q[391]
  PIN q[392]
    DIRECTION OUTPUT ;
    USE SIGNAL ;
    PORT
      LAYER M4 ;
        RECT  0.054 80.544 0.138 80.568 ;
    END
  END q[392]
  PIN q[393]
    DIRECTION OUTPUT ;
    USE SIGNAL ;
    PORT
      LAYER M4 ;
        RECT  0.054 80.736 0.138 80.76 ;
    END
  END q[393]
  PIN q[394]
    DIRECTION OUTPUT ;
    USE SIGNAL ;
    PORT
      LAYER M4 ;
        RECT  0.054 80.928 0.138 80.952 ;
    END
  END q[394]
  PIN q[395]
    DIRECTION OUTPUT ;
    USE SIGNAL ;
    PORT
      LAYER M4 ;
        RECT  0.054 81.12 0.138 81.144 ;
    END
  END q[395]
  PIN q[396]
    DIRECTION OUTPUT ;
    USE SIGNAL ;
    PORT
      LAYER M4 ;
        RECT  0.054 81.312 0.138 81.336 ;
    END
  END q[396]
  PIN q[397]
    DIRECTION OUTPUT ;
    USE SIGNAL ;
    PORT
      LAYER M4 ;
        RECT  0.054 81.504 0.138 81.528 ;
    END
  END q[397]
  PIN q[398]
    DIRECTION OUTPUT ;
    USE SIGNAL ;
    PORT
      LAYER M4 ;
        RECT  0.054 81.696 0.138 81.72 ;
    END
  END q[398]
  PIN q[399]
    DIRECTION OUTPUT ;
    USE SIGNAL ;
    PORT
      LAYER M4 ;
        RECT  0.054 81.888 0.138 81.912 ;
    END
  END q[399]
  PIN q[39]
    DIRECTION OUTPUT ;
    USE SIGNAL ;
    PORT
      LAYER M4 ;
        RECT  0.054 12.768 0.138 12.792 ;
    END
  END q[39]
  PIN q[3]
    DIRECTION OUTPUT ;
    USE SIGNAL ;
    PORT
      LAYER M4 ;
        RECT  0.054 5.856 0.138 5.88 ;
    END
  END q[3]
  PIN q[400]
    DIRECTION OUTPUT ;
    USE SIGNAL ;
    PORT
      LAYER M4 ;
        RECT  0.054 82.08 0.138 82.104 ;
    END
  END q[400]
  PIN q[401]
    DIRECTION OUTPUT ;
    USE SIGNAL ;
    PORT
      LAYER M4 ;
        RECT  0.054 82.272 0.138 82.296 ;
    END
  END q[401]
  PIN q[402]
    DIRECTION OUTPUT ;
    USE SIGNAL ;
    PORT
      LAYER M4 ;
        RECT  0.054 82.464 0.138 82.488 ;
    END
  END q[402]
  PIN q[403]
    DIRECTION OUTPUT ;
    USE SIGNAL ;
    PORT
      LAYER M4 ;
        RECT  0.054 82.656 0.138 82.68 ;
    END
  END q[403]
  PIN q[404]
    DIRECTION OUTPUT ;
    USE SIGNAL ;
    PORT
      LAYER M4 ;
        RECT  0.054 82.848 0.138 82.872 ;
    END
  END q[404]
  PIN q[405]
    DIRECTION OUTPUT ;
    USE SIGNAL ;
    PORT
      LAYER M4 ;
        RECT  0.054 83.04 0.138 83.064 ;
    END
  END q[405]
  PIN q[406]
    DIRECTION OUTPUT ;
    USE SIGNAL ;
    PORT
      LAYER M4 ;
        RECT  0.054 83.232 0.138 83.256 ;
    END
  END q[406]
  PIN q[407]
    DIRECTION OUTPUT ;
    USE SIGNAL ;
    PORT
      LAYER M4 ;
        RECT  0.054 83.424 0.138 83.448 ;
    END
  END q[407]
  PIN q[408]
    DIRECTION OUTPUT ;
    USE SIGNAL ;
    PORT
      LAYER M4 ;
        RECT  0.054 83.616 0.138 83.64 ;
    END
  END q[408]
  PIN q[409]
    DIRECTION OUTPUT ;
    USE SIGNAL ;
    PORT
      LAYER M4 ;
        RECT  0.054 83.808 0.138 83.832 ;
    END
  END q[409]
  PIN q[40]
    DIRECTION OUTPUT ;
    USE SIGNAL ;
    PORT
      LAYER M4 ;
        RECT  0.054 12.96 0.138 12.984 ;
    END
  END q[40]
  PIN q[410]
    DIRECTION OUTPUT ;
    USE SIGNAL ;
    PORT
      LAYER M4 ;
        RECT  0.054 84 0.138 84.024 ;
    END
  END q[410]
  PIN q[411]
    DIRECTION OUTPUT ;
    USE SIGNAL ;
    PORT
      LAYER M4 ;
        RECT  0.054 84.192 0.138 84.216 ;
    END
  END q[411]
  PIN q[412]
    DIRECTION OUTPUT ;
    USE SIGNAL ;
    PORT
      LAYER M4 ;
        RECT  0.054 84.384 0.138 84.408 ;
    END
  END q[412]
  PIN q[413]
    DIRECTION OUTPUT ;
    USE SIGNAL ;
    PORT
      LAYER M4 ;
        RECT  0.054 84.576 0.138 84.6 ;
    END
  END q[413]
  PIN q[414]
    DIRECTION OUTPUT ;
    USE SIGNAL ;
    PORT
      LAYER M4 ;
        RECT  0.054 84.768 0.138 84.792 ;
    END
  END q[414]
  PIN q[415]
    DIRECTION OUTPUT ;
    USE SIGNAL ;
    PORT
      LAYER M4 ;
        RECT  0.054 84.96 0.138 84.984 ;
    END
  END q[415]
  PIN q[416]
    DIRECTION OUTPUT ;
    USE SIGNAL ;
    PORT
      LAYER M4 ;
        RECT  0.054 85.152 0.138 85.176 ;
    END
  END q[416]
  PIN q[417]
    DIRECTION OUTPUT ;
    USE SIGNAL ;
    PORT
      LAYER M4 ;
        RECT  0.054 85.344 0.138 85.368 ;
    END
  END q[417]
  PIN q[418]
    DIRECTION OUTPUT ;
    USE SIGNAL ;
    PORT
      LAYER M4 ;
        RECT  0.054 85.536 0.138 85.56 ;
    END
  END q[418]
  PIN q[419]
    DIRECTION OUTPUT ;
    USE SIGNAL ;
    PORT
      LAYER M4 ;
        RECT  0.054 85.728 0.138 85.752 ;
    END
  END q[419]
  PIN q[41]
    DIRECTION OUTPUT ;
    USE SIGNAL ;
    PORT
      LAYER M4 ;
        RECT  0.054 13.152 0.138 13.176 ;
    END
  END q[41]
  PIN q[420]
    DIRECTION OUTPUT ;
    USE SIGNAL ;
    PORT
      LAYER M4 ;
        RECT  0.054 85.92 0.138 85.944 ;
    END
  END q[420]
  PIN q[421]
    DIRECTION OUTPUT ;
    USE SIGNAL ;
    PORT
      LAYER M4 ;
        RECT  0.054 86.112 0.138 86.136 ;
    END
  END q[421]
  PIN q[422]
    DIRECTION OUTPUT ;
    USE SIGNAL ;
    PORT
      LAYER M4 ;
        RECT  0.054 86.304 0.138 86.328 ;
    END
  END q[422]
  PIN q[423]
    DIRECTION OUTPUT ;
    USE SIGNAL ;
    PORT
      LAYER M4 ;
        RECT  0.054 86.496 0.138 86.52 ;
    END
  END q[423]
  PIN q[424]
    DIRECTION OUTPUT ;
    USE SIGNAL ;
    PORT
      LAYER M4 ;
        RECT  0.054 86.688 0.138 86.712 ;
    END
  END q[424]
  PIN q[425]
    DIRECTION OUTPUT ;
    USE SIGNAL ;
    PORT
      LAYER M4 ;
        RECT  0.054 86.88 0.138 86.904 ;
    END
  END q[425]
  PIN q[426]
    DIRECTION OUTPUT ;
    USE SIGNAL ;
    PORT
      LAYER M4 ;
        RECT  0.054 87.072 0.138 87.096 ;
    END
  END q[426]
  PIN q[427]
    DIRECTION OUTPUT ;
    USE SIGNAL ;
    PORT
      LAYER M4 ;
        RECT  0.054 87.264 0.138 87.288 ;
    END
  END q[427]
  PIN q[428]
    DIRECTION OUTPUT ;
    USE SIGNAL ;
    PORT
      LAYER M4 ;
        RECT  0.054 87.456 0.138 87.48 ;
    END
  END q[428]
  PIN q[429]
    DIRECTION OUTPUT ;
    USE SIGNAL ;
    PORT
      LAYER M4 ;
        RECT  0.054 87.648 0.138 87.672 ;
    END
  END q[429]
  PIN q[42]
    DIRECTION OUTPUT ;
    USE SIGNAL ;
    PORT
      LAYER M4 ;
        RECT  0.054 13.344 0.138 13.368 ;
    END
  END q[42]
  PIN q[430]
    DIRECTION OUTPUT ;
    USE SIGNAL ;
    PORT
      LAYER M4 ;
        RECT  0.054 87.84 0.138 87.864 ;
    END
  END q[430]
  PIN q[431]
    DIRECTION OUTPUT ;
    USE SIGNAL ;
    PORT
      LAYER M4 ;
        RECT  0.054 88.032 0.138 88.056 ;
    END
  END q[431]
  PIN q[432]
    DIRECTION OUTPUT ;
    USE SIGNAL ;
    PORT
      LAYER M4 ;
        RECT  0.054 88.224 0.138 88.248 ;
    END
  END q[432]
  PIN q[433]
    DIRECTION OUTPUT ;
    USE SIGNAL ;
    PORT
      LAYER M4 ;
        RECT  0.054 88.416 0.138 88.44 ;
    END
  END q[433]
  PIN q[434]
    DIRECTION OUTPUT ;
    USE SIGNAL ;
    PORT
      LAYER M4 ;
        RECT  0.054 88.608 0.138 88.632 ;
    END
  END q[434]
  PIN q[435]
    DIRECTION OUTPUT ;
    USE SIGNAL ;
    PORT
      LAYER M4 ;
        RECT  0.054 88.8 0.138 88.824 ;
    END
  END q[435]
  PIN q[436]
    DIRECTION OUTPUT ;
    USE SIGNAL ;
    PORT
      LAYER M4 ;
        RECT  0.054 88.992 0.138 89.016 ;
    END
  END q[436]
  PIN q[437]
    DIRECTION OUTPUT ;
    USE SIGNAL ;
    PORT
      LAYER M4 ;
        RECT  0.054 89.184 0.138 89.208 ;
    END
  END q[437]
  PIN q[438]
    DIRECTION OUTPUT ;
    USE SIGNAL ;
    PORT
      LAYER M4 ;
        RECT  0.054 89.376 0.138 89.4 ;
    END
  END q[438]
  PIN q[439]
    DIRECTION OUTPUT ;
    USE SIGNAL ;
    PORT
      LAYER M4 ;
        RECT  0.054 89.568 0.138 89.592 ;
    END
  END q[439]
  PIN q[43]
    DIRECTION OUTPUT ;
    USE SIGNAL ;
    PORT
      LAYER M4 ;
        RECT  0.054 13.536 0.138 13.56 ;
    END
  END q[43]
  PIN q[440]
    DIRECTION OUTPUT ;
    USE SIGNAL ;
    PORT
      LAYER M4 ;
        RECT  0.054 89.76 0.138 89.784 ;
    END
  END q[440]
  PIN q[441]
    DIRECTION OUTPUT ;
    USE SIGNAL ;
    PORT
      LAYER M4 ;
        RECT  0.054 89.952 0.138 89.976 ;
    END
  END q[441]
  PIN q[442]
    DIRECTION OUTPUT ;
    USE SIGNAL ;
    PORT
      LAYER M4 ;
        RECT  0.054 90.144 0.138 90.168 ;
    END
  END q[442]
  PIN q[443]
    DIRECTION OUTPUT ;
    USE SIGNAL ;
    PORT
      LAYER M4 ;
        RECT  0.054 90.336 0.138 90.36 ;
    END
  END q[443]
  PIN q[444]
    DIRECTION OUTPUT ;
    USE SIGNAL ;
    PORT
      LAYER M4 ;
        RECT  0.054 90.528 0.138 90.552 ;
    END
  END q[444]
  PIN q[445]
    DIRECTION OUTPUT ;
    USE SIGNAL ;
    PORT
      LAYER M4 ;
        RECT  0.054 90.72 0.138 90.744 ;
    END
  END q[445]
  PIN q[446]
    DIRECTION OUTPUT ;
    USE SIGNAL ;
    PORT
      LAYER M4 ;
        RECT  0.054 90.912 0.138 90.936 ;
    END
  END q[446]
  PIN q[447]
    DIRECTION OUTPUT ;
    USE SIGNAL ;
    PORT
      LAYER M4 ;
        RECT  0.054 91.104 0.138 91.128 ;
    END
  END q[447]
  PIN q[448]
    DIRECTION OUTPUT ;
    USE SIGNAL ;
    PORT
      LAYER M4 ;
        RECT  0.054 91.296 0.138 91.32 ;
    END
  END q[448]
  PIN q[449]
    DIRECTION OUTPUT ;
    USE SIGNAL ;
    PORT
      LAYER M4 ;
        RECT  0.054 91.488 0.138 91.512 ;
    END
  END q[449]
  PIN q[44]
    DIRECTION OUTPUT ;
    USE SIGNAL ;
    PORT
      LAYER M4 ;
        RECT  0.054 13.728 0.138 13.752 ;
    END
  END q[44]
  PIN q[450]
    DIRECTION OUTPUT ;
    USE SIGNAL ;
    PORT
      LAYER M4 ;
        RECT  0.054 91.68 0.138 91.704 ;
    END
  END q[450]
  PIN q[451]
    DIRECTION OUTPUT ;
    USE SIGNAL ;
    PORT
      LAYER M4 ;
        RECT  0.054 91.872 0.138 91.896 ;
    END
  END q[451]
  PIN q[452]
    DIRECTION OUTPUT ;
    USE SIGNAL ;
    PORT
      LAYER M4 ;
        RECT  0.054 92.064 0.138 92.088 ;
    END
  END q[452]
  PIN q[453]
    DIRECTION OUTPUT ;
    USE SIGNAL ;
    PORT
      LAYER M4 ;
        RECT  0.054 92.256 0.138 92.28 ;
    END
  END q[453]
  PIN q[454]
    DIRECTION OUTPUT ;
    USE SIGNAL ;
    PORT
      LAYER M4 ;
        RECT  0.054 92.448 0.138 92.472 ;
    END
  END q[454]
  PIN q[455]
    DIRECTION OUTPUT ;
    USE SIGNAL ;
    PORT
      LAYER M4 ;
        RECT  0.054 92.64 0.138 92.664 ;
    END
  END q[455]
  PIN q[456]
    DIRECTION OUTPUT ;
    USE SIGNAL ;
    PORT
      LAYER M4 ;
        RECT  0.054 92.832 0.138 92.856 ;
    END
  END q[456]
  PIN q[457]
    DIRECTION OUTPUT ;
    USE SIGNAL ;
    PORT
      LAYER M4 ;
        RECT  0.054 93.024 0.138 93.048 ;
    END
  END q[457]
  PIN q[458]
    DIRECTION OUTPUT ;
    USE SIGNAL ;
    PORT
      LAYER M4 ;
        RECT  0.054 93.216 0.138 93.24 ;
    END
  END q[458]
  PIN q[459]
    DIRECTION OUTPUT ;
    USE SIGNAL ;
    PORT
      LAYER M4 ;
        RECT  0.054 93.408 0.138 93.432 ;
    END
  END q[459]
  PIN q[45]
    DIRECTION OUTPUT ;
    USE SIGNAL ;
    PORT
      LAYER M4 ;
        RECT  0.054 13.92 0.138 13.944 ;
    END
  END q[45]
  PIN q[460]
    DIRECTION OUTPUT ;
    USE SIGNAL ;
    PORT
      LAYER M4 ;
        RECT  0.054 93.6 0.138 93.624 ;
    END
  END q[460]
  PIN q[461]
    DIRECTION OUTPUT ;
    USE SIGNAL ;
    PORT
      LAYER M4 ;
        RECT  0.054 93.792 0.138 93.816 ;
    END
  END q[461]
  PIN q[462]
    DIRECTION OUTPUT ;
    USE SIGNAL ;
    PORT
      LAYER M4 ;
        RECT  0.054 93.984 0.138 94.008 ;
    END
  END q[462]
  PIN q[463]
    DIRECTION OUTPUT ;
    USE SIGNAL ;
    PORT
      LAYER M4 ;
        RECT  0.054 94.176 0.138 94.2 ;
    END
  END q[463]
  PIN q[464]
    DIRECTION OUTPUT ;
    USE SIGNAL ;
    PORT
      LAYER M4 ;
        RECT  0.054 94.368 0.138 94.392 ;
    END
  END q[464]
  PIN q[465]
    DIRECTION OUTPUT ;
    USE SIGNAL ;
    PORT
      LAYER M4 ;
        RECT  0.054 94.56 0.138 94.584 ;
    END
  END q[465]
  PIN q[466]
    DIRECTION OUTPUT ;
    USE SIGNAL ;
    PORT
      LAYER M4 ;
        RECT  0.054 94.752 0.138 94.776 ;
    END
  END q[466]
  PIN q[467]
    DIRECTION OUTPUT ;
    USE SIGNAL ;
    PORT
      LAYER M4 ;
        RECT  0.054 94.944 0.138 94.968 ;
    END
  END q[467]
  PIN q[468]
    DIRECTION OUTPUT ;
    USE SIGNAL ;
    PORT
      LAYER M4 ;
        RECT  0.054 95.136 0.138 95.16 ;
    END
  END q[468]
  PIN q[469]
    DIRECTION OUTPUT ;
    USE SIGNAL ;
    PORT
      LAYER M4 ;
        RECT  0.054 95.328 0.138 95.352 ;
    END
  END q[469]
  PIN q[46]
    DIRECTION OUTPUT ;
    USE SIGNAL ;
    PORT
      LAYER M4 ;
        RECT  0.054 14.112 0.138 14.136 ;
    END
  END q[46]
  PIN q[470]
    DIRECTION OUTPUT ;
    USE SIGNAL ;
    PORT
      LAYER M4 ;
        RECT  0.054 95.52 0.138 95.544 ;
    END
  END q[470]
  PIN q[471]
    DIRECTION OUTPUT ;
    USE SIGNAL ;
    PORT
      LAYER M4 ;
        RECT  0.054 95.712 0.138 95.736 ;
    END
  END q[471]
  PIN q[472]
    DIRECTION OUTPUT ;
    USE SIGNAL ;
    PORT
      LAYER M4 ;
        RECT  0.054 95.904 0.138 95.928 ;
    END
  END q[472]
  PIN q[473]
    DIRECTION OUTPUT ;
    USE SIGNAL ;
    PORT
      LAYER M4 ;
        RECT  0.054 96.096 0.138 96.12 ;
    END
  END q[473]
  PIN q[474]
    DIRECTION OUTPUT ;
    USE SIGNAL ;
    PORT
      LAYER M4 ;
        RECT  0.054 96.288 0.138 96.312 ;
    END
  END q[474]
  PIN q[475]
    DIRECTION OUTPUT ;
    USE SIGNAL ;
    PORT
      LAYER M4 ;
        RECT  0.054 96.48 0.138 96.504 ;
    END
  END q[475]
  PIN q[476]
    DIRECTION OUTPUT ;
    USE SIGNAL ;
    PORT
      LAYER M4 ;
        RECT  0.054 96.672 0.138 96.696 ;
    END
  END q[476]
  PIN q[477]
    DIRECTION OUTPUT ;
    USE SIGNAL ;
    PORT
      LAYER M4 ;
        RECT  0.054 96.864 0.138 96.888 ;
    END
  END q[477]
  PIN q[478]
    DIRECTION OUTPUT ;
    USE SIGNAL ;
    PORT
      LAYER M4 ;
        RECT  0.054 97.056 0.138 97.08 ;
    END
  END q[478]
  PIN q[479]
    DIRECTION OUTPUT ;
    USE SIGNAL ;
    PORT
      LAYER M4 ;
        RECT  0.054 97.248 0.138 97.272 ;
    END
  END q[479]
  PIN q[47]
    DIRECTION OUTPUT ;
    USE SIGNAL ;
    PORT
      LAYER M4 ;
        RECT  0.054 14.304 0.138 14.328 ;
    END
  END q[47]
  PIN q[480]
    DIRECTION OUTPUT ;
    USE SIGNAL ;
    PORT
      LAYER M4 ;
        RECT  0.054 97.44 0.138 97.464 ;
    END
  END q[480]
  PIN q[481]
    DIRECTION OUTPUT ;
    USE SIGNAL ;
    PORT
      LAYER M4 ;
        RECT  0.054 97.632 0.138 97.656 ;
    END
  END q[481]
  PIN q[482]
    DIRECTION OUTPUT ;
    USE SIGNAL ;
    PORT
      LAYER M4 ;
        RECT  0.054 97.824 0.138 97.848 ;
    END
  END q[482]
  PIN q[483]
    DIRECTION OUTPUT ;
    USE SIGNAL ;
    PORT
      LAYER M4 ;
        RECT  0.054 98.016 0.138 98.04 ;
    END
  END q[483]
  PIN q[484]
    DIRECTION OUTPUT ;
    USE SIGNAL ;
    PORT
      LAYER M4 ;
        RECT  0.054 98.208 0.138 98.232 ;
    END
  END q[484]
  PIN q[485]
    DIRECTION OUTPUT ;
    USE SIGNAL ;
    PORT
      LAYER M4 ;
        RECT  0.054 98.4 0.138 98.424 ;
    END
  END q[485]
  PIN q[486]
    DIRECTION OUTPUT ;
    USE SIGNAL ;
    PORT
      LAYER M4 ;
        RECT  0.054 98.592 0.138 98.616 ;
    END
  END q[486]
  PIN q[487]
    DIRECTION OUTPUT ;
    USE SIGNAL ;
    PORT
      LAYER M4 ;
        RECT  0.054 98.784 0.138 98.808 ;
    END
  END q[487]
  PIN q[488]
    DIRECTION OUTPUT ;
    USE SIGNAL ;
    PORT
      LAYER M4 ;
        RECT  0.054 98.976 0.138 99 ;
    END
  END q[488]
  PIN q[489]
    DIRECTION OUTPUT ;
    USE SIGNAL ;
    PORT
      LAYER M4 ;
        RECT  0.054 99.168 0.138 99.192 ;
    END
  END q[489]
  PIN q[48]
    DIRECTION OUTPUT ;
    USE SIGNAL ;
    PORT
      LAYER M4 ;
        RECT  0.054 14.496 0.138 14.52 ;
    END
  END q[48]
  PIN q[490]
    DIRECTION OUTPUT ;
    USE SIGNAL ;
    PORT
      LAYER M4 ;
        RECT  0.054 99.36 0.138 99.384 ;
    END
  END q[490]
  PIN q[491]
    DIRECTION OUTPUT ;
    USE SIGNAL ;
    PORT
      LAYER M4 ;
        RECT  0.054 99.552 0.138 99.576 ;
    END
  END q[491]
  PIN q[492]
    DIRECTION OUTPUT ;
    USE SIGNAL ;
    PORT
      LAYER M4 ;
        RECT  0.054 99.744 0.138 99.768 ;
    END
  END q[492]
  PIN q[493]
    DIRECTION OUTPUT ;
    USE SIGNAL ;
    PORT
      LAYER M4 ;
        RECT  0.054 99.936 0.138 99.96 ;
    END
  END q[493]
  PIN q[494]
    DIRECTION OUTPUT ;
    USE SIGNAL ;
    PORT
      LAYER M4 ;
        RECT  0.054 100.128 0.138 100.152 ;
    END
  END q[494]
  PIN q[495]
    DIRECTION OUTPUT ;
    USE SIGNAL ;
    PORT
      LAYER M4 ;
        RECT  0.054 100.32 0.138 100.344 ;
    END
  END q[495]
  PIN q[496]
    DIRECTION OUTPUT ;
    USE SIGNAL ;
    PORT
      LAYER M4 ;
        RECT  0.054 100.512 0.138 100.536 ;
    END
  END q[496]
  PIN q[497]
    DIRECTION OUTPUT ;
    USE SIGNAL ;
    PORT
      LAYER M4 ;
        RECT  0.054 100.704 0.138 100.728 ;
    END
  END q[497]
  PIN q[498]
    DIRECTION OUTPUT ;
    USE SIGNAL ;
    PORT
      LAYER M4 ;
        RECT  0.054 100.896 0.138 100.92 ;
    END
  END q[498]
  PIN q[499]
    DIRECTION OUTPUT ;
    USE SIGNAL ;
    PORT
      LAYER M4 ;
        RECT  0.054 101.088 0.138 101.112 ;
    END
  END q[499]
  PIN q[49]
    DIRECTION OUTPUT ;
    USE SIGNAL ;
    PORT
      LAYER M4 ;
        RECT  0.054 14.688 0.138 14.712 ;
    END
  END q[49]
  PIN q[4]
    DIRECTION OUTPUT ;
    USE SIGNAL ;
    PORT
      LAYER M4 ;
        RECT  0.054 6.048 0.138 6.072 ;
    END
  END q[4]
  PIN q[500]
    DIRECTION OUTPUT ;
    USE SIGNAL ;
    PORT
      LAYER M4 ;
        RECT  0.054 101.28 0.138 101.304 ;
    END
  END q[500]
  PIN q[501]
    DIRECTION OUTPUT ;
    USE SIGNAL ;
    PORT
      LAYER M4 ;
        RECT  0.054 101.472 0.138 101.496 ;
    END
  END q[501]
  PIN q[502]
    DIRECTION OUTPUT ;
    USE SIGNAL ;
    PORT
      LAYER M4 ;
        RECT  0.054 101.664 0.138 101.688 ;
    END
  END q[502]
  PIN q[503]
    DIRECTION OUTPUT ;
    USE SIGNAL ;
    PORT
      LAYER M4 ;
        RECT  0.054 101.856 0.138 101.88 ;
    END
  END q[503]
  PIN q[504]
    DIRECTION OUTPUT ;
    USE SIGNAL ;
    PORT
      LAYER M4 ;
        RECT  0.054 102.048 0.138 102.072 ;
    END
  END q[504]
  PIN q[505]
    DIRECTION OUTPUT ;
    USE SIGNAL ;
    PORT
      LAYER M4 ;
        RECT  0.054 102.24 0.138 102.264 ;
    END
  END q[505]
  PIN q[506]
    DIRECTION OUTPUT ;
    USE SIGNAL ;
    PORT
      LAYER M4 ;
        RECT  0.054 102.432 0.138 102.456 ;
    END
  END q[506]
  PIN q[507]
    DIRECTION OUTPUT ;
    USE SIGNAL ;
    PORT
      LAYER M4 ;
        RECT  0.054 102.624 0.138 102.648 ;
    END
  END q[507]
  PIN q[508]
    DIRECTION OUTPUT ;
    USE SIGNAL ;
    PORT
      LAYER M4 ;
        RECT  0.054 102.816 0.138 102.84 ;
    END
  END q[508]
  PIN q[509]
    DIRECTION OUTPUT ;
    USE SIGNAL ;
    PORT
      LAYER M4 ;
        RECT  0.054 103.008 0.138 103.032 ;
    END
  END q[509]
  PIN q[50]
    DIRECTION OUTPUT ;
    USE SIGNAL ;
    PORT
      LAYER M4 ;
        RECT  0.054 14.88 0.138 14.904 ;
    END
  END q[50]
  PIN q[510]
    DIRECTION OUTPUT ;
    USE SIGNAL ;
    PORT
      LAYER M4 ;
        RECT  0.054 103.2 0.138 103.224 ;
    END
  END q[510]
  PIN q[511]
    DIRECTION OUTPUT ;
    USE SIGNAL ;
    PORT
      LAYER M4 ;
        RECT  0.054 103.392 0.138 103.416 ;
    END
  END q[511]
  PIN q[512]
    DIRECTION OUTPUT ;
    USE SIGNAL ;
    PORT
      LAYER M4 ;
        RECT  0.054 103.584 0.138 103.608 ;
    END
  END q[512]
  PIN q[513]
    DIRECTION OUTPUT ;
    USE SIGNAL ;
    PORT
      LAYER M4 ;
        RECT  0.054 103.776 0.138 103.8 ;
    END
  END q[513]
  PIN q[51]
    DIRECTION OUTPUT ;
    USE SIGNAL ;
    PORT
      LAYER M4 ;
        RECT  0.054 15.072 0.138 15.096 ;
    END
  END q[51]
  PIN q[52]
    DIRECTION OUTPUT ;
    USE SIGNAL ;
    PORT
      LAYER M4 ;
        RECT  0.054 15.264 0.138 15.288 ;
    END
  END q[52]
  PIN q[53]
    DIRECTION OUTPUT ;
    USE SIGNAL ;
    PORT
      LAYER M4 ;
        RECT  0.054 15.456 0.138 15.48 ;
    END
  END q[53]
  PIN q[54]
    DIRECTION OUTPUT ;
    USE SIGNAL ;
    PORT
      LAYER M4 ;
        RECT  0.054 15.648 0.138 15.672 ;
    END
  END q[54]
  PIN q[55]
    DIRECTION OUTPUT ;
    USE SIGNAL ;
    PORT
      LAYER M4 ;
        RECT  0.054 15.84 0.138 15.864 ;
    END
  END q[55]
  PIN q[56]
    DIRECTION OUTPUT ;
    USE SIGNAL ;
    PORT
      LAYER M4 ;
        RECT  0.054 16.032 0.138 16.056 ;
    END
  END q[56]
  PIN q[57]
    DIRECTION OUTPUT ;
    USE SIGNAL ;
    PORT
      LAYER M4 ;
        RECT  0.054 16.224 0.138 16.248 ;
    END
  END q[57]
  PIN q[58]
    DIRECTION OUTPUT ;
    USE SIGNAL ;
    PORT
      LAYER M4 ;
        RECT  0.054 16.416 0.138 16.44 ;
    END
  END q[58]
  PIN q[59]
    DIRECTION OUTPUT ;
    USE SIGNAL ;
    PORT
      LAYER M4 ;
        RECT  0.054 16.608 0.138 16.632 ;
    END
  END q[59]
  PIN q[5]
    DIRECTION OUTPUT ;
    USE SIGNAL ;
    PORT
      LAYER M4 ;
        RECT  0.054 6.24 0.138 6.264 ;
    END
  END q[5]
  PIN q[60]
    DIRECTION OUTPUT ;
    USE SIGNAL ;
    PORT
      LAYER M4 ;
        RECT  0.054 16.8 0.138 16.824 ;
    END
  END q[60]
  PIN q[61]
    DIRECTION OUTPUT ;
    USE SIGNAL ;
    PORT
      LAYER M4 ;
        RECT  0.054 16.992 0.138 17.016 ;
    END
  END q[61]
  PIN q[62]
    DIRECTION OUTPUT ;
    USE SIGNAL ;
    PORT
      LAYER M4 ;
        RECT  0.054 17.184 0.138 17.208 ;
    END
  END q[62]
  PIN q[63]
    DIRECTION OUTPUT ;
    USE SIGNAL ;
    PORT
      LAYER M4 ;
        RECT  0.054 17.376 0.138 17.4 ;
    END
  END q[63]
  PIN q[64]
    DIRECTION OUTPUT ;
    USE SIGNAL ;
    PORT
      LAYER M4 ;
        RECT  0.054 17.568 0.138 17.592 ;
    END
  END q[64]
  PIN q[65]
    DIRECTION OUTPUT ;
    USE SIGNAL ;
    PORT
      LAYER M4 ;
        RECT  0.054 17.76 0.138 17.784 ;
    END
  END q[65]
  PIN q[66]
    DIRECTION OUTPUT ;
    USE SIGNAL ;
    PORT
      LAYER M4 ;
        RECT  0.054 17.952 0.138 17.976 ;
    END
  END q[66]
  PIN q[67]
    DIRECTION OUTPUT ;
    USE SIGNAL ;
    PORT
      LAYER M4 ;
        RECT  0.054 18.144 0.138 18.168 ;
    END
  END q[67]
  PIN q[68]
    DIRECTION OUTPUT ;
    USE SIGNAL ;
    PORT
      LAYER M4 ;
        RECT  0.054 18.336 0.138 18.36 ;
    END
  END q[68]
  PIN q[69]
    DIRECTION OUTPUT ;
    USE SIGNAL ;
    PORT
      LAYER M4 ;
        RECT  0.054 18.528 0.138 18.552 ;
    END
  END q[69]
  PIN q[6]
    DIRECTION OUTPUT ;
    USE SIGNAL ;
    PORT
      LAYER M4 ;
        RECT  0.054 6.432 0.138 6.456 ;
    END
  END q[6]
  PIN q[70]
    DIRECTION OUTPUT ;
    USE SIGNAL ;
    PORT
      LAYER M4 ;
        RECT  0.054 18.72 0.138 18.744 ;
    END
  END q[70]
  PIN q[71]
    DIRECTION OUTPUT ;
    USE SIGNAL ;
    PORT
      LAYER M4 ;
        RECT  0.054 18.912 0.138 18.936 ;
    END
  END q[71]
  PIN q[72]
    DIRECTION OUTPUT ;
    USE SIGNAL ;
    PORT
      LAYER M4 ;
        RECT  0.054 19.104 0.138 19.128 ;
    END
  END q[72]
  PIN q[73]
    DIRECTION OUTPUT ;
    USE SIGNAL ;
    PORT
      LAYER M4 ;
        RECT  0.054 19.296 0.138 19.32 ;
    END
  END q[73]
  PIN q[74]
    DIRECTION OUTPUT ;
    USE SIGNAL ;
    PORT
      LAYER M4 ;
        RECT  0.054 19.488 0.138 19.512 ;
    END
  END q[74]
  PIN q[75]
    DIRECTION OUTPUT ;
    USE SIGNAL ;
    PORT
      LAYER M4 ;
        RECT  0.054 19.68 0.138 19.704 ;
    END
  END q[75]
  PIN q[76]
    DIRECTION OUTPUT ;
    USE SIGNAL ;
    PORT
      LAYER M4 ;
        RECT  0.054 19.872 0.138 19.896 ;
    END
  END q[76]
  PIN q[77]
    DIRECTION OUTPUT ;
    USE SIGNAL ;
    PORT
      LAYER M4 ;
        RECT  0.054 20.064 0.138 20.088 ;
    END
  END q[77]
  PIN q[78]
    DIRECTION OUTPUT ;
    USE SIGNAL ;
    PORT
      LAYER M4 ;
        RECT  0.054 20.256 0.138 20.28 ;
    END
  END q[78]
  PIN q[79]
    DIRECTION OUTPUT ;
    USE SIGNAL ;
    PORT
      LAYER M4 ;
        RECT  0.054 20.448 0.138 20.472 ;
    END
  END q[79]
  PIN q[7]
    DIRECTION OUTPUT ;
    USE SIGNAL ;
    PORT
      LAYER M4 ;
        RECT  0.054 6.624 0.138 6.648 ;
    END
  END q[7]
  PIN q[80]
    DIRECTION OUTPUT ;
    USE SIGNAL ;
    PORT
      LAYER M4 ;
        RECT  0.054 20.64 0.138 20.664 ;
    END
  END q[80]
  PIN q[81]
    DIRECTION OUTPUT ;
    USE SIGNAL ;
    PORT
      LAYER M4 ;
        RECT  0.054 20.832 0.138 20.856 ;
    END
  END q[81]
  PIN q[82]
    DIRECTION OUTPUT ;
    USE SIGNAL ;
    PORT
      LAYER M4 ;
        RECT  0.054 21.024 0.138 21.048 ;
    END
  END q[82]
  PIN q[83]
    DIRECTION OUTPUT ;
    USE SIGNAL ;
    PORT
      LAYER M4 ;
        RECT  0.054 21.216 0.138 21.24 ;
    END
  END q[83]
  PIN q[84]
    DIRECTION OUTPUT ;
    USE SIGNAL ;
    PORT
      LAYER M4 ;
        RECT  0.054 21.408 0.138 21.432 ;
    END
  END q[84]
  PIN q[85]
    DIRECTION OUTPUT ;
    USE SIGNAL ;
    PORT
      LAYER M4 ;
        RECT  0.054 21.6 0.138 21.624 ;
    END
  END q[85]
  PIN q[86]
    DIRECTION OUTPUT ;
    USE SIGNAL ;
    PORT
      LAYER M4 ;
        RECT  0.054 21.792 0.138 21.816 ;
    END
  END q[86]
  PIN q[87]
    DIRECTION OUTPUT ;
    USE SIGNAL ;
    PORT
      LAYER M4 ;
        RECT  0.054 21.984 0.138 22.008 ;
    END
  END q[87]
  PIN q[88]
    DIRECTION OUTPUT ;
    USE SIGNAL ;
    PORT
      LAYER M4 ;
        RECT  0.054 22.176 0.138 22.2 ;
    END
  END q[88]
  PIN q[89]
    DIRECTION OUTPUT ;
    USE SIGNAL ;
    PORT
      LAYER M4 ;
        RECT  0.054 22.368 0.138 22.392 ;
    END
  END q[89]
  PIN q[8]
    DIRECTION OUTPUT ;
    USE SIGNAL ;
    PORT
      LAYER M4 ;
        RECT  0.054 6.816 0.138 6.84 ;
    END
  END q[8]
  PIN q[90]
    DIRECTION OUTPUT ;
    USE SIGNAL ;
    PORT
      LAYER M4 ;
        RECT  0.054 22.56 0.138 22.584 ;
    END
  END q[90]
  PIN q[91]
    DIRECTION OUTPUT ;
    USE SIGNAL ;
    PORT
      LAYER M4 ;
        RECT  0.054 22.752 0.138 22.776 ;
    END
  END q[91]
  PIN q[92]
    DIRECTION OUTPUT ;
    USE SIGNAL ;
    PORT
      LAYER M4 ;
        RECT  0.054 22.944 0.138 22.968 ;
    END
  END q[92]
  PIN q[93]
    DIRECTION OUTPUT ;
    USE SIGNAL ;
    PORT
      LAYER M4 ;
        RECT  0.054 23.136 0.138 23.16 ;
    END
  END q[93]
  PIN q[94]
    DIRECTION OUTPUT ;
    USE SIGNAL ;
    PORT
      LAYER M4 ;
        RECT  0.054 23.328 0.138 23.352 ;
    END
  END q[94]
  PIN q[95]
    DIRECTION OUTPUT ;
    USE SIGNAL ;
    PORT
      LAYER M4 ;
        RECT  0.054 23.52 0.138 23.544 ;
    END
  END q[95]
  PIN q[96]
    DIRECTION OUTPUT ;
    USE SIGNAL ;
    PORT
      LAYER M4 ;
        RECT  0.054 23.712 0.138 23.736 ;
    END
  END q[96]
  PIN q[97]
    DIRECTION OUTPUT ;
    USE SIGNAL ;
    PORT
      LAYER M4 ;
        RECT  0.054 23.904 0.138 23.928 ;
    END
  END q[97]
  PIN q[98]
    DIRECTION OUTPUT ;
    USE SIGNAL ;
    PORT
      LAYER M4 ;
        RECT  0.054 24.096 0.138 24.12 ;
    END
  END q[98]
  PIN q[99]
    DIRECTION OUTPUT ;
    USE SIGNAL ;
    PORT
      LAYER M4 ;
        RECT  0.054 24.288 0.138 24.312 ;
    END
  END q[99]
  PIN q[9]
    DIRECTION OUTPUT ;
    USE SIGNAL ;
    PORT
      LAYER M4 ;
        RECT  0.054 7.008 0.138 7.032 ;
    END
  END q[9]
  PIN rst_n
    DIRECTION INPUT ;
    USE SIGNAL ;
    PORT
      LAYER M5 ;
        RECT  9.696 0.054 9.72 0.138 ;
    END
    PORT
      LAYER M5 ;
        RECT  9.696 0.08 9.72 2.137 ;
    END
  END rst_n
  PIN VDD
    DIRECTION INOUT ;
    USE POWER ;
    PORT
      LAYER M5 ;
        RECT  18.792 2.151 18.912 103.689 ;
        RECT  16.092 2.151 16.212 103.689 ;
        RECT  13.392 2.151 13.512 103.689 ;
        RECT  10.692 2.151 10.812 103.689 ;
        RECT  7.992 2.151 8.112 103.689 ;
        RECT  5.292 2.151 5.412 103.689 ;
        RECT  2.592 2.151 2.712 103.689 ;
    END
  END VDD
  PIN VSS
    DIRECTION INOUT ;
    USE GROUND ;
    PORT
      LAYER M5 ;
        RECT  18.6 2.137 18.72 103.703 ;
        RECT  15.9 2.137 16.02 103.703 ;
        RECT  13.2 2.137 13.32 103.703 ;
        RECT  10.5 2.137 10.62 103.703 ;
        RECT  7.8 2.137 7.92 103.703 ;
        RECT  5.1 2.137 5.22 103.703 ;
        RECT  2.4 2.137 2.52 103.703 ;
    END
  END VSS
  # OT_OBS_CLOSED layer=M5 d_um=1.536 added=56
  OBS
    LAYER RVTN ;
     RECT  2.16 2.16 19.44 2.295 ;
     RECT  2.16 2.565 19.44 2.835 ;
     RECT  2.16 3.105 19.44 3.375 ;
     RECT  2.16 3.645 19.44 3.915 ;
     RECT  2.16 4.185 19.44 4.455 ;
     RECT  2.16 4.725 19.44 4.995 ;
     RECT  2.16 5.265 19.44 5.535 ;
     RECT  2.16 5.805 19.44 6.075 ;
     RECT  2.16 6.345 19.44 6.615 ;
     RECT  2.16 6.885 19.44 7.155 ;
     RECT  2.16 7.425 19.44 7.695 ;
     RECT  2.16 7.965 19.44 8.235 ;
     RECT  2.16 8.505 19.44 8.775 ;
     RECT  2.16 9.045 19.44 9.315 ;
     RECT  2.16 9.585 19.44 9.855 ;
     RECT  2.16 10.125 19.44 10.395 ;
     RECT  2.16 10.665 19.44 10.935 ;
     RECT  2.16 11.205 19.44 11.475 ;
     RECT  2.16 11.745 19.44 12.015 ;
     RECT  2.16 12.285 19.44 12.555 ;
     RECT  2.16 12.825 19.44 13.095 ;
     RECT  2.16 13.365 19.44 13.635 ;
     RECT  2.16 13.905 19.44 14.175 ;
     RECT  2.16 14.445 19.44 14.715 ;
     RECT  2.16 14.985 19.44 15.255 ;
     RECT  2.16 15.525 19.44 15.795 ;
     RECT  2.16 16.065 19.44 16.335 ;
     RECT  2.16 16.605 19.44 16.875 ;
     RECT  2.16 17.145 19.44 17.415 ;
     RECT  2.16 17.685 19.44 17.955 ;
     RECT  2.16 18.225 19.44 18.495 ;
     RECT  2.16 18.765 19.44 19.035 ;
     RECT  2.16 19.305 19.44 19.575 ;
     RECT  2.16 19.845 19.44 20.115 ;
     RECT  2.16 20.385 19.44 20.655 ;
     RECT  2.16 20.925 19.44 21.195 ;
     RECT  2.16 21.465 19.44 21.735 ;
     RECT  2.16 22.005 19.44 22.275 ;
     RECT  2.16 22.545 19.44 22.815 ;
     RECT  2.16 23.085 19.44 23.355 ;
     RECT  2.16 23.625 19.44 23.895 ;
     RECT  2.16 24.165 19.44 24.435 ;
     RECT  2.16 24.705 19.44 24.975 ;
     RECT  2.16 25.245 19.44 25.515 ;
     RECT  2.16 25.785 19.44 26.055 ;
     RECT  2.16 26.325 19.44 26.595 ;
     RECT  2.16 26.865 19.44 27.135 ;
     RECT  2.16 27.405 19.44 27.675 ;
     RECT  2.16 27.945 19.44 28.215 ;
     RECT  2.16 28.485 19.44 28.755 ;
     RECT  2.16 29.025 19.44 29.295 ;
     RECT  2.16 29.565 19.44 29.835 ;
     RECT  2.16 30.105 19.44 30.375 ;
     RECT  2.16 30.645 19.44 30.915 ;
     RECT  2.16 31.185 19.44 31.455 ;
     RECT  2.16 31.725 19.44 31.995 ;
     RECT  2.16 32.265 19.44 32.535 ;
     RECT  2.16 32.805 19.44 33.075 ;
     RECT  2.16 33.345 19.44 33.615 ;
     RECT  2.16 33.885 19.44 34.155 ;
     RECT  2.16 34.425 19.44 34.695 ;
     RECT  2.16 34.965 19.44 35.235 ;
     RECT  2.16 35.505 19.44 35.775 ;
     RECT  2.16 36.045 19.44 36.315 ;
     RECT  2.16 36.585 19.44 36.855 ;
     RECT  2.16 37.125 19.44 37.395 ;
     RECT  2.16 37.665 19.44 37.935 ;
     RECT  2.16 38.205 19.44 38.475 ;
     RECT  2.16 38.745 19.44 39.015 ;
     RECT  2.16 39.285 19.44 39.555 ;
     RECT  2.16 39.825 19.44 40.095 ;
     RECT  2.16 40.365 19.44 40.635 ;
     RECT  2.16 40.905 19.44 41.175 ;
     RECT  2.16 41.445 19.44 41.715 ;
     RECT  2.16 41.985 19.44 42.255 ;
     RECT  2.16 42.525 19.44 42.795 ;
     RECT  2.16 43.065 19.44 43.335 ;
     RECT  2.16 43.605 19.44 43.875 ;
     RECT  2.16 44.145 19.44 44.415 ;
     RECT  2.16 44.685 19.44 44.955 ;
     RECT  2.16 45.225 19.44 45.495 ;
     RECT  2.16 45.765 19.44 46.035 ;
     RECT  2.16 46.305 19.44 46.575 ;
     RECT  2.16 46.845 19.44 47.115 ;
     RECT  2.16 47.385 19.44 47.655 ;
     RECT  2.16 47.925 19.44 48.195 ;
     RECT  2.16 48.465 19.44 48.735 ;
     RECT  2.16 49.005 19.44 49.275 ;
     RECT  2.16 49.545 19.44 49.815 ;
     RECT  2.16 50.085 19.44 50.355 ;
     RECT  2.16 50.625 19.44 50.895 ;
     RECT  2.16 51.165 19.44 51.435 ;
     RECT  2.16 51.705 19.44 51.975 ;
     RECT  2.16 52.245 19.44 52.515 ;
     RECT  2.16 52.785 19.44 53.055 ;
     RECT  2.16 53.325 19.44 53.595 ;
     RECT  2.16 53.865 19.44 54.135 ;
     RECT  2.16 54.405 19.44 54.675 ;
     RECT  2.16 54.945 19.44 55.215 ;
     RECT  2.16 55.485 19.44 55.755 ;
     RECT  2.16 56.025 19.44 56.295 ;
     RECT  2.16 56.565 19.44 56.835 ;
     RECT  2.16 57.105 19.44 57.375 ;
     RECT  2.16 57.645 19.44 57.915 ;
     RECT  2.16 58.185 19.44 58.455 ;
     RECT  2.16 58.725 19.44 58.995 ;
     RECT  2.16 59.265 19.44 59.535 ;
     RECT  2.16 59.805 19.44 60.075 ;
     RECT  2.16 60.345 19.44 60.615 ;
     RECT  2.16 60.885 19.44 61.155 ;
     RECT  2.16 61.425 19.44 61.695 ;
     RECT  2.16 61.965 19.44 62.235 ;
     RECT  2.16 62.505 19.44 62.775 ;
     RECT  2.16 63.045 19.44 63.315 ;
     RECT  2.16 63.585 19.44 63.855 ;
     RECT  2.16 64.125 19.44 64.395 ;
     RECT  2.16 64.665 19.44 64.935 ;
     RECT  2.16 65.205 19.44 65.475 ;
     RECT  2.16 65.745 19.44 66.015 ;
     RECT  2.16 66.285 19.44 66.555 ;
     RECT  2.16 66.825 19.44 67.095 ;
     RECT  2.16 67.365 19.44 67.635 ;
     RECT  2.16 67.905 19.44 68.175 ;
     RECT  2.16 68.445 19.44 68.715 ;
     RECT  2.16 68.985 19.44 69.255 ;
     RECT  2.16 69.525 19.44 69.795 ;
     RECT  2.16 70.065 19.44 70.335 ;
     RECT  2.16 70.605 19.44 70.875 ;
     RECT  2.16 71.145 19.44 71.415 ;
     RECT  2.16 71.685 19.44 71.955 ;
     RECT  2.16 72.225 19.44 72.495 ;
     RECT  2.16 72.765 19.44 73.035 ;
     RECT  2.16 73.305 19.44 73.575 ;
     RECT  2.16 73.845 19.44 74.115 ;
     RECT  2.16 74.385 19.44 74.655 ;
     RECT  2.16 74.925 19.44 75.195 ;
     RECT  2.16 75.465 19.44 75.735 ;
     RECT  2.16 76.005 19.44 76.275 ;
     RECT  2.16 76.545 19.44 76.815 ;
     RECT  2.16 77.085 19.44 77.355 ;
     RECT  2.16 77.625 19.44 77.895 ;
     RECT  2.16 78.165 19.44 78.435 ;
     RECT  2.16 78.705 19.44 78.975 ;
     RECT  2.16 79.245 19.44 79.515 ;
     RECT  2.16 79.785 19.44 80.055 ;
     RECT  2.16 80.325 19.44 80.595 ;
     RECT  2.16 80.865 19.44 81.135 ;
     RECT  2.16 81.405 19.44 81.675 ;
     RECT  2.16 81.945 19.44 82.215 ;
     RECT  2.16 82.485 19.44 82.755 ;
     RECT  2.16 83.025 19.44 83.295 ;
     RECT  2.16 83.565 19.44 83.835 ;
     RECT  2.16 84.105 19.44 84.375 ;
     RECT  2.16 84.645 19.44 84.915 ;
     RECT  2.16 85.185 19.44 85.455 ;
     RECT  2.16 85.725 19.44 85.995 ;
     RECT  2.16 86.265 19.44 86.535 ;
     RECT  2.16 86.805 19.44 87.075 ;
     RECT  2.16 87.345 19.44 87.615 ;
     RECT  2.16 87.885 19.44 88.155 ;
     RECT  2.16 88.425 19.44 88.695 ;
     RECT  2.16 88.965 19.44 89.235 ;
     RECT  2.16 89.505 19.44 89.775 ;
     RECT  2.16 90.045 19.44 90.315 ;
     RECT  2.16 90.585 19.44 90.855 ;
     RECT  2.16 91.125 19.44 91.395 ;
     RECT  2.16 91.665 19.44 91.935 ;
     RECT  2.16 92.205 19.44 92.475 ;
     RECT  2.16 92.745 19.44 93.015 ;
     RECT  2.16 93.285 19.44 93.555 ;
     RECT  2.16 93.825 19.44 94.095 ;
     RECT  2.16 94.365 19.44 94.635 ;
     RECT  2.16 94.905 19.44 95.175 ;
     RECT  2.16 95.445 19.44 95.715 ;
     RECT  2.16 95.985 19.44 96.255 ;
     RECT  2.16 96.525 19.44 96.795 ;
     RECT  2.16 97.065 19.44 97.335 ;
     RECT  2.16 97.605 19.44 97.875 ;
     RECT  2.16 98.145 19.44 98.415 ;
     RECT  2.16 98.685 19.44 98.955 ;
     RECT  2.16 99.225 19.44 99.495 ;
     RECT  2.16 99.765 19.44 100.035 ;
     RECT  2.16 100.305 19.44 100.575 ;
     RECT  2.16 100.845 19.44 101.115 ;
     RECT  2.16 101.385 19.44 101.655 ;
     RECT  2.16 101.925 19.44 102.195 ;
     RECT  2.16 102.465 19.44 102.735 ;
     RECT  2.16 103.005 19.44 103.275 ;
     RECT  2.16 103.545 19.44 103.68 ;
    LAYER RVTP ;
     RECT  2.16 2.295 19.44 2.565 ;
     RECT  2.16 2.835 19.44 3.105 ;
     RECT  2.16 3.375 19.44 3.645 ;
     RECT  2.16 3.915 19.44 4.185 ;
     RECT  2.16 4.455 19.44 4.725 ;
     RECT  2.16 4.995 19.44 5.265 ;
     RECT  2.16 5.535 19.44 5.805 ;
     RECT  2.16 6.075 19.44 6.345 ;
     RECT  2.16 6.615 19.44 6.885 ;
     RECT  2.16 7.155 19.44 7.425 ;
     RECT  2.16 7.695 19.44 7.965 ;
     RECT  2.16 8.235 19.44 8.505 ;
     RECT  2.16 8.775 19.44 9.045 ;
     RECT  2.16 9.315 19.44 9.585 ;
     RECT  2.16 9.855 19.44 10.125 ;
     RECT  2.16 10.395 19.44 10.665 ;
     RECT  2.16 10.935 19.44 11.205 ;
     RECT  2.16 11.475 19.44 11.745 ;
     RECT  2.16 12.015 19.44 12.285 ;
     RECT  2.16 12.555 19.44 12.825 ;
     RECT  2.16 13.095 19.44 13.365 ;
     RECT  2.16 13.635 19.44 13.905 ;
     RECT  2.16 14.175 19.44 14.445 ;
     RECT  2.16 14.715 19.44 14.985 ;
     RECT  2.16 15.255 19.44 15.525 ;
     RECT  2.16 15.795 19.44 16.065 ;
     RECT  2.16 16.335 19.44 16.605 ;
     RECT  2.16 16.875 19.44 17.145 ;
     RECT  2.16 17.415 19.44 17.685 ;
     RECT  2.16 17.955 19.44 18.225 ;
     RECT  2.16 18.495 19.44 18.765 ;
     RECT  2.16 19.035 19.44 19.305 ;
     RECT  2.16 19.575 19.44 19.845 ;
     RECT  2.16 20.115 19.44 20.385 ;
     RECT  2.16 20.655 19.44 20.925 ;
     RECT  2.16 21.195 19.44 21.465 ;
     RECT  2.16 21.735 19.44 22.005 ;
     RECT  2.16 22.275 19.44 22.545 ;
     RECT  2.16 22.815 19.44 23.085 ;
     RECT  2.16 23.355 19.44 23.625 ;
     RECT  2.16 23.895 19.44 24.165 ;
     RECT  2.16 24.435 19.44 24.705 ;
     RECT  2.16 24.975 19.44 25.245 ;
     RECT  2.16 25.515 19.44 25.785 ;
     RECT  2.16 26.055 19.44 26.325 ;
     RECT  2.16 26.595 19.44 26.865 ;
     RECT  2.16 27.135 19.44 27.405 ;
     RECT  2.16 27.675 19.44 27.945 ;
     RECT  2.16 28.215 19.44 28.485 ;
     RECT  2.16 28.755 19.44 29.025 ;
     RECT  2.16 29.295 19.44 29.565 ;
     RECT  2.16 29.835 19.44 30.105 ;
     RECT  2.16 30.375 19.44 30.645 ;
     RECT  2.16 30.915 19.44 31.185 ;
     RECT  2.16 31.455 19.44 31.725 ;
     RECT  2.16 31.995 19.44 32.265 ;
     RECT  2.16 32.535 19.44 32.805 ;
     RECT  2.16 33.075 19.44 33.345 ;
     RECT  2.16 33.615 19.44 33.885 ;
     RECT  2.16 34.155 19.44 34.425 ;
     RECT  2.16 34.695 19.44 34.965 ;
     RECT  2.16 35.235 19.44 35.505 ;
     RECT  2.16 35.775 19.44 36.045 ;
     RECT  2.16 36.315 19.44 36.585 ;
     RECT  2.16 36.855 19.44 37.125 ;
     RECT  2.16 37.395 19.44 37.665 ;
     RECT  2.16 37.935 19.44 38.205 ;
     RECT  2.16 38.475 19.44 38.745 ;
     RECT  2.16 39.015 19.44 39.285 ;
     RECT  2.16 39.555 19.44 39.825 ;
     RECT  2.16 40.095 19.44 40.365 ;
     RECT  2.16 40.635 19.44 40.905 ;
     RECT  2.16 41.175 19.44 41.445 ;
     RECT  2.16 41.715 19.44 41.985 ;
     RECT  2.16 42.255 19.44 42.525 ;
     RECT  2.16 42.795 19.44 43.065 ;
     RECT  2.16 43.335 19.44 43.605 ;
     RECT  2.16 43.875 19.44 44.145 ;
     RECT  2.16 44.415 19.44 44.685 ;
     RECT  2.16 44.955 19.44 45.225 ;
     RECT  2.16 45.495 19.44 45.765 ;
     RECT  2.16 46.035 19.44 46.305 ;
     RECT  2.16 46.575 19.44 46.845 ;
     RECT  2.16 47.115 19.44 47.385 ;
     RECT  2.16 47.655 19.44 47.925 ;
     RECT  2.16 48.195 19.44 48.465 ;
     RECT  2.16 48.735 19.44 49.005 ;
     RECT  2.16 49.275 19.44 49.545 ;
     RECT  2.16 49.815 19.44 50.085 ;
     RECT  2.16 50.355 19.44 50.625 ;
     RECT  2.16 50.895 19.44 51.165 ;
     RECT  2.16 51.435 19.44 51.705 ;
     RECT  2.16 51.975 19.44 52.245 ;
     RECT  2.16 52.515 19.44 52.785 ;
     RECT  2.16 53.055 19.44 53.325 ;
     RECT  2.16 53.595 19.44 53.865 ;
     RECT  2.16 54.135 19.44 54.405 ;
     RECT  2.16 54.675 19.44 54.945 ;
     RECT  2.16 55.215 19.44 55.485 ;
     RECT  2.16 55.755 19.44 56.025 ;
     RECT  2.16 56.295 19.44 56.565 ;
     RECT  2.16 56.835 19.44 57.105 ;
     RECT  2.16 57.375 19.44 57.645 ;
     RECT  2.16 57.915 19.44 58.185 ;
     RECT  2.16 58.455 19.44 58.725 ;
     RECT  2.16 58.995 19.44 59.265 ;
     RECT  2.16 59.535 19.44 59.805 ;
     RECT  2.16 60.075 19.44 60.345 ;
     RECT  2.16 60.615 19.44 60.885 ;
     RECT  2.16 61.155 19.44 61.425 ;
     RECT  2.16 61.695 19.44 61.965 ;
     RECT  2.16 62.235 19.44 62.505 ;
     RECT  2.16 62.775 19.44 63.045 ;
     RECT  2.16 63.315 19.44 63.585 ;
     RECT  2.16 63.855 19.44 64.125 ;
     RECT  2.16 64.395 19.44 64.665 ;
     RECT  2.16 64.935 19.44 65.205 ;
     RECT  2.16 65.475 19.44 65.745 ;
     RECT  2.16 66.015 19.44 66.285 ;
     RECT  2.16 66.555 19.44 66.825 ;
     RECT  2.16 67.095 19.44 67.365 ;
     RECT  2.16 67.635 19.44 67.905 ;
     RECT  2.16 68.175 19.44 68.445 ;
     RECT  2.16 68.715 19.44 68.985 ;
     RECT  2.16 69.255 19.44 69.525 ;
     RECT  2.16 69.795 19.44 70.065 ;
     RECT  2.16 70.335 19.44 70.605 ;
     RECT  2.16 70.875 19.44 71.145 ;
     RECT  2.16 71.415 19.44 71.685 ;
     RECT  2.16 71.955 19.44 72.225 ;
     RECT  2.16 72.495 19.44 72.765 ;
     RECT  2.16 73.035 19.44 73.305 ;
     RECT  2.16 73.575 19.44 73.845 ;
     RECT  2.16 74.115 19.44 74.385 ;
     RECT  2.16 74.655 19.44 74.925 ;
     RECT  2.16 75.195 19.44 75.465 ;
     RECT  2.16 75.735 19.44 76.005 ;
     RECT  2.16 76.275 19.44 76.545 ;
     RECT  2.16 76.815 19.44 77.085 ;
     RECT  2.16 77.355 19.44 77.625 ;
     RECT  2.16 77.895 19.44 78.165 ;
     RECT  2.16 78.435 19.44 78.705 ;
     RECT  2.16 78.975 19.44 79.245 ;
     RECT  2.16 79.515 19.44 79.785 ;
     RECT  2.16 80.055 19.44 80.325 ;
     RECT  2.16 80.595 19.44 80.865 ;
     RECT  2.16 81.135 19.44 81.405 ;
     RECT  2.16 81.675 19.44 81.945 ;
     RECT  2.16 82.215 19.44 82.485 ;
     RECT  2.16 82.755 19.44 83.025 ;
     RECT  2.16 83.295 19.44 83.565 ;
     RECT  2.16 83.835 19.44 84.105 ;
     RECT  2.16 84.375 19.44 84.645 ;
     RECT  2.16 84.915 19.44 85.185 ;
     RECT  2.16 85.455 19.44 85.725 ;
     RECT  2.16 85.995 19.44 86.265 ;
     RECT  2.16 86.535 19.44 86.805 ;
     RECT  2.16 87.075 19.44 87.345 ;
     RECT  2.16 87.615 19.44 87.885 ;
     RECT  2.16 88.155 19.44 88.425 ;
     RECT  2.16 88.695 19.44 88.965 ;
     RECT  2.16 89.235 19.44 89.505 ;
     RECT  2.16 89.775 19.44 90.045 ;
     RECT  2.16 90.315 19.44 90.585 ;
     RECT  2.16 90.855 19.44 91.125 ;
     RECT  2.16 91.395 19.44 91.665 ;
     RECT  2.16 91.935 19.44 92.205 ;
     RECT  2.16 92.475 19.44 92.745 ;
     RECT  2.16 93.015 19.44 93.285 ;
     RECT  2.16 93.555 19.44 93.825 ;
     RECT  2.16 94.095 19.44 94.365 ;
     RECT  2.16 94.635 19.44 94.905 ;
     RECT  2.16 95.175 19.44 95.445 ;
     RECT  2.16 95.715 19.44 95.985 ;
     RECT  2.16 96.255 19.44 96.525 ;
     RECT  2.16 96.795 19.44 97.065 ;
     RECT  2.16 97.335 19.44 97.605 ;
     RECT  2.16 97.875 19.44 98.145 ;
     RECT  2.16 98.415 19.44 98.685 ;
     RECT  2.16 98.955 19.44 99.225 ;
     RECT  2.16 99.495 19.44 99.765 ;
     RECT  2.16 100.035 19.44 100.305 ;
     RECT  2.16 100.575 19.44 100.845 ;
     RECT  2.16 101.115 19.44 101.385 ;
     RECT  2.16 101.655 19.44 101.925 ;
     RECT  2.16 102.195 19.44 102.465 ;
     RECT  2.16 102.735 19.44 103.005 ;
     RECT  2.16 103.275 19.44 103.545 ;
    LAYER M1 ;
     RECT  2.16 2.151 19.44 103.689 ;
    LAYER M2 ;
     RECT  0.139 4.158 0.175 4.176 ;
     RECT  0.139 18.126 0.175 18.72 ;
     RECT  0.139 65.916 0.175 65.934 ;
     RECT  0.139 84.816 0.175 84.834 ;
     RECT  0.139 85.896 0.175 86.454 ;
     RECT  0.139 89.406 0.175 89.424 ;
     RECT  0.139 90.216 0.175 90.954 ;
     RECT  0.175 4.158 0.211 4.644 ;
     RECT  0.139 16.506 0.499 16.524 ;
     RECT  0.139 67.176 0.499 68.364 ;
     RECT  0.139 5.976 0.535 5.994 ;
     RECT  0.175 6.786 0.535 6.804 ;
     RECT  0.139 7.938 0.535 8.532 ;
     RECT  0.499 9.558 0.535 9.576 ;
     RECT  0.139 15.696 0.535 15.714 ;
     RECT  0.499 16.506 0.535 16.974 ;
     RECT  0.499 26.568 0.535 26.586 ;
     RECT  0.175 28.836 0.535 28.854 ;
     RECT  0.499 31.086 0.535 31.104 ;
     RECT  0.499 32.274 0.535 32.292 ;
     RECT  0.499 34.938 0.535 34.956 ;
     RECT  0.139 40.374 0.535 40.392 ;
     RECT  0.499 43.542 0.535 43.56 ;
     RECT  0.499 46.548 0.535 46.566 ;
     RECT  0.139 53.838 0.535 54.594 ;
     RECT  0.175 60.858 0.535 60.876 ;
     RECT  0.139 62.676 0.535 62.694 ;
     RECT  0.499 67.176 0.535 69.084 ;
     RECT  0.139 75.708 0.535 75.726 ;
     RECT  0.175 84.816 0.535 86.454 ;
     RECT  0.139 100.278 0.535 100.296 ;
     RECT  0.139 101.286 0.535 101.304 ;
     RECT  0.535 93.456 2.047 93.474 ;
     RECT  0.535 94.644 2.047 94.662 ;
     RECT  0.211 4.158 2.16 5.184 ;
     RECT  0.535 5.976 2.16 6.804 ;
     RECT  0.535 7.668 2.16 8.532 ;
     RECT  0.535 9.558 2.16 9.954 ;
     RECT  0.535 11.178 2.16 11.934 ;
     RECT  0.535 12.996 2.16 13.014 ;
     RECT  0.535 15.696 2.16 16.974 ;
     RECT  0.175 18.126 2.16 19.224 ;
     RECT  0.535 21.636 2.16 21.654 ;
     RECT  0.535 25.416 2.16 28.854 ;
     RECT  0.535 30.852 2.16 31.104 ;
     RECT  0.535 32.274 2.16 33.534 ;
     RECT  0.535 34.668 2.16 35.154 ;
     RECT  0.535 36.216 2.16 36.882 ;
     RECT  0.139 38.106 2.16 38.124 ;
     RECT  0.535 39.726 2.16 40.392 ;
     RECT  0.535 41.418 2.16 42.714 ;
     RECT  0.535 43.542 2.16 44.334 ;
     RECT  0.535 45.468 2.16 45.486 ;
     RECT  0.535 46.548 2.16 48.114 ;
     RECT  0.139 49.518 2.16 49.536 ;
     RECT  0.535 51.714 2.16 52.236 ;
     RECT  0.535 53.838 2.16 55.206 ;
     RECT  0.535 57.348 2.16 57.366 ;
     RECT  0.535 60.858 2.16 61.452 ;
     RECT  0.535 62.586 2.16 62.694 ;
     RECT  0.535 64.944 2.16 64.962 ;
     RECT  0.175 65.754 2.16 65.934 ;
     RECT  0.535 67.176 2.16 69.246 ;
     RECT  0.139 70.416 2.16 70.434 ;
     RECT  0.535 73.278 2.16 73.296 ;
     RECT  0.139 74.088 2.16 74.106 ;
     RECT  0.535 75.708 2.16 75.762 ;
     RECT  0.535 77.868 2.16 78.39 ;
     RECT  0.175 80.136 2.16 80.154 ;
     RECT  0.139 81.306 2.16 81.774 ;
     RECT  0.139 82.566 2.16 83.214 ;
     RECT  0.535 84.348 2.16 86.454 ;
     RECT  0.535 88.506 2.16 88.524 ;
     RECT  0.175 89.406 2.16 91.314 ;
     RECT  2.047 93.456 2.16 94.662 ;
     RECT  0.535 96.156 2.16 96.174 ;
     RECT  0.535 97.848 2.16 97.866 ;
     RECT  0.139 99.396 2.16 99.414 ;
     RECT  0.535 100.278 2.16 101.304 ;
     RECT  0.139 102.366 2.16 102.384 ;
     RECT  2.16 2.151 15.475 103.689 ;
     RECT  15.475 2.151 18.419 103.734 ;
     RECT  18.419 2.151 19.44 103.689 ;
     RECT  19.44 6.12 19.895 103.608 ;
     RECT  19.895 6.12 19.931 39.276 ;
     RECT  19.895 40.14 19.931 70.092 ;
     RECT  19.895 70.884 19.931 103.608 ;
     RECT  19.44 4.968 19.967 5.058 ;
     RECT  19.931 43.308 19.967 70.056 ;
     RECT  19.931 82.728 19.967 103.608 ;
     RECT  19.931 24.408 20.183 34.146 ;
     RECT  19.931 40.14 20.183 42.282 ;
     RECT  19.931 71.73 20.183 73.296 ;
     RECT  19.967 43.308 20.219 47.448 ;
     RECT  19.931 10.098 20.255 14.706 ;
     RECT  20.219 45.738 20.255 47.448 ;
     RECT  19.967 48.24 20.255 70.056 ;
     RECT  19.931 70.92 20.255 70.974 ;
     RECT  19.967 84.15 20.255 103.608 ;
     RECT  19.931 6.66 20.291 7.416 ;
     RECT  20.255 11.448 20.291 14.706 ;
     RECT  20.183 26.1 20.291 34.146 ;
     RECT  20.183 40.338 20.291 42.282 ;
     RECT  20.255 48.24 20.291 62.262 ;
     RECT  20.255 63.018 20.291 70.056 ;
     RECT  19.931 74.088 20.291 75.996 ;
     RECT  19.931 76.788 20.291 81.936 ;
     RECT  20.255 84.15 20.291 85.446 ;
     RECT  20.255 86.238 20.291 103.608 ;
     RECT  19.931 15.498 20.327 19.566 ;
     RECT  19.931 8.208 20.399 9.306 ;
     RECT  20.291 13.068 20.399 14.706 ;
     RECT  20.327 15.498 20.399 19.296 ;
     RECT  20.255 45.738 20.399 46.908 ;
     RECT  20.291 48.438 20.399 57.906 ;
     RECT  20.291 76.788 20.399 80.586 ;
     RECT  20.291 84.348 20.399 85.446 ;
     RECT  20.291 6.822 20.435 7.416 ;
     RECT  20.399 8.208 20.435 9.036 ;
     RECT  20.255 10.098 20.435 10.656 ;
     RECT  20.399 13.068 20.435 13.896 ;
     RECT  20.399 15.498 20.435 17.406 ;
     RECT  20.399 18.198 20.435 19.296 ;
     RECT  19.931 20.358 20.435 23.616 ;
     RECT  20.183 24.408 20.435 25.308 ;
     RECT  20.291 26.298 20.435 34.146 ;
     RECT  19.931 35.28 20.435 38.196 ;
     RECT  20.291 40.338 20.435 40.356 ;
     RECT  20.291 41.148 20.435 42.282 ;
     RECT  20.219 43.308 20.435 44.946 ;
     RECT  20.399 45.738 20.435 45.756 ;
     RECT  20.399 48.438 20.435 49.806 ;
     RECT  20.399 50.868 20.435 57.906 ;
     RECT  20.291 61.128 20.435 62.262 ;
     RECT  20.291 63.018 20.435 64.926 ;
     RECT  20.291 65.718 20.435 66.546 ;
     RECT  20.291 67.608 20.435 70.056 ;
     RECT  20.183 72.198 20.435 73.296 ;
     RECT  20.291 74.088 20.435 75.186 ;
     RECT  20.291 75.978 20.435 75.996 ;
     RECT  20.399 76.788 20.435 80.316 ;
     RECT  20.291 81.378 20.435 81.936 ;
     RECT  19.967 82.728 20.435 83.052 ;
     RECT  20.399 84.348 20.435 84.636 ;
     RECT  20.291 86.238 20.435 87.606 ;
     RECT  20.291 88.398 20.435 103.608 ;
     RECT  20.399 46.584 20.471 46.908 ;
     RECT  20.435 54.648 20.471 54.936 ;
     RECT  20.435 86.778 20.471 87.606 ;
     RECT  20.435 94.032 20.471 95.166 ;
     RECT  20.435 98.73 20.471 98.748 ;
     RECT  20.435 6.822 20.507 6.84 ;
     RECT  20.435 8.208 20.507 8.226 ;
     RECT  20.435 10.098 20.507 10.116 ;
     RECT  20.291 11.448 20.507 12.312 ;
     RECT  20.435 13.338 20.507 13.356 ;
     RECT  20.399 14.688 20.507 14.706 ;
     RECT  20.435 15.606 20.507 16.974 ;
     RECT  20.435 18.468 20.507 19.134 ;
     RECT  20.435 21.744 20.507 23.31 ;
     RECT  20.435 24.948 20.507 25.308 ;
     RECT  20.435 26.64 20.507 27.9 ;
     RECT  20.435 29.268 20.507 29.286 ;
     RECT  20.435 30.078 20.507 32.49 ;
     RECT  20.435 33.588 20.507 34.146 ;
     RECT  20.435 35.28 20.507 36.576 ;
     RECT  20.435 37.368 20.507 37.62 ;
     RECT  19.931 38.988 20.507 39.276 ;
     RECT  20.435 42.228 20.507 42.282 ;
     RECT  20.435 43.308 20.507 44.064 ;
     RECT  20.435 44.928 20.507 44.946 ;
     RECT  20.471 46.62 20.507 46.908 ;
     RECT  20.435 48.708 20.507 49.266 ;
     RECT  20.435 50.868 20.507 52.578 ;
     RECT  20.435 53.568 20.507 53.856 ;
     RECT  20.471 54.918 20.507 54.936 ;
     RECT  20.435 55.998 20.507 57.906 ;
     RECT  20.291 58.968 20.507 60.066 ;
     RECT  20.435 61.668 20.507 62.262 ;
     RECT  20.435 63.018 20.507 64.656 ;
     RECT  20.435 68.148 20.507 68.94 ;
     RECT  20.435 72.468 20.507 73.296 ;
     RECT  20.435 74.592 20.507 75.186 ;
     RECT  20.435 76.788 20.507 77.886 ;
     RECT  20.435 78.642 20.507 79.236 ;
     RECT  20.435 81.918 20.507 81.936 ;
     RECT  20.435 82.8 20.507 83.052 ;
     RECT  20.399 85.428 20.507 85.446 ;
     RECT  20.471 87.12 20.507 87.606 ;
     RECT  20.435 88.398 20.507 88.416 ;
     RECT  20.435 89.208 20.507 90.846 ;
     RECT  20.471 94.032 20.507 94.05 ;
     RECT  20.471 94.95 20.507 95.166 ;
     RECT  20.435 96.228 20.507 97.128 ;
     RECT  20.435 100.548 20.507 100.566 ;
     RECT  20.435 102.51 20.507 102.798 ;
     RECT  20.507 11.952 20.543 12.312 ;
     RECT  20.507 46.62 20.543 46.638 ;
     RECT  20.435 66.528 20.543 66.546 ;
     RECT  20.507 102.51 20.543 102.528 ;
     RECT  20.435 103.59 20.543 103.608 ;
     RECT  20.507 59.238 21.407 59.364 ;
     RECT  20.507 63.252 21.407 63.846 ;
     RECT  19.967 5.04 21.443 5.058 ;
     RECT  20.543 11.952 21.443 11.97 ;
     RECT  20.507 16.308 21.443 16.326 ;
     RECT  20.507 19.116 21.443 19.134 ;
     RECT  20.507 21.744 21.443 21.762 ;
     RECT  20.507 25.29 21.443 25.308 ;
     RECT  20.507 27.342 21.443 27.9 ;
     RECT  20.507 30.15 21.443 30.168 ;
     RECT  20.435 41.148 21.443 41.166 ;
     RECT  20.507 42.264 21.443 42.282 ;
     RECT  20.507 52.56 21.443 52.578 ;
     RECT  20.507 56.61 21.443 57.204 ;
     RECT  21.407 59.346 21.443 59.364 ;
     RECT  20.507 62.244 21.443 62.262 ;
     RECT  21.407 63.36 21.443 63.846 ;
     RECT  20.255 70.956 21.443 70.974 ;
     RECT  20.507 77.094 21.443 77.112 ;
     RECT  20.507 82.8 21.443 82.818 ;
     RECT  20.435 91.98 21.443 91.998 ;
     RECT  20.507 97.11 21.443 97.128 ;
     RECT  20.435 99.738 21.443 99.756 ;
    LAYER M3 ;
     RECT  2.415 2.143 2.505 2.413 ;
     RECT  5.115 2.143 5.205 2.413 ;
     RECT  7.815 2.143 7.905 2.413 ;
     RECT  10.515 2.143 10.605 2.413 ;
     RECT  13.215 2.143 13.305 2.413 ;
     RECT  15.915 2.143 16.005 2.413 ;
     RECT  18.615 2.143 18.705 2.413 ;
     RECT  2.415 2.413 2.697 3.811 ;
     RECT  2.304 3.811 2.697 3.955 ;
     RECT  2.304 3.955 3.258 4.351 ;
     RECT  0.144 4.153 0.162 4.621 ;
     RECT  18.615 2.413 18.897 4.657 ;
     RECT  17.892 4.657 18.897 4.765 ;
     RECT  2.304 4.351 3.618 4.801 ;
     RECT  17.892 4.765 19.422 4.963 ;
     RECT  0.144 4.621 0.198 5.161 ;
     RECT  10.515 2.413 10.797 5.233 ;
     RECT  17.892 4.963 19.962 5.233 ;
     RECT  2.304 4.801 4.014 5.309 ;
     RECT  21.42 5.035 21.438 5.309 ;
     RECT  14.832 5.233 14.85 5.341 ;
     RECT  15.915 2.413 16.197 5.341 ;
     RECT  2.34 5.309 4.014 5.369 ;
     RECT  15.915 5.341 16.686 5.431 ;
     RECT  17.64 5.233 19.962 5.431 ;
     RECT  2.415 5.369 4.014 5.611 ;
     RECT  5.115 2.413 5.397 5.611 ;
     RECT  15.915 5.431 19.962 5.693 ;
     RECT  13.215 2.413 13.497 5.701 ;
     RECT  14.832 5.341 14.886 5.701 ;
     RECT  14.832 5.701 15.03 5.773 ;
     RECT  2.415 5.611 5.397 5.801 ;
     RECT  14.832 5.773 15.066 5.809 ;
     RECT  15.915 5.693 19.926 5.809 ;
     RECT  6.66 5.701 6.75 5.845 ;
     RECT  13.215 5.701 13.878 5.845 ;
     RECT  14.832 5.809 19.926 5.845 ;
     RECT  10.515 5.233 10.854 5.873 ;
     RECT  6.66 5.845 6.822 5.909 ;
     RECT  2.415 5.801 3.294 5.999 ;
     RECT  6.804 5.909 6.822 6.071 ;
     RECT  13.215 5.845 19.926 6.077 ;
     RECT  12.276 5.881 12.294 6.079 ;
     RECT  0.144 5.161 0.234 6.151 ;
     RECT  12.24 6.079 12.294 6.151 ;
     RECT  13.215 6.077 18.897 6.151 ;
     RECT  2.415 5.999 3.186 6.232 ;
     RECT  12.24 6.151 18.897 6.349 ;
     RECT  19.908 6.077 19.926 6.413 ;
     RECT  2.412 6.232 3.186 6.427 ;
     RECT  6.84 6.421 6.858 6.538 ;
     RECT  12.06 6.349 18.897 6.547 ;
     RECT  20.268 6.427 20.286 6.619 ;
     RECT  0.144 6.151 0.558 6.653 ;
     RECT  11.952 6.547 18.897 6.691 ;
     RECT  6.84 6.538 6.894 6.719 ;
     RECT  11.844 6.691 18.897 6.809 ;
     RECT  12.06 6.809 18.897 6.811 ;
     RECT  2.304 6.427 3.186 6.817 ;
     RECT  0.144 6.653 0.198 6.845 ;
     RECT  20.268 6.619 20.502 6.845 ;
     RECT  2.304 6.817 3.258 6.961 ;
     RECT  4.176 5.801 5.397 6.961 ;
     RECT  6.84 6.719 6.858 6.961 ;
     RECT  0.18 6.845 0.198 7.037 ;
     RECT  6.804 6.961 6.858 7.151 ;
     RECT  12.06 6.811 19.422 7.187 ;
     RECT  10.515 5.873 10.797 7.321 ;
     RECT  12.06 7.187 19.026 7.421 ;
     RECT  20.268 6.845 20.43 7.579 ;
     RECT  19.908 7.579 20.43 7.771 ;
     RECT  0.54 7.663 0.558 7.933 ;
     RECT  2.304 6.961 5.397 7.933 ;
     RECT  6.84 7.151 6.858 7.961 ;
     RECT  10.515 7.321 10.854 8.005 ;
     RECT  2.232 7.933 5.397 8.069 ;
     RECT  10.515 8.005 10.926 8.159 ;
     RECT  19.908 7.771 20.502 8.231 ;
     RECT  0.144 7.933 0.558 8.381 ;
     RECT  12.06 7.421 18.897 8.429 ;
     RECT  0.144 8.381 0.162 8.765 ;
     RECT  12.888 8.429 18.897 8.969 ;
     RECT  12.888 8.969 13.734 9.041 ;
     RECT  19.908 8.231 20.43 9.041 ;
     RECT  12.888 9.041 13.698 9.101 ;
     RECT  2.304 8.069 5.397 9.149 ;
     RECT  19.908 9.041 20.394 9.311 ;
     RECT  12.06 8.429 12.078 9.391 ;
     RECT  12.888 9.101 13.497 9.391 ;
     RECT  10.515 8.159 10.854 9.481 ;
     RECT  19.908 9.311 20.286 9.499 ;
     RECT  10.515 9.481 10.89 9.581 ;
     RECT  0.504 9.553 0.522 9.661 ;
     RECT  14.508 8.969 18.897 9.691 ;
     RECT  19.872 9.499 20.286 9.691 ;
     RECT  12.06 9.391 13.497 9.823 ;
     RECT  2.415 9.149 5.397 9.883 ;
     RECT  12.06 9.823 13.554 9.883 ;
     RECT  14.508 9.691 20.286 9.923 ;
     RECT  12.06 9.883 13.698 9.931 ;
     RECT  14.508 9.923 19.026 9.931 ;
     RECT  11.844 9.931 19.026 10.049 ;
     RECT  19.872 9.923 20.286 10.075 ;
     RECT  0.504 9.661 0.558 10.109 ;
     RECT  19.872 10.075 20.502 10.121 ;
     RECT  6.84 8.977 6.858 10.157 ;
     RECT  2.412 9.883 5.397 10.267 ;
     RECT  9.756 10.267 9.774 10.355 ;
     RECT  10.515 9.581 10.854 10.471 ;
     RECT  12.06 10.049 19.026 10.589 ;
     RECT  2.304 10.267 5.397 10.661 ;
     RECT  13.032 10.589 19.026 10.661 ;
     RECT  6.804 10.291 6.822 10.733 ;
     RECT  19.872 10.121 20.43 10.877 ;
     RECT  9.864 10.471 10.854 11.137 ;
     RECT  9.864 11.137 10.962 11.237 ;
     RECT  2.304 10.661 4.338 11.273 ;
     RECT  9.864 11.237 10.926 11.309 ;
     RECT  19.908 10.877 20.43 11.419 ;
     RECT  12.096 10.589 12.114 11.443 ;
     RECT  12.096 11.443 12.258 11.515 ;
     RECT  13.032 10.661 18.897 11.515 ;
     RECT  12.096 11.515 18.897 11.551 ;
     RECT  6.84 11.641 6.858 11.741 ;
     RECT  19.908 11.419 20.502 11.803 ;
     RECT  11.844 11.551 18.897 11.911 ;
     RECT  11.844 11.911 19.062 11.981 ;
     RECT  0.54 10.109 0.558 12.029 ;
     RECT  21.42 11.947 21.438 12.029 ;
     RECT  9.864 11.309 10.797 12.091 ;
     RECT  2.304 11.273 4.086 12.181 ;
     RECT  19.908 11.803 20.538 12.317 ;
     RECT  9.864 12.091 10.926 12.361 ;
     RECT  11.844 11.981 18.897 12.361 ;
     RECT  0.144 12.379 0.162 12.509 ;
     RECT  5.115 10.661 5.397 12.523 ;
     RECT  5.076 12.523 5.397 12.631 ;
     RECT  9.864 12.361 18.897 12.721 ;
     RECT  4.896 12.631 5.397 12.749 ;
     RECT  2.304 12.181 4.122 12.757 ;
     RECT  6.768 12.793 6.786 12.929 ;
     RECT  9.864 12.721 19.026 13.019 ;
     RECT  6.84 12.991 6.858 13.091 ;
     RECT  12.888 13.019 19.026 13.091 ;
     RECT  12.888 13.091 18.954 13.163 ;
     RECT  0.54 12.991 0.558 13.181 ;
     RECT  2.304 12.757 4.194 13.289 ;
     RECT  19.908 12.317 20.43 13.333 ;
     RECT  19.908 13.333 20.502 13.373 ;
     RECT  9.864 13.019 10.926 13.433 ;
     RECT  12.924 13.163 18.954 13.559 ;
     RECT  14.508 13.559 18.954 13.703 ;
     RECT  19.908 13.373 20.43 13.901 ;
     RECT  2.304 13.289 4.158 13.973 ;
     RECT  6.912 13.873 6.93 13.973 ;
     RECT  11.7 13.019 12.114 13.981 ;
     RECT  12.924 13.559 13.698 13.981 ;
     RECT  5.004 12.749 5.397 14.171 ;
     RECT  6.768 14.071 6.858 14.242 ;
     RECT  9.864 13.433 10.854 14.251 ;
     RECT  14.544 13.703 18.954 14.299 ;
     RECT  11.7 13.981 13.698 14.377 ;
     RECT  14.544 14.299 19.026 14.441 ;
     RECT  19.908 13.901 20.394 14.491 ;
     RECT  11.7 14.377 13.734 14.521 ;
     RECT  14.544 14.441 18.954 14.521 ;
     RECT  9.864 14.251 10.926 14.549 ;
     RECT  6.732 14.242 6.858 14.639 ;
     RECT  11.7 14.521 18.954 14.639 ;
     RECT  19.836 14.491 20.394 14.683 ;
     RECT  9.864 14.549 10.797 14.791 ;
     RECT  12.096 14.639 18.954 14.819 ;
     RECT  2.304 13.973 4.014 14.881 ;
     RECT  9.54 14.791 10.797 14.909 ;
     RECT  12.924 14.819 18.954 14.909 ;
     RECT  19.836 14.683 20.502 14.981 ;
     RECT  6.912 14.917 6.93 15.089 ;
     RECT  12.924 14.909 18.897 15.179 ;
     RECT  14.508 15.179 18.897 15.323 ;
     RECT  19.872 14.981 20.502 15.323 ;
     RECT  2.304 14.881 4.374 15.331 ;
     RECT  5.115 14.171 5.397 15.331 ;
     RECT  9.864 14.909 10.797 15.331 ;
     RECT  12.924 15.179 13.734 15.389 ;
     RECT  12.096 14.819 12.114 15.529 ;
     RECT  12.06 15.529 12.114 15.601 ;
     RECT  12.924 15.389 13.698 15.601 ;
     RECT  9.864 15.331 10.89 15.691 ;
     RECT  11.7 15.601 13.698 15.719 ;
     RECT  0.144 15.691 0.162 16.033 ;
     RECT  9.864 15.691 10.926 16.033 ;
     RECT  11.988 15.719 13.698 16.141 ;
     RECT  14.544 15.323 18.897 16.141 ;
     RECT  2.304 15.331 5.397 16.219 ;
     RECT  6.876 16.033 6.894 16.231 ;
     RECT  2.268 16.219 5.397 16.259 ;
     RECT  21.42 15.835 21.438 16.331 ;
     RECT  2.304 16.259 5.397 16.367 ;
     RECT  20.232 15.323 20.502 16.411 ;
     RECT  6.84 16.231 6.894 16.529 ;
     RECT  9.864 16.033 10.962 16.529 ;
     RECT  6.84 16.529 6.858 16.609 ;
     RECT  6.804 16.609 6.858 16.709 ;
     RECT  11.988 16.141 18.897 16.771 ;
     RECT  20.16 16.411 20.502 16.795 ;
     RECT  6.804 16.709 6.822 16.871 ;
     RECT  11.772 16.771 18.897 16.951 ;
     RECT  19.908 16.795 20.502 16.979 ;
     RECT  11.7 16.951 18.954 17.069 ;
     RECT  2.34 16.367 5.397 17.105 ;
     RECT  0.144 16.033 0.558 17.213 ;
     RECT  2.34 17.105 3.438 17.221 ;
     RECT  9.864 16.529 10.797 17.311 ;
     RECT  9.864 17.311 10.854 17.419 ;
     RECT  19.908 16.979 20.43 17.483 ;
     RECT  12.06 17.069 18.954 17.609 ;
     RECT  4.572 17.105 5.397 17.617 ;
     RECT  12.06 17.609 12.078 17.651 ;
     RECT  4.572 17.617 5.418 17.753 ;
     RECT  0.144 17.213 0.522 17.981 ;
     RECT  2.304 17.221 3.438 17.995 ;
     RECT  4.572 17.753 5.397 17.995 ;
     RECT  20.16 17.483 20.43 18.023 ;
     RECT  2.304 17.995 3.546 18.031 ;
     RECT  4.284 17.995 5.397 18.031 ;
     RECT  20.412 18.023 20.43 18.139 ;
     RECT  2.304 18.031 5.397 18.185 ;
     RECT  12.924 17.609 18.954 18.193 ;
     RECT  9.864 17.419 11.178 18.229 ;
     RECT  9.864 18.229 11.322 18.301 ;
     RECT  9.864 18.301 11.718 18.419 ;
     RECT  12.924 18.193 19.026 18.523 ;
     RECT  12.06 18.535 12.078 18.571 ;
     RECT  12.924 18.523 19.422 18.571 ;
     RECT  12.06 18.571 19.422 18.605 ;
     RECT  20.412 18.139 20.502 18.749 ;
     RECT  2.415 18.185 5.397 18.907 ;
     RECT  6.912 18.427 6.93 18.931 ;
     RECT  6.768 18.931 6.93 18.959 ;
     RECT  12.096 18.605 19.422 19.067 ;
     RECT  20.412 18.749 20.43 19.075 ;
     RECT  6.768 18.959 6.858 19.102 ;
     RECT  12.096 19.067 18.954 19.103 ;
     RECT  21.42 17.755 21.438 19.139 ;
     RECT  0.144 17.981 0.162 19.201 ;
     RECT  12.096 19.103 18.897 19.235 ;
     RECT  0.144 19.201 0.198 19.325 ;
     RECT  6.732 19.102 6.858 19.373 ;
     RECT  9.864 18.419 10.854 19.381 ;
     RECT  0.18 19.325 0.198 19.517 ;
     RECT  6.768 19.373 6.858 19.643 ;
     RECT  12.312 19.235 18.897 19.769 ;
     RECT  12.312 19.769 13.734 19.841 ;
     RECT  12.312 19.841 13.698 19.963 ;
     RECT  14.544 19.769 18.897 20.011 ;
     RECT  19.908 19.075 20.43 20.011 ;
     RECT  9.864 19.381 10.926 20.075 ;
     RECT  9.936 20.075 10.926 20.191 ;
     RECT  14.544 20.011 20.43 20.309 ;
     RECT  2.304 18.907 5.397 20.443 ;
     RECT  9.936 20.191 11.322 20.489 ;
     RECT  12.096 19.963 13.698 20.587 ;
     RECT  6.84 19.643 6.858 20.623 ;
     RECT  6.84 20.623 6.93 20.731 ;
     RECT  11.808 20.587 13.698 20.731 ;
     RECT  14.544 20.309 18.954 20.731 ;
     RECT  6.768 20.731 6.93 20.759 ;
     RECT  9.936 20.489 10.926 20.759 ;
     RECT  2.268 20.443 5.397 20.849 ;
     RECT  11.808 20.731 18.954 20.849 ;
     RECT  0.144 20.827 0.162 20.875 ;
     RECT  6.768 20.759 6.858 20.921 ;
     RECT  0.144 20.875 0.234 20.957 ;
     RECT  0.216 20.957 0.234 21.053 ;
     RECT  2.304 20.849 5.397 21.235 ;
     RECT  19.908 20.309 20.43 21.533 ;
     RECT  11.844 20.849 18.954 21.541 ;
     RECT  2.304 21.235 5.49 21.569 ;
     RECT  6.804 20.921 6.858 21.569 ;
     RECT  11.844 21.541 19.314 21.659 ;
     RECT  21.42 21.595 21.438 21.767 ;
     RECT  9.936 20.759 10.797 21.811 ;
     RECT  2.304 21.569 5.397 21.929 ;
     RECT  2.304 21.929 3.222 22.171 ;
     RECT  11.844 21.659 18.897 22.199 ;
     RECT  20.448 21.787 20.502 22.363 ;
     RECT  2.268 22.171 3.222 22.379 ;
     RECT  0.54 21.631 0.558 22.589 ;
     RECT  6.804 22.549 6.822 22.649 ;
     RECT  2.304 22.379 3.222 22.739 ;
     RECT  4.032 21.929 5.397 22.739 ;
     RECT  2.376 22.739 3.222 22.855 ;
     RECT  9.936 21.811 10.926 22.855 ;
     RECT  4.644 22.739 5.397 22.919 ;
     RECT  12.096 22.199 13.662 23.089 ;
     RECT  9.936 22.855 11.214 23.161 ;
     RECT  12.096 23.089 13.698 23.161 ;
     RECT  14.436 22.199 18.897 23.161 ;
     RECT  9.936 23.161 11.25 23.315 ;
     RECT  6.84 23.161 6.858 23.351 ;
     RECT  19.908 22.363 20.502 23.357 ;
     RECT  12.096 23.161 18.897 23.359 ;
     RECT  19.908 23.357 20.43 23.359 ;
     RECT  9.936 23.315 10.962 23.459 ;
     RECT  2.376 22.855 3.906 23.515 ;
     RECT  12.096 23.359 20.43 23.557 ;
     RECT  11.808 23.557 20.43 23.597 ;
     RECT  2.304 23.515 3.906 23.791 ;
     RECT  4.896 22.919 5.397 23.791 ;
     RECT  11.952 23.597 20.43 23.819 ;
     RECT  0.216 23.707 0.234 23.885 ;
     RECT  6.804 23.431 6.822 23.891 ;
     RECT  6.84 24.205 6.858 24.241 ;
     RECT  12.528 23.819 20.43 24.359 ;
     RECT  6.84 24.241 6.894 24.431 ;
     RECT  6.876 24.431 6.894 24.503 ;
     RECT  14.508 24.359 20.43 24.503 ;
     RECT  12.528 24.359 13.698 24.509 ;
     RECT  12.528 24.509 13.554 24.571 ;
     RECT  14.544 24.503 20.43 24.653 ;
     RECT  18.615 24.653 20.43 24.667 ;
     RECT  2.304 23.791 5.397 24.859 ;
     RECT  18.615 24.667 20.502 24.893 ;
     RECT  18.615 24.893 18.954 24.899 ;
     RECT  19.872 24.893 20.502 24.971 ;
     RECT  2.232 24.859 5.397 24.989 ;
     RECT  19.872 24.971 20.178 25.007 ;
     RECT  12.096 24.571 13.554 25.243 ;
     RECT  9.936 23.459 10.926 25.249 ;
     RECT  21.42 25.051 21.438 25.313 ;
     RECT  12.096 25.243 13.698 25.321 ;
     RECT  14.544 24.653 17.874 25.321 ;
     RECT  9.936 25.249 11.178 25.439 ;
     RECT  6.84 25.411 6.858 25.681 ;
     RECT  12.096 25.321 17.874 25.717 ;
     RECT  19.908 25.007 20.178 25.819 ;
     RECT  6.84 25.681 6.93 25.861 ;
     RECT  11.772 25.717 17.874 25.861 ;
     RECT  18.615 24.899 18.897 25.861 ;
     RECT  9.936 25.439 10.962 25.979 ;
     RECT  11.772 25.861 18.897 25.979 ;
     RECT  6.84 25.861 7.002 26.087 ;
     RECT  11.844 25.979 18.897 26.141 ;
     RECT  11.844 26.141 13.734 26.189 ;
     RECT  19.908 25.819 20.43 26.392 ;
     RECT  2.415 24.989 5.397 26.395 ;
     RECT  9.936 25.979 10.926 26.401 ;
     RECT  14.544 26.141 18.897 26.401 ;
     RECT  2.304 26.395 5.397 26.519 ;
     RECT  0.54 25.411 0.558 26.563 ;
     RECT  19.872 26.392 20.43 26.587 ;
     RECT  6.804 26.365 6.822 26.591 ;
     RECT  9.864 26.401 10.926 26.627 ;
     RECT  19.872 26.587 20.502 26.627 ;
     RECT  14.544 26.401 18.954 26.635 ;
     RECT  19.908 26.627 20.502 26.663 ;
     RECT  14.544 26.635 18.99 26.671 ;
     RECT  9.864 26.627 10.854 26.789 ;
     RECT  14.544 26.671 19.134 26.789 ;
     RECT  19.908 26.663 20.286 26.861 ;
     RECT  11.844 26.189 13.698 26.941 ;
     RECT  14.544 26.789 18.954 26.941 ;
     RECT  0.504 26.563 0.558 27.005 ;
     RECT  11.844 26.941 18.954 27.389 ;
     RECT  11.844 27.389 18.897 27.481 ;
     RECT  2.415 26.519 5.397 27.547 ;
     RECT  19.944 26.861 20.286 27.739 ;
     RECT  9.936 26.789 10.854 27.949 ;
     RECT  11.7 27.481 18.897 27.949 ;
     RECT  21.42 27.337 21.438 27.965 ;
     RECT  2.304 27.547 5.397 28.157 ;
     RECT  2.415 28.157 5.397 28.291 ;
     RECT  19.908 27.739 20.286 28.315 ;
     RECT  9.936 27.949 18.897 28.409 ;
     RECT  2.415 28.291 5.454 28.481 ;
     RECT  6.84 27.679 6.858 28.481 ;
     RECT  0.54 27.005 0.558 28.541 ;
     RECT  19.908 28.315 20.43 28.751 ;
     RECT  20.232 28.751 20.43 28.823 ;
     RECT  11.844 28.409 18.897 28.831 ;
     RECT  0.18 28.831 0.198 28.891 ;
     RECT  11.844 28.831 19.134 28.949 ;
     RECT  2.415 28.481 5.397 28.985 ;
     RECT  2.415 28.985 4.158 29.083 ;
     RECT  20.412 28.823 20.43 29.263 ;
     RECT  0.144 28.891 0.198 29.309 ;
     RECT  20.412 29.263 20.502 29.309 ;
     RECT  12.888 28.949 19.134 29.335 ;
     RECT  9.936 28.409 10.926 29.399 ;
     RECT  2.304 29.083 4.158 29.489 ;
     RECT  12.888 29.335 19.422 29.501 ;
     RECT  20.412 29.309 20.43 29.659 ;
     RECT  11.844 28.949 12.078 29.759 ;
     RECT  0.144 29.309 0.162 29.789 ;
     RECT  9.936 29.399 10.854 29.867 ;
     RECT  12.888 29.501 18.897 29.903 ;
     RECT  19.908 29.659 20.43 29.903 ;
     RECT  12.06 29.759 12.078 29.911 ;
     RECT  20.268 29.903 20.43 30.043 ;
     RECT  21.42 30.145 21.438 30.269 ;
     RECT  2.304 29.489 4.05 30.271 ;
     RECT  4.896 28.985 5.397 30.271 ;
     RECT  12.06 29.911 12.438 30.685 ;
     RECT  13.215 29.903 18.897 30.685 ;
     RECT  20.268 30.043 20.502 30.811 ;
     RECT  0.54 30.847 0.558 31.081 ;
     RECT  2.304 30.271 5.397 31.379 ;
     RECT  9.936 29.867 10.797 31.423 ;
     RECT  12.06 30.685 18.897 31.531 ;
     RECT  2.34 31.379 5.397 31.559 ;
     RECT  11.7 31.531 19.098 31.649 ;
     RECT  19.908 30.811 20.502 31.721 ;
     RECT  9.936 31.423 10.926 32.099 ;
     RECT  2.412 31.559 5.397 32.341 ;
     RECT  6.84 30.811 6.858 32.369 ;
     RECT  12.06 31.649 18.954 32.495 ;
     RECT  12.06 32.495 18.918 32.701 ;
     RECT  20.412 31.721 20.502 32.731 ;
     RECT  0.504 31.081 0.558 32.765 ;
     RECT  19.908 32.731 20.502 32.873 ;
     RECT  11.772 32.701 18.918 32.999 ;
     RECT  11.772 32.999 12.078 33.035 ;
     RECT  12.888 32.999 18.918 33.143 ;
     RECT  12.924 33.143 18.918 33.304 ;
     RECT  9.936 32.099 10.797 33.313 ;
     RECT  2.304 32.341 5.397 33.341 ;
     RECT  12.924 33.304 19.422 33.533 ;
     RECT  9.936 33.313 10.854 33.655 ;
     RECT  20.412 32.873 20.502 33.691 ;
     RECT  20.232 33.691 20.502 33.883 ;
     RECT  0.54 32.765 0.558 33.917 ;
     RECT  12.06 33.035 12.078 33.931 ;
     RECT  12.924 33.533 18.897 33.931 ;
     RECT  6.804 33.853 6.822 34.079 ;
     RECT  19.908 33.883 20.502 34.151 ;
     RECT  19.908 34.151 19.926 34.267 ;
     RECT  12.06 33.931 18.897 34.357 ;
     RECT  11.988 34.357 18.897 34.393 ;
     RECT  2.304 33.341 4.158 34.457 ;
     RECT  19.872 34.267 19.926 34.459 ;
     RECT  2.415 34.457 4.158 34.501 ;
     RECT  5.115 33.341 5.397 34.501 ;
     RECT  11.88 34.393 18.897 34.501 ;
     RECT  9.936 33.655 10.926 34.529 ;
     RECT  11.844 34.501 18.897 34.619 ;
     RECT  6.84 34.465 6.858 34.627 ;
     RECT  12.816 34.619 18.897 34.637 ;
     RECT  12.816 34.637 17.73 34.685 ;
     RECT  11.988 34.619 12.078 34.691 ;
     RECT  6.84 34.627 6.93 34.763 ;
     RECT  12.888 34.685 17.73 34.763 ;
     RECT  18.468 34.637 18.897 34.771 ;
     RECT  2.415 34.501 5.397 34.889 ;
     RECT  11.988 34.691 12.006 34.889 ;
     RECT  0.54 34.663 0.558 34.933 ;
     RECT  0.504 34.933 0.558 34.939 ;
     RECT  18.468 34.771 18.99 35.041 ;
     RECT  19.836 34.459 19.926 35.041 ;
     RECT  0.144 34.939 0.558 35.069 ;
     RECT  2.415 34.889 4.122 35.069 ;
     RECT  2.415 35.069 4.05 35.227 ;
     RECT  18.468 35.041 19.926 35.227 ;
     RECT  2.376 35.227 4.05 35.275 ;
     RECT  2.304 35.275 4.05 35.401 ;
     RECT  2.268 35.401 4.05 35.429 ;
     RECT  0.504 35.069 0.558 35.453 ;
     RECT  9.936 34.529 10.854 35.581 ;
     RECT  12.096 35.509 12.114 35.581 ;
     RECT  12.924 34.763 17.73 35.581 ;
     RECT  18.468 35.227 20.502 35.581 ;
     RECT  2.268 35.429 3.114 35.645 ;
     RECT  4.032 35.429 4.05 35.815 ;
     RECT  5.115 34.889 5.397 35.815 ;
     RECT  0.504 35.453 0.522 35.837 ;
     RECT  12.096 35.581 20.502 35.843 ;
     RECT  12.096 35.843 19.134 35.879 ;
     RECT  4.032 35.815 5.397 35.969 ;
     RECT  12.096 35.879 18.954 36.269 ;
     RECT  12.096 36.269 18.897 36.379 ;
     RECT  12.024 36.379 18.897 36.419 ;
     RECT  6.84 34.763 6.858 36.517 ;
     RECT  19.908 35.843 20.502 36.605 ;
     RECT  6.696 36.517 6.858 36.653 ;
     RECT  6.768 36.653 6.858 36.689 ;
     RECT  9.936 35.581 10.926 36.689 ;
     RECT  3.888 36.355 3.906 36.751 ;
     RECT  5.115 35.969 5.397 36.751 ;
     RECT  0.54 36.211 0.558 36.763 ;
     RECT  2.304 35.645 3.114 36.823 ;
     RECT  3.888 36.751 5.397 36.823 ;
     RECT  0.144 36.763 0.558 36.893 ;
     RECT  19.908 36.605 20.43 37.147 ;
     RECT  12.096 36.419 18.897 37.165 ;
     RECT  0.54 36.893 0.558 37.181 ;
     RECT  12.096 37.165 18.918 37.201 ;
     RECT  19.872 37.147 20.43 37.339 ;
     RECT  9.936 36.689 10.854 37.427 ;
     RECT  11.736 37.201 18.918 37.471 ;
     RECT  19.872 37.339 20.502 37.625 ;
     RECT  11.628 37.471 18.954 37.769 ;
     RECT  11.844 37.769 18.954 37.903 ;
     RECT  19.872 37.625 20.43 37.903 ;
     RECT  11.844 37.903 20.43 37.949 ;
     RECT  2.304 36.823 5.397 38.039 ;
     RECT  11.844 37.949 18.954 38.201 ;
     RECT  0.144 38.101 0.162 38.333 ;
     RECT  11.844 38.201 18.897 38.399 ;
     RECT  19.908 37.949 20.43 38.491 ;
     RECT  9.936 37.427 10.797 38.749 ;
     RECT  2.34 38.039 5.397 38.821 ;
     RECT  9.936 38.749 10.854 38.849 ;
     RECT  2.304 38.821 5.397 38.875 ;
     RECT  2.268 38.875 5.397 38.939 ;
     RECT  6.84 36.689 6.858 38.939 ;
     RECT  19.908 38.491 20.502 39.067 ;
     RECT  12.06 38.399 18.897 39.181 ;
     RECT  12.06 39.181 18.954 39.293 ;
     RECT  19.872 39.067 20.502 39.293 ;
     RECT  12.096 39.293 18.954 39.451 ;
     RECT  19.872 39.293 20.43 39.451 ;
     RECT  12.096 39.451 20.43 39.623 ;
     RECT  9.936 38.849 10.797 39.721 ;
     RECT  9.936 39.721 10.854 39.793 ;
     RECT  6.804 39.901 6.822 40.019 ;
     RECT  0.54 39.721 0.558 40.061 ;
     RECT  9.936 39.793 10.926 40.135 ;
     RECT  9.9 40.135 10.926 40.297 ;
     RECT  12.096 39.623 19.386 40.297 ;
     RECT  20.16 39.623 20.43 40.361 ;
     RECT  9.9 40.297 19.386 40.397 ;
     RECT  20.16 40.361 20.322 40.411 ;
     RECT  0.144 40.369 0.162 40.637 ;
     RECT  9.9 40.397 18.897 41.021 ;
     RECT  19.908 40.411 20.322 41.371 ;
     RECT  0.54 41.413 0.558 41.419 ;
     RECT  19.908 41.371 20.43 41.477 ;
     RECT  0.216 41.419 0.558 41.597 ;
     RECT  9.9 41.021 12.114 41.791 ;
     RECT  12.924 41.021 18.897 41.791 ;
     RECT  2.304 38.939 5.397 41.819 ;
     RECT  20.232 41.477 20.43 42.139 ;
     RECT  9.9 41.791 18.954 42.179 ;
     RECT  9.9 42.179 12.114 42.251 ;
     RECT  12.888 42.179 18.954 42.251 ;
     RECT  20.232 42.139 20.502 42.251 ;
     RECT  21.42 40.795 21.438 42.287 ;
     RECT  19.908 42.331 19.926 42.52 ;
     RECT  2.304 41.819 3.438 42.601 ;
     RECT  4.356 41.819 5.397 42.601 ;
     RECT  14.4 42.251 18.954 42.601 ;
     RECT  19.872 42.52 19.926 42.601 ;
     RECT  14.4 42.601 19.926 42.749 ;
     RECT  19.872 42.749 19.926 42.755 ;
     RECT  0.54 41.597 0.558 42.941 ;
     RECT  14.4 42.749 18.954 43.061 ;
     RECT  12.888 42.251 13.497 43.069 ;
     RECT  14.4 43.061 18.918 43.069 ;
     RECT  6.84 42.601 6.858 43.097 ;
     RECT  9.9 42.251 12.078 43.099 ;
     RECT  12.888 43.069 18.918 43.099 ;
     RECT  19.908 42.755 19.926 43.099 ;
     RECT  19.908 43.099 20.286 43.291 ;
     RECT  19.908 43.291 20.502 43.709 ;
     RECT  0.504 43.537 0.522 43.771 ;
     RECT  9.9 43.099 18.918 43.901 ;
     RECT  12.24 43.901 18.918 43.951 ;
     RECT  20.412 43.709 20.502 44.069 ;
     RECT  12.24 43.951 18.99 44.221 ;
     RECT  2.304 42.601 5.397 44.248 ;
     RECT  12.24 44.221 19.314 44.339 ;
     RECT  2.268 44.248 5.397 44.375 ;
     RECT  20.412 44.069 20.43 44.443 ;
     RECT  0.504 43.771 0.558 44.477 ;
     RECT  7.815 2.413 8.097 44.491 ;
     RECT  7.092 44.491 8.097 44.609 ;
     RECT  20.16 44.443 20.43 44.635 ;
     RECT  0.504 44.477 0.522 44.669 ;
     RECT  9.9 43.901 11.394 44.689 ;
     RECT  12.24 44.339 19.026 44.689 ;
     RECT  9.9 44.689 19.026 44.765 ;
     RECT  19.908 44.635 20.43 44.827 ;
     RECT  2.304 44.375 5.397 44.951 ;
     RECT  19.908 44.827 20.502 44.951 ;
     RECT  6.768 44.653 6.822 44.987 ;
     RECT  12.24 44.765 19.026 45.059 ;
     RECT  19.908 44.951 20.43 45.257 ;
     RECT  6.804 44.987 6.822 45.293 ;
     RECT  2.304 44.951 3.042 45.391 ;
     RECT  12.24 45.059 18.897 45.419 ;
     RECT  2.268 45.391 3.042 45.437 ;
     RECT  9.9 44.765 11.394 45.547 ;
     RECT  12.888 45.419 18.897 45.563 ;
     RECT  9.9 45.547 12.114 45.599 ;
     RECT  2.304 45.437 3.042 45.769 ;
     RECT  3.816 44.951 5.397 45.769 ;
     RECT  2.304 45.769 5.397 45.959 ;
     RECT  12.924 45.563 18.897 45.959 ;
     RECT  20.16 45.257 20.43 45.979 ;
     RECT  0.54 45.463 0.558 46.013 ;
     RECT  14.364 45.959 18.897 46.031 ;
     RECT  2.304 45.959 4.266 46.067 ;
     RECT  14.4 46.031 18.897 46.111 ;
     RECT  2.304 46.067 4.194 46.171 ;
     RECT  14.4 46.111 18.954 46.201 ;
     RECT  14.4 46.201 19.134 46.253 ;
     RECT  2.124 46.171 4.194 46.301 ;
     RECT  19.908 45.979 20.43 46.363 ;
     RECT  19.908 46.363 20.502 46.373 ;
     RECT  9.9 45.599 12.078 46.381 ;
     RECT  12.924 45.959 13.497 46.381 ;
     RECT  2.304 46.301 4.05 46.571 ;
     RECT  20.16 46.373 20.502 46.615 ;
     RECT  20.16 46.615 20.538 46.781 ;
     RECT  14.4 46.253 18.897 46.813 ;
     RECT  4.032 46.571 4.05 46.841 ;
     RECT  9.9 46.381 13.497 46.849 ;
     RECT  14.256 46.813 18.897 46.849 ;
     RECT  20.16 46.781 20.502 46.913 ;
     RECT  0.504 46.543 0.522 46.939 ;
     RECT  5.04 45.959 5.397 47.047 ;
     RECT  0.144 46.939 0.522 47.069 ;
     RECT  20.16 46.913 20.25 47.131 ;
     RECT  6.84 47.047 6.858 47.183 ;
     RECT  0.504 47.069 0.522 47.191 ;
     RECT  2.304 46.571 3.258 47.389 ;
     RECT  9.9 46.849 18.897 47.461 ;
     RECT  6.804 47.425 6.822 47.651 ;
     RECT  4.572 47.047 5.397 47.659 ;
     RECT  2.304 47.389 3.51 47.695 ;
     RECT  4.464 47.659 5.397 47.695 ;
     RECT  9.9 47.461 18.954 47.707 ;
     RECT  19.908 47.131 20.25 47.707 ;
     RECT  0.504 47.191 0.558 47.741 ;
     RECT  9.9 47.707 19.134 47.759 ;
     RECT  2.304 47.695 5.397 47.885 ;
     RECT  5.004 47.885 5.397 48.119 ;
     RECT  19.908 47.707 20.286 48.227 ;
     RECT  20.268 48.227 20.286 48.263 ;
     RECT  9.9 47.759 18.897 48.413 ;
     RECT  0.54 47.741 0.558 48.509 ;
     RECT  20.376 48.283 20.43 48.667 ;
     RECT  5.115 48.119 5.397 48.703 ;
     RECT  5.115 48.703 5.526 48.739 ;
     RECT  12.924 48.413 18.897 48.739 ;
     RECT  12.924 48.739 19.026 48.811 ;
     RECT  5.115 48.739 5.598 48.839 ;
     RECT  12.924 48.811 19.422 48.893 ;
     RECT  12.924 48.893 19.026 48.929 ;
     RECT  9.9 48.413 12.078 48.965 ;
     RECT  20.376 48.667 20.502 49.051 ;
     RECT  19.872 49.051 20.502 49.28 ;
     RECT  2.304 47.885 4.158 49.351 ;
     RECT  10.515 48.965 12.078 49.351 ;
     RECT  12.924 48.929 18.99 49.351 ;
     RECT  2.304 49.351 4.302 49.469 ;
     RECT  2.34 49.469 4.302 49.565 ;
     RECT  6.84 48.235 6.858 49.577 ;
     RECT  5.115 48.839 5.397 49.621 ;
     RECT  19.872 49.28 20.43 49.811 ;
     RECT  2.415 49.565 4.302 49.819 ;
     RECT  5.04 49.621 5.397 49.819 ;
     RECT  10.515 49.351 18.99 49.891 ;
     RECT  2.415 49.819 5.397 49.919 ;
     RECT  5.04 49.919 5.397 50.009 ;
     RECT  10.515 49.891 19.098 50.009 ;
     RECT  12.888 50.009 19.098 50.011 ;
     RECT  19.872 49.811 20.394 50.011 ;
     RECT  12.888 50.011 20.394 50.387 ;
     RECT  2.415 49.919 4.05 50.395 ;
     RECT  6.804 50.251 6.822 50.423 ;
     RECT  2.376 50.395 4.05 50.431 ;
     RECT  10.515 50.009 12.078 50.549 ;
     RECT  20.268 50.387 20.394 50.779 ;
     RECT  11.736 50.549 12.078 50.791 ;
     RECT  12.888 50.387 19.458 50.791 ;
     RECT  2.304 50.431 4.05 50.899 ;
     RECT  5.115 50.009 5.397 50.899 ;
     RECT  0.144 49.513 0.162 51.005 ;
     RECT  11.736 50.791 19.458 51.161 ;
     RECT  20.268 50.779 20.502 51.355 ;
     RECT  19.908 51.355 20.502 51.503 ;
     RECT  2.304 50.899 5.397 51.899 ;
     RECT  6.912 51.871 6.93 52.051 ;
     RECT  11.736 51.161 18.897 52.169 ;
     RECT  6.912 52.051 7.002 52.241 ;
     RECT  6.912 52.241 6.93 52.439 ;
     RECT  0.54 51.709 0.558 52.541 ;
     RECT  21.42 52.315 21.438 52.583 ;
     RECT  18.036 52.169 18.897 52.591 ;
     RECT  18.036 52.591 18.954 52.699 ;
     RECT  18.036 52.699 19.386 52.781 ;
     RECT  10.515 50.549 10.998 52.825 ;
     RECT  11.736 52.169 17.298 52.825 ;
     RECT  2.304 51.899 4.266 52.861 ;
     RECT  5.004 51.899 5.397 52.861 ;
     RECT  10.515 52.825 17.298 52.939 ;
     RECT  18.036 52.781 19.098 52.939 ;
     RECT  2.304 52.861 5.397 52.979 ;
     RECT  10.515 52.939 19.098 53.015 ;
     RECT  20.412 51.503 20.502 53.275 ;
     RECT  2.304 52.979 4.122 53.293 ;
     RECT  2.268 53.293 4.122 53.501 ;
     RECT  19.872 53.275 20.502 53.501 ;
     RECT  10.515 53.015 19.026 53.591 ;
     RECT  2.304 53.501 4.122 53.797 ;
     RECT  0.144 53.833 0.162 53.899 ;
     RECT  9.144 53.221 9.162 53.941 ;
     RECT  2.304 53.797 4.158 54.059 ;
     RECT  9.144 53.941 9.234 54.059 ;
     RECT  0.144 53.899 0.234 54.077 ;
     RECT  2.415 54.059 4.158 54.103 ;
     RECT  19.908 53.501 20.502 54.131 ;
     RECT  2.415 54.103 4.374 54.301 ;
     RECT  5.115 52.979 5.397 54.301 ;
     RECT  10.515 53.591 18.897 54.571 ;
     RECT  10.515 54.571 19.026 54.599 ;
     RECT  12.888 54.599 19.026 54.635 ;
     RECT  9.144 54.059 9.198 54.707 ;
     RECT  0.144 54.077 0.162 54.845 ;
     RECT  12.924 54.635 19.026 54.869 ;
     RECT  20.412 54.131 20.502 54.941 ;
     RECT  21.42 54.811 21.438 54.941 ;
     RECT  20.412 54.941 20.43 55.003 ;
     RECT  9.18 54.707 9.198 55.049 ;
     RECT  0.216 55.003 0.234 55.181 ;
     RECT  2.415 54.301 5.397 55.195 ;
     RECT  2.304 55.195 5.397 55.387 ;
     RECT  6.84 55.387 6.858 55.489 ;
     RECT  2.304 55.387 5.49 55.517 ;
     RECT  6.84 55.489 6.93 55.561 ;
     RECT  10.515 54.599 12.078 55.561 ;
     RECT  12.924 54.869 18.897 55.561 ;
     RECT  2.304 55.517 5.397 55.579 ;
     RECT  6.732 55.561 6.93 55.589 ;
     RECT  2.268 55.579 5.397 55.679 ;
     RECT  6.732 55.589 6.822 55.751 ;
     RECT  19.908 55.003 20.43 55.771 ;
     RECT  19.872 55.771 20.43 55.963 ;
     RECT  0.54 55.183 0.558 55.997 ;
     RECT  9.216 55.921 9.234 56.029 ;
     RECT  9.18 56.029 9.234 56.03 ;
     RECT  19.872 55.963 20.502 56.327 ;
     RECT  20.16 56.327 20.502 56.363 ;
     RECT  2.304 55.679 5.397 56.399 ;
     RECT  6.804 55.751 6.822 56.533 ;
     RECT  6.804 56.533 6.894 56.605 ;
     RECT  9.18 56.03 9.198 56.669 ;
     RECT  6.804 56.605 6.966 56.803 ;
     RECT  0.144 56.059 0.162 56.861 ;
     RECT  10.515 55.561 18.897 56.911 ;
     RECT  6.804 56.803 7.038 56.939 ;
     RECT  10.44 56.911 18.897 57.037 ;
     RECT  4.788 56.399 5.397 57.073 ;
     RECT  2.415 56.399 4.05 57.181 ;
     RECT  21.42 56.347 21.438 57.209 ;
     RECT  2.34 57.181 4.05 57.271 ;
     RECT  4.788 57.073 5.454 57.271 ;
     RECT  9.468 57.037 18.897 57.307 ;
     RECT  9.468 57.307 19.026 57.335 ;
     RECT  2.34 57.271 5.454 57.341 ;
     RECT  6.804 56.939 6.93 57.379 ;
     RECT  6.768 57.379 6.93 57.407 ;
     RECT  6.768 57.407 6.858 57.443 ;
     RECT  6.768 57.443 6.786 57.479 ;
     RECT  20.412 56.363 20.502 57.499 ;
     RECT  9.54 57.335 19.026 57.605 ;
     RECT  20.16 57.499 20.502 57.691 ;
     RECT  0.54 57.343 0.558 57.725 ;
     RECT  4.68 57.341 5.454 57.749 ;
     RECT  2.34 57.341 3.906 57.811 ;
     RECT  10.188 57.605 19.026 57.839 ;
     RECT  10.188 57.839 18.99 57.983 ;
     RECT  2.304 57.811 3.906 58.072 ;
     RECT  4.68 57.749 5.397 58.072 ;
     RECT  10.188 57.983 13.497 58.205 ;
     RECT  2.304 58.072 5.397 58.267 ;
     RECT  2.268 58.267 5.397 58.379 ;
     RECT  10.515 58.205 13.497 58.451 ;
     RECT  14.22 57.983 18.99 58.651 ;
     RECT  19.908 57.691 20.502 58.651 ;
     RECT  11.736 58.451 13.497 58.939 ;
     RECT  14.22 58.651 20.502 58.939 ;
     RECT  11.736 58.939 20.502 58.991 ;
     RECT  11.736 58.991 20.178 59.027 ;
     RECT  9.144 58.963 9.162 59.063 ;
     RECT  11.736 59.027 19.422 59.063 ;
     RECT  21.42 59.035 21.438 59.233 ;
     RECT  21.384 59.233 21.438 59.369 ;
     RECT  21.384 59.369 21.402 59.453 ;
     RECT  6.84 58.801 6.858 59.503 ;
     RECT  10.515 58.451 10.998 59.503 ;
     RECT  11.736 59.063 19.386 59.503 ;
     RECT  2.304 58.379 5.397 59.603 ;
     RECT  6.804 59.503 6.858 59.603 ;
     RECT  10.515 59.503 19.386 59.729 ;
     RECT  12.816 59.729 19.386 59.765 ;
     RECT  0.216 59.611 0.234 59.789 ;
     RECT  6.84 59.603 6.858 59.801 ;
     RECT  12.888 59.765 19.386 59.801 ;
     RECT  20.16 59.027 20.178 59.803 ;
     RECT  19.872 59.803 20.178 59.995 ;
     RECT  19.872 59.995 20.502 60.071 ;
     RECT  2.304 59.603 3.582 60.379 ;
     RECT  4.536 59.603 5.397 60.379 ;
     RECT  19.872 60.071 20.286 60.413 ;
     RECT  2.304 60.379 5.397 60.539 ;
     RECT  9.144 59.881 9.162 60.845 ;
     RECT  0.18 60.853 0.198 60.859 ;
     RECT  20.124 60.413 20.286 60.955 ;
     RECT  11.736 59.729 12.078 60.961 ;
     RECT  12.888 59.801 18.897 60.961 ;
     RECT  11.736 60.961 19.314 61.339 ;
     RECT  20.124 60.955 20.43 61.339 ;
     RECT  0.144 60.859 0.198 61.429 ;
     RECT  11.736 61.339 20.43 61.493 ;
     RECT  20.232 61.493 20.43 61.531 ;
     RECT  0.144 61.429 0.558 61.565 ;
     RECT  20.232 61.531 20.502 61.691 ;
     RECT  0.54 61.565 0.558 61.757 ;
     RECT  10.515 59.729 10.998 61.771 ;
     RECT  11.736 61.493 19.386 61.771 ;
     RECT  6.804 61.861 6.822 62.033 ;
     RECT  10.515 61.771 19.386 62.033 ;
     RECT  20.232 61.691 20.25 62.299 ;
     RECT  2.304 60.539 4.266 62.311 ;
     RECT  5.115 60.539 5.397 62.311 ;
     RECT  2.304 62.311 5.397 62.437 ;
     RECT  6.84 62.311 6.858 62.465 ;
     RECT  2.304 62.437 5.49 62.545 ;
     RECT  0.54 62.581 0.558 62.671 ;
     RECT  2.304 62.545 5.706 62.699 ;
     RECT  19.908 62.299 20.25 62.779 ;
     RECT  0.144 62.671 0.558 62.813 ;
     RECT  0.144 62.813 0.162 62.909 ;
     RECT  19.908 62.779 20.502 63.041 ;
     RECT  21.42 61.723 21.438 63.247 ;
     RECT  21.384 63.247 21.438 63.293 ;
     RECT  10.515 62.033 18.954 63.391 ;
     RECT  19.908 63.041 20.43 63.391 ;
     RECT  2.304 62.699 4.086 63.481 ;
     RECT  4.824 62.699 5.706 63.481 ;
     RECT  2.304 63.481 5.706 63.643 ;
     RECT  10.515 63.391 20.43 63.653 ;
     RECT  2.268 63.643 5.706 63.689 ;
     RECT  10.515 63.653 18.954 63.821 ;
     RECT  21.42 63.293 21.438 63.869 ;
     RECT  12.816 63.821 18.954 63.959 ;
     RECT  19.872 63.653 20.43 64.193 ;
     RECT  19.908 64.193 20.43 64.219 ;
     RECT  2.268 63.689 5.397 64.253 ;
     RECT  10.515 63.821 12.078 64.561 ;
     RECT  12.816 63.959 18.897 64.561 ;
     RECT  2.304 64.253 5.397 64.637 ;
     RECT  19.908 64.219 20.502 64.661 ;
     RECT  2.304 64.637 4.158 64.733 ;
     RECT  0.144 64.699 0.162 64.829 ;
     RECT  6.84 64.471 6.858 64.975 ;
     RECT  19.908 64.661 20.43 64.987 ;
     RECT  0.54 64.939 0.558 65.021 ;
     RECT  2.304 64.733 4.05 65.129 ;
     RECT  5.115 64.637 5.397 65.137 ;
     RECT  5.115 65.137 5.49 65.237 ;
     RECT  9.144 65.011 9.234 65.309 ;
     RECT  2.304 65.129 3.798 65.371 ;
     RECT  5.115 65.237 5.397 65.371 ;
     RECT  6.84 64.975 6.894 65.371 ;
     RECT  6.804 65.371 6.894 65.399 ;
     RECT  10.515 64.561 18.897 65.399 ;
     RECT  2.268 65.371 3.798 65.471 ;
     RECT  19.872 64.987 20.43 65.471 ;
     RECT  12.852 65.399 18.897 65.479 ;
     RECT  6.804 65.399 6.858 65.543 ;
     RECT  19.908 65.471 20.43 65.543 ;
     RECT  12.852 65.479 18.99 65.641 ;
     RECT  5.004 65.371 5.397 65.785 ;
     RECT  9.144 65.309 9.162 65.849 ;
     RECT  0.18 65.749 0.198 65.911 ;
     RECT  4.752 65.785 5.397 65.939 ;
     RECT  12.852 65.641 19.026 65.939 ;
     RECT  2.304 65.471 3.798 66.055 ;
     RECT  6.84 65.543 6.858 66.119 ;
     RECT  0.144 65.911 0.198 66.173 ;
     RECT  20.16 65.543 20.43 66.353 ;
     RECT  10.515 65.399 12.078 66.361 ;
     RECT  12.852 65.939 13.734 66.361 ;
     RECT  0.18 66.173 0.198 66.365 ;
     RECT  9.18 66.487 9.198 66.523 ;
     RECT  14.472 65.939 19.026 66.523 ;
     RECT  20.268 66.353 20.43 66.523 ;
     RECT  2.304 66.055 4.158 66.721 ;
     RECT  5.115 65.939 5.397 66.721 ;
     RECT  20.268 66.523 20.538 66.749 ;
     RECT  6.768 66.721 6.822 66.857 ;
     RECT  9.18 66.523 9.27 66.901 ;
     RECT  10.515 66.361 13.734 66.901 ;
     RECT  14.472 66.523 19.386 66.901 ;
     RECT  6.804 66.857 6.822 66.929 ;
     RECT  9.18 66.901 9.702 67.091 ;
     RECT  10.515 66.901 19.386 67.091 ;
     RECT  6.84 66.991 6.858 67.199 ;
     RECT  9.18 67.091 9.27 67.261 ;
     RECT  20.268 66.749 20.43 67.291 ;
     RECT  19.908 67.291 20.43 67.361 ;
     RECT  9.144 67.261 9.27 67.397 ;
     RECT  9.144 67.397 9.198 67.433 ;
     RECT  9.144 67.433 9.162 67.469 ;
     RECT  0.144 67.171 0.162 67.603 ;
     RECT  10.515 67.091 19.026 67.631 ;
     RECT  20.268 67.361 20.43 67.675 ;
     RECT  10.515 67.631 18.99 67.865 ;
     RECT  2.304 66.721 5.397 67.981 ;
     RECT  0.144 67.603 0.558 68.093 ;
     RECT  10.515 67.865 18.918 68.171 ;
     RECT  6.84 67.981 6.858 68.207 ;
     RECT  2.304 67.981 6.102 68.369 ;
     RECT  20.268 67.675 20.502 68.443 ;
     RECT  6.228 68.449 6.246 68.549 ;
     RECT  9.144 68.449 9.162 68.549 ;
     RECT  0.144 68.093 0.198 68.669 ;
     RECT  10.515 68.171 18.897 68.783 ;
     RECT  19.908 68.443 20.502 68.945 ;
     RECT  0.18 68.669 0.198 69.053 ;
     RECT  11.7 68.783 18.897 69.061 ;
     RECT  2.304 68.369 5.397 69.179 ;
     RECT  11.7 69.061 19.026 69.179 ;
     RECT  0.504 69.061 0.522 69.223 ;
     RECT  11.844 69.179 19.026 69.331 ;
     RECT  2.412 69.179 5.397 69.449 ;
     RECT  10.515 68.783 10.962 69.449 ;
     RECT  11.844 69.331 19.134 69.485 ;
     RECT  0.504 69.223 0.558 69.629 ;
     RECT  2.415 69.449 5.397 69.719 ;
     RECT  4.788 69.719 5.397 69.791 ;
     RECT  0.504 69.629 0.522 69.821 ;
     RECT  11.844 69.485 19.026 69.989 ;
     RECT  12.06 69.989 19.026 70.013 ;
     RECT  12.06 70.013 12.078 70.025 ;
     RECT  12.816 70.013 19.026 70.061 ;
     RECT  19.908 68.945 20.43 70.061 ;
     RECT  2.415 69.719 4.014 70.171 ;
     RECT  6.912 70.231 6.93 70.403 ;
     RECT  2.304 70.171 4.014 70.555 ;
     RECT  4.86 69.791 5.397 70.555 ;
     RECT  19.908 70.061 20.25 70.555 ;
     RECT  6.84 70.501 6.858 70.601 ;
     RECT  2.304 70.555 5.397 70.871 ;
     RECT  19.872 70.555 20.25 70.943 ;
     RECT  12.816 70.061 18.897 70.951 ;
     RECT  21.42 70.171 21.438 70.979 ;
     RECT  10.515 69.449 10.854 71.077 ;
     RECT  0.144 70.411 0.162 71.357 ;
     RECT  10.515 71.077 10.926 71.383 ;
     RECT  6.768 71.455 6.786 71.491 ;
     RECT  10.515 71.383 10.962 71.519 ;
     RECT  6.768 71.491 6.858 71.681 ;
     RECT  6.804 71.681 6.858 71.717 ;
     RECT  2.304 70.871 4.014 71.725 ;
     RECT  4.788 70.871 5.397 71.725 ;
     RECT  12.096 70.951 18.897 71.899 ;
     RECT  19.872 70.943 20.178 71.899 ;
     RECT  12.096 71.899 20.178 72.023 ;
     RECT  19.908 72.023 20.178 72.091 ;
     RECT  12.096 72.023 18.954 72.229 ;
     RECT  2.304 71.725 5.397 72.283 ;
     RECT  12.06 72.229 18.954 72.461 ;
     RECT  6.804 71.717 6.822 72.463 ;
     RECT  19.908 72.091 20.43 72.463 ;
     RECT  6.804 72.463 6.93 72.661 ;
     RECT  6.732 72.661 6.93 72.725 ;
     RECT  14.544 72.461 18.954 72.761 ;
     RECT  10.515 71.519 10.926 72.841 ;
     RECT  12.06 72.461 13.698 72.841 ;
     RECT  6.732 72.725 6.894 72.869 ;
     RECT  2.268 72.283 5.397 72.893 ;
     RECT  6.804 72.869 6.894 72.959 ;
     RECT  10.515 72.841 13.698 72.959 ;
     RECT  10.515 72.959 12.078 73.037 ;
     RECT  10.515 73.037 11.646 73.139 ;
     RECT  19.908 72.463 20.502 73.301 ;
     RECT  14.544 72.761 18.897 73.345 ;
     RECT  2.304 72.893 5.397 73.381 ;
     RECT  19.908 73.301 20.43 73.435 ;
     RECT  12.816 72.959 13.698 73.651 ;
     RECT  14.508 73.345 18.897 73.651 ;
     RECT  19.872 73.435 20.43 73.651 ;
     RECT  0.54 73.273 0.558 73.661 ;
     RECT  2.304 73.381 5.454 73.679 ;
     RECT  12.06 73.849 12.078 73.921 ;
     RECT  12.816 73.651 20.43 73.921 ;
     RECT  6.84 72.959 6.894 73.949 ;
     RECT  10.515 73.139 10.926 74.11 ;
     RECT  10.515 74.11 10.962 74.219 ;
     RECT  6.84 73.949 6.858 74.489 ;
     RECT  12.06 73.921 20.43 74.579 ;
     RECT  12.816 74.579 20.43 74.587 ;
     RECT  12.06 74.579 12.078 74.669 ;
     RECT  0.144 74.083 0.162 74.813 ;
     RECT  12.816 74.587 20.502 74.921 ;
     RECT  19.908 74.921 20.502 75.2 ;
     RECT  12.816 74.921 19.134 75.245 ;
     RECT  11.592 75.271 11.61 75.389 ;
     RECT  11.844 75.469 12.078 75.541 ;
     RECT  12.816 75.245 18.897 75.541 ;
     RECT  2.304 73.679 5.397 75.581 ;
     RECT  2.415 75.581 5.397 75.731 ;
     RECT  0.144 75.703 0.162 75.739 ;
     RECT  19.908 75.2 20.286 75.739 ;
     RECT  6.84 75.631 6.858 75.803 ;
     RECT  2.415 75.731 4.338 75.929 ;
     RECT  19.872 75.739 20.286 75.931 ;
     RECT  7.815 44.609 8.097 75.937 ;
     RECT  10.515 74.219 10.854 75.973 ;
     RECT  2.415 75.929 4.266 76.001 ;
     RECT  19.872 75.931 20.43 76.073 ;
     RECT  7.812 75.937 8.097 76.081 ;
     RECT  10.515 75.973 10.89 76.109 ;
     RECT  19.908 76.073 20.43 76.315 ;
     RECT  0.144 75.739 0.558 76.349 ;
     RECT  7.632 76.081 8.097 76.379 ;
     RECT  2.415 76.001 4.158 76.469 ;
     RECT  2.415 76.469 4.014 76.621 ;
     RECT  11.844 75.541 18.897 76.621 ;
     RECT  2.304 76.621 4.014 76.739 ;
     RECT  11.7 76.621 18.918 76.739 ;
     RECT  6.804 76.243 6.822 76.747 ;
     RECT  6.804 76.747 6.858 76.883 ;
     RECT  0.144 76.349 0.162 76.925 ;
     RECT  5.115 75.731 5.397 76.981 ;
     RECT  21.42 76.891 21.438 77.117 ;
     RECT  5.004 76.981 5.397 77.251 ;
     RECT  12.06 76.739 18.918 77.323 ;
     RECT  4.464 77.251 5.397 77.395 ;
     RECT  12.06 77.323 19.026 77.423 ;
     RECT  2.304 76.739 3.654 77.693 ;
     RECT  4.464 77.395 5.454 77.701 ;
     RECT  6.84 76.883 6.858 77.791 ;
     RECT  6.804 77.791 6.858 77.827 ;
     RECT  9.252 77.701 9.27 77.891 ;
     RECT  19.908 76.315 20.502 77.891 ;
     RECT  10.515 76.109 10.854 77.899 ;
     RECT  4.464 77.701 5.598 77.927 ;
     RECT  6.768 77.827 6.858 77.927 ;
     RECT  2.412 77.693 3.654 77.971 ;
     RECT  4.464 77.927 5.397 77.971 ;
     RECT  6.804 77.927 6.858 77.999 ;
     RECT  10.515 77.899 10.926 78.169 ;
     RECT  12.06 77.423 18.954 78.169 ;
     RECT  10.515 78.169 18.954 78.269 ;
     RECT  10.515 78.269 13.698 78.359 ;
     RECT  6.912 78.331 6.93 78.367 ;
     RECT  14.472 78.269 18.954 78.427 ;
     RECT  19.908 77.891 20.43 78.427 ;
     RECT  6.912 78.367 7.002 78.467 ;
     RECT  2.412 77.971 5.397 78.475 ;
     RECT  10.515 78.359 10.854 78.539 ;
     RECT  14.472 78.427 20.43 78.619 ;
     RECT  14.472 78.619 20.502 78.665 ;
     RECT  2.304 78.475 5.397 78.899 ;
     RECT  15.915 78.665 20.502 79.007 ;
     RECT  0.54 77.863 0.558 79.037 ;
     RECT  12.06 78.359 13.698 79.051 ;
     RECT  14.472 78.665 14.994 79.051 ;
     RECT  12.06 79.051 14.994 79.169 ;
     RECT  12.06 79.169 12.078 79.205 ;
     RECT  19.908 79.007 20.502 79.241 ;
     RECT  10.515 78.539 10.797 79.321 ;
     RECT  6.84 78.907 6.858 79.411 ;
     RECT  0.144 79.291 0.162 79.421 ;
     RECT  10.476 79.321 10.926 79.439 ;
     RECT  12.816 79.169 14.994 79.555 ;
     RECT  15.915 79.007 19.026 79.555 ;
     RECT  19.908 79.241 20.43 79.619 ;
     RECT  2.412 78.899 5.397 79.681 ;
     RECT  12.816 79.555 19.026 79.781 ;
     RECT  6.84 79.411 6.93 79.861 ;
     RECT  7.815 76.379 8.097 79.861 ;
     RECT  6.84 79.861 8.097 79.951 ;
     RECT  12.816 79.781 13.698 79.951 ;
     RECT  6.804 79.951 8.097 79.979 ;
     RECT  2.304 79.681 5.397 79.997 ;
     RECT  12.672 79.951 13.698 80.011 ;
     RECT  6.804 79.979 6.822 80.051 ;
     RECT  0.18 80.131 0.198 80.155 ;
     RECT  14.436 79.781 19.026 80.321 ;
     RECT  20.232 79.619 20.43 80.539 ;
     RECT  0.144 80.155 0.198 80.573 ;
     RECT  12.06 80.011 13.698 80.599 ;
     RECT  14.436 80.321 18.954 80.599 ;
     RECT  19.908 80.539 20.43 80.627 ;
     RECT  10.515 79.439 10.926 80.699 ;
     RECT  2.415 79.997 5.397 80.923 ;
     RECT  12.06 80.599 18.954 80.941 ;
     RECT  2.304 80.923 5.397 81.059 ;
     RECT  11.628 80.941 18.954 81.059 ;
     RECT  2.304 81.059 3.762 81.095 ;
     RECT  12.06 81.059 18.954 81.103 ;
     RECT  12.06 81.103 18.99 81.341 ;
     RECT  12.06 81.341 18.954 81.485 ;
     RECT  20.16 80.627 20.43 81.499 ;
     RECT  6.84 81.139 6.858 81.671 ;
     RECT  19.908 81.499 20.43 81.691 ;
     RECT  9.324 81.481 9.342 81.751 ;
     RECT  2.304 81.095 3.51 81.869 ;
     RECT  6.804 81.715 6.822 81.869 ;
     RECT  12.06 81.485 13.497 81.869 ;
     RECT  19.872 81.691 20.43 81.883 ;
     RECT  19.872 81.883 20.502 81.941 ;
     RECT  4.572 81.059 5.397 81.949 ;
     RECT  2.34 81.869 3.51 81.985 ;
     RECT  4.428 81.949 5.397 81.985 ;
     RECT  2.34 81.985 5.397 82.049 ;
     RECT  9.324 81.751 9.414 82.049 ;
     RECT  10.515 80.699 10.797 82.111 ;
     RECT  2.34 82.049 4.374 82.139 ;
     RECT  5.115 82.049 5.397 82.147 ;
     RECT  10.515 82.111 10.854 82.211 ;
     RECT  19.872 81.941 20.43 82.211 ;
     RECT  12.888 81.869 13.497 82.213 ;
     RECT  14.256 81.485 18.954 82.213 ;
     RECT  5.115 82.147 5.418 82.247 ;
     RECT  7.815 79.979 8.097 82.255 ;
     RECT  12.888 82.213 18.954 82.291 ;
     RECT  4.284 82.139 4.374 82.409 ;
     RECT  12.888 82.291 19.134 82.453 ;
     RECT  4.356 82.409 4.374 82.481 ;
     RECT  7.815 82.255 8.73 82.481 ;
     RECT  12.888 82.453 19.422 82.493 ;
     RECT  2.34 82.139 3.474 82.651 ;
     RECT  5.115 82.247 5.397 82.795 ;
     RECT  21.42 82.267 21.438 82.823 ;
     RECT  12.06 81.869 12.078 82.831 ;
     RECT  12.888 82.493 19.134 82.831 ;
     RECT  20.412 82.211 20.43 82.843 ;
     RECT  2.304 82.651 3.474 82.921 ;
     RECT  2.304 82.921 3.618 83.021 ;
     RECT  11.844 82.831 19.134 83.021 ;
     RECT  20.412 82.843 20.502 83.035 ;
     RECT  19.908 83.035 20.502 83.057 ;
     RECT  12.06 83.021 19.134 83.227 ;
     RECT  19.908 83.057 19.962 83.227 ;
     RECT  0.144 80.573 0.162 83.261 ;
     RECT  4.464 82.795 5.397 83.263 ;
     RECT  10.515 82.211 10.797 83.299 ;
     RECT  4.392 83.263 5.397 83.335 ;
     RECT  9.9 83.299 10.797 83.533 ;
     RECT  6.84 82.759 6.858 83.569 ;
     RECT  12.06 83.227 19.962 83.633 ;
     RECT  6.84 83.569 6.93 83.669 ;
     RECT  9.9 83.533 10.854 83.669 ;
     RECT  12.06 83.633 18.897 83.759 ;
     RECT  2.304 83.021 3.546 83.839 ;
     RECT  4.32 83.335 5.397 83.839 ;
     RECT  19.872 83.633 19.962 83.995 ;
     RECT  9.9 83.669 10.797 84.029 ;
     RECT  2.304 83.839 5.397 84.065 ;
     RECT  19.872 83.995 20.286 84.137 ;
     RECT  20.268 84.137 20.286 84.173 ;
     RECT  12.924 83.759 18.897 84.299 ;
     RECT  12.06 83.759 12.078 84.415 ;
     RECT  11.88 84.415 12.078 84.451 ;
     RECT  3.636 84.065 5.397 84.569 ;
     RECT  11.844 84.451 12.078 84.569 ;
     RECT  6.84 83.669 6.858 84.641 ;
     RECT  10.515 84.029 10.797 84.649 ;
     RECT  2.304 84.065 2.826 84.721 ;
     RECT  11.88 84.569 12.078 84.721 ;
     RECT  12.924 84.299 13.698 84.721 ;
     RECT  14.436 84.299 18.897 84.763 ;
     RECT  0.54 84.343 0.558 84.811 ;
     RECT  10.515 84.649 10.89 84.839 ;
     RECT  2.268 84.721 2.826 84.883 ;
     RECT  6.228 84.721 6.246 84.911 ;
     RECT  11.88 84.721 13.698 84.911 ;
     RECT  20.376 84.187 20.43 84.955 ;
     RECT  12.06 84.911 13.698 85.081 ;
     RECT  14.436 84.763 18.918 85.081 ;
     RECT  10.515 84.839 10.854 85.109 ;
     RECT  19.908 84.955 20.43 85.339 ;
     RECT  2.268 84.883 3.33 85.487 ;
     RECT  19.908 85.339 20.502 85.487 ;
     RECT  12.06 85.081 18.918 85.517 ;
     RECT  12.888 85.517 18.918 85.523 ;
     RECT  2.304 85.487 3.33 85.531 ;
     RECT  4.248 84.569 5.397 85.531 ;
     RECT  12.924 85.523 18.918 85.621 ;
     RECT  12.06 85.517 12.114 85.657 ;
     RECT  6.84 85.657 6.858 85.801 ;
     RECT  10.515 85.109 10.797 85.927 ;
     RECT  6.732 85.801 6.858 86.027 ;
     RECT  11.952 85.657 12.114 86.071 ;
     RECT  0.144 84.811 0.558 86.333 ;
     RECT  11.844 86.071 12.114 86.341 ;
     RECT  12.924 85.621 19.134 86.341 ;
     RECT  11.844 86.341 19.314 86.491 ;
     RECT  20.16 85.487 20.502 86.491 ;
     RECT  10.515 85.927 10.854 86.539 ;
     RECT  2.304 85.531 5.397 86.701 ;
     RECT  0.144 86.333 0.27 86.717 ;
     RECT  6.804 86.027 6.858 86.737 ;
     RECT  7.815 82.481 8.097 86.737 ;
     RECT  2.268 86.701 5.397 86.909 ;
     RECT  11.844 86.491 20.502 86.999 ;
     RECT  6.804 86.737 8.097 87.071 ;
     RECT  12.06 86.999 20.502 87.071 ;
     RECT  0.252 86.717 0.27 87.101 ;
     RECT  10.515 86.539 10.926 87.277 ;
     RECT  10.515 87.277 10.962 87.413 ;
     RECT  0.144 87.451 0.162 87.581 ;
     RECT  6.804 87.071 6.93 87.611 ;
     RECT  20.124 87.071 20.502 87.611 ;
     RECT  12.06 87.071 19.314 87.647 ;
     RECT  2.304 86.909 4.122 87.655 ;
     RECT  4.896 86.909 5.397 87.655 ;
     RECT  20.124 87.611 20.286 88.027 ;
     RECT  12.06 87.647 18.99 88.051 ;
     RECT  9.684 87.961 9.702 88.231 ;
     RECT  10.515 87.413 10.926 88.231 ;
     RECT  11.952 88.051 18.99 88.231 ;
     RECT  2.304 87.655 5.397 88.349 ;
     RECT  9.684 88.231 10.926 88.349 ;
     RECT  11.844 88.231 18.99 88.349 ;
     RECT  19.908 88.027 20.286 88.393 ;
     RECT  19.908 88.393 20.502 88.445 ;
     RECT  19.908 88.445 20.43 88.457 ;
     RECT  6.804 87.611 6.822 88.591 ;
     RECT  6.804 88.591 6.93 88.691 ;
     RECT  6.804 88.691 6.858 88.727 ;
     RECT  10.515 88.349 10.926 88.727 ;
     RECT  12.06 88.349 18.99 88.735 ;
     RECT  12.06 88.735 19.422 88.829 ;
     RECT  6.84 88.727 6.858 88.889 ;
     RECT  12.06 88.829 19.314 88.889 ;
     RECT  0.54 88.501 0.558 89.021 ;
     RECT  10.515 88.727 10.854 89.069 ;
     RECT  20.412 88.457 20.43 89.179 ;
     RECT  2.304 88.349 4.086 89.275 ;
     RECT  12.06 88.889 18.99 89.465 ;
     RECT  20.412 89.179 20.502 89.563 ;
     RECT  12.06 89.465 13.77 89.581 ;
     RECT  2.304 89.275 4.158 89.671 ;
     RECT  5.115 88.349 5.397 89.671 ;
     RECT  11.664 89.581 13.77 89.699 ;
     RECT  6.84 89.707 6.858 89.779 ;
     RECT  19.908 89.563 20.502 89.879 ;
     RECT  11.916 89.699 13.77 89.969 ;
     RECT  0.144 89.401 0.198 90.013 ;
     RECT  14.508 89.465 18.99 90.121 ;
     RECT  2.304 89.671 5.397 90.139 ;
     RECT  14.508 90.121 19.206 90.239 ;
     RECT  10.515 89.069 10.797 90.319 ;
     RECT  12.924 89.969 13.77 90.355 ;
     RECT  14.508 90.239 19.026 90.355 ;
     RECT  6.84 89.779 6.93 90.391 ;
     RECT  10.515 90.319 10.854 90.391 ;
     RECT  2.268 90.139 5.397 90.509 ;
     RECT  6.768 90.391 6.93 90.581 ;
     RECT  20.34 89.879 20.502 90.715 ;
     RECT  20.16 90.715 20.502 90.851 ;
     RECT  2.304 90.509 5.397 90.859 ;
     RECT  11.916 89.969 12.078 90.931 ;
     RECT  12.924 90.355 19.026 90.931 ;
     RECT  2.304 90.859 5.526 90.959 ;
     RECT  11.916 90.931 19.026 91.049 ;
     RECT  20.16 90.851 20.43 91.099 ;
     RECT  0.144 90.013 0.558 91.133 ;
     RECT  11.916 91.049 18.99 91.201 ;
     RECT  2.304 90.959 5.454 91.319 ;
     RECT  6.768 91.327 6.786 91.589 ;
     RECT  0.144 91.133 0.198 91.709 ;
     RECT  2.304 91.319 5.397 91.733 ;
     RECT  0.18 91.709 0.198 91.901 ;
     RECT  2.304 91.733 3.978 92.003 ;
     RECT  21.42 91.675 21.438 92.003 ;
     RECT  11.844 91.201 18.99 92.129 ;
     RECT  6.804 92.101 6.822 92.201 ;
     RECT  10.515 90.391 10.926 92.201 ;
     RECT  12.06 92.129 18.99 92.437 ;
     RECT  19.908 91.099 20.43 92.437 ;
     RECT  12.06 92.437 20.43 92.477 ;
     RECT  4.788 91.733 5.397 92.641 ;
     RECT  6.84 92.371 6.93 92.777 ;
     RECT  19.908 92.477 20.43 92.813 ;
     RECT  4.716 92.641 5.397 92.821 ;
     RECT  0.144 92.731 0.162 92.861 ;
     RECT  12.06 92.477 18.897 93.005 ;
     RECT  10.515 92.201 10.797 93.019 ;
     RECT  12.888 93.005 18.897 93.083 ;
     RECT  2.304 92.003 3.726 93.091 ;
     RECT  4.572 92.821 5.397 93.091 ;
     RECT  6.84 92.777 6.858 93.209 ;
     RECT  10.515 93.019 10.926 93.245 ;
     RECT  12.924 93.083 18.897 93.595 ;
     RECT  0.54 93.451 0.558 93.629 ;
     RECT  10.515 93.245 10.797 93.631 ;
     RECT  6.804 93.595 6.822 93.749 ;
     RECT  12.924 93.595 19.386 93.787 ;
     RECT  20.376 92.813 20.43 93.787 ;
     RECT  12.06 93.005 12.078 93.901 ;
     RECT  12.924 93.787 20.43 93.901 ;
     RECT  12.06 93.901 20.43 93.929 ;
     RECT  2.304 93.091 5.397 93.979 ;
     RECT  19.908 93.929 20.43 93.979 ;
     RECT  10.08 93.631 10.797 94.019 ;
     RECT  10.515 94.019 10.797 94.063 ;
     RECT  2.268 93.979 5.397 94.099 ;
     RECT  10.515 94.063 10.854 94.099 ;
     RECT  10.515 94.099 10.926 94.171 ;
     RECT  2.052 94.099 5.397 94.205 ;
     RECT  2.268 94.205 5.397 94.289 ;
     RECT  10.515 94.171 10.962 94.289 ;
     RECT  7.815 87.071 8.097 94.441 ;
     RECT  12.06 93.929 18.954 94.441 ;
     RECT  2.304 94.289 5.397 94.559 ;
     RECT  7.815 94.441 8.442 94.595 ;
     RECT  2.412 94.559 5.397 94.829 ;
     RECT  11.844 94.441 18.954 94.901 ;
     RECT  19.908 93.979 20.502 94.901 ;
     RECT  6.804 94.711 6.822 95.009 ;
     RECT  7.815 94.595 8.37 95.099 ;
     RECT  11.844 94.901 13.554 95.179 ;
     RECT  2.412 94.829 4.266 95.207 ;
     RECT  11.808 95.179 13.554 95.279 ;
     RECT  2.412 95.207 3.618 95.323 ;
     RECT  14.292 94.901 18.954 95.323 ;
     RECT  2.34 95.323 3.618 95.377 ;
     RECT  14.292 95.323 19.026 95.405 ;
     RECT  2.304 95.377 3.618 95.515 ;
     RECT  2.268 95.515 3.618 95.639 ;
     RECT  2.304 95.639 3.618 95.711 ;
     RECT  5.112 94.829 5.397 95.719 ;
     RECT  10.515 94.289 10.926 95.747 ;
     RECT  11.844 95.279 13.554 95.851 ;
     RECT  14.292 95.405 18.954 95.851 ;
     RECT  5.112 95.719 5.49 95.909 ;
     RECT  5.112 95.909 5.397 96.061 ;
     RECT  0.54 94.639 0.558 96.091 ;
     RECT  20.412 94.901 20.502 96.091 ;
     RECT  0.144 96.091 0.558 96.221 ;
     RECT  6.804 96.151 6.822 96.323 ;
     RECT  4.86 96.061 5.397 96.331 ;
     RECT  0.54 96.221 0.558 96.509 ;
     RECT  4.536 96.331 5.397 96.565 ;
     RECT  2.304 95.711 3.402 96.601 ;
     RECT  4.464 96.565 5.397 96.601 ;
     RECT  2.304 96.601 5.397 96.667 ;
     RECT  2.268 96.667 5.397 96.719 ;
     RECT  11.844 95.851 18.954 96.719 ;
     RECT  12.06 96.719 12.078 96.791 ;
     RECT  12.888 96.719 18.954 96.863 ;
     RECT  12.924 96.863 18.954 96.871 ;
     RECT  10.515 95.747 10.854 96.961 ;
     RECT  6.84 96.763 6.858 96.997 ;
     RECT  6.84 96.997 6.93 97.061 ;
     RECT  19.908 96.091 20.502 97.097 ;
     RECT  21.42 96.859 21.438 97.133 ;
     RECT  12.924 96.871 18.99 97.141 ;
     RECT  19.908 97.097 20.43 97.141 ;
     RECT  12.924 97.141 20.43 97.259 ;
     RECT  2.268 96.719 3.474 97.277 ;
     RECT  19.908 97.259 20.43 97.403 ;
     RECT  4.248 96.719 4.266 97.501 ;
     RECT  5.115 96.719 5.397 97.501 ;
     RECT  2.304 97.277 3.474 97.609 ;
     RECT  4.248 97.501 5.397 97.609 ;
     RECT  10.515 96.961 10.926 97.681 ;
     RECT  12.096 97.483 12.114 97.681 ;
     RECT  12.924 97.259 14.49 97.681 ;
     RECT  2.304 97.609 5.397 98.041 ;
     RECT  10.515 97.681 14.49 98.041 ;
     RECT  15.3 97.259 18.954 98.041 ;
     RECT  2.304 98.041 5.778 98.069 ;
     RECT  6.912 97.061 6.93 98.113 ;
     RECT  5.115 98.069 5.778 98.141 ;
     RECT  20.16 97.403 20.43 98.203 ;
     RECT  6.732 98.113 6.93 98.213 ;
     RECT  6.804 98.213 6.93 98.221 ;
     RECT  0.54 97.843 0.558 98.237 ;
     RECT  10.515 98.041 18.954 98.419 ;
     RECT  6.804 98.221 6.966 98.483 ;
     RECT  5.115 98.141 5.562 98.519 ;
     RECT  10.515 98.419 19.242 98.587 ;
     RECT  20.16 98.203 20.466 98.587 ;
     RECT  10.515 98.587 20.466 98.753 ;
     RECT  9.036 98.761 9.054 98.879 ;
     RECT  2.304 98.069 4.374 98.923 ;
     RECT  5.115 98.519 5.397 98.923 ;
     RECT  6.804 98.483 6.822 99.059 ;
     RECT  10.515 98.753 20.43 99.059 ;
     RECT  2.304 98.923 5.397 99.419 ;
     RECT  11.592 99.059 20.43 99.419 ;
     RECT  21.42 99.733 21.438 99.773 ;
     RECT  10.515 99.059 10.797 99.841 ;
     RECT  11.592 99.419 14.31 99.841 ;
     RECT  15.336 99.419 19.026 100.031 ;
     RECT  4.104 99.419 5.397 100.139 ;
     RECT  15.336 100.031 18.99 100.201 ;
     RECT  2.304 99.419 3.186 100.273 ;
     RECT  4.104 100.139 4.338 100.273 ;
     RECT  10.515 99.841 14.31 100.273 ;
     RECT  15.264 100.201 18.99 100.273 ;
     RECT  19.908 99.419 20.43 100.315 ;
     RECT  0.144 99.391 0.162 100.349 ;
     RECT  6.84 99.967 6.858 100.381 ;
     RECT  2.268 100.273 3.186 100.409 ;
     RECT  10.515 100.273 18.99 100.499 ;
     RECT  2.304 100.409 3.186 100.507 ;
     RECT  3.996 100.273 4.338 100.507 ;
     RECT  6.804 100.381 6.858 100.543 ;
     RECT  19.908 100.315 20.502 100.571 ;
     RECT  11.7 100.499 18.99 100.769 ;
     RECT  6.732 100.543 6.858 100.841 ;
     RECT  11.916 100.769 18.99 100.891 ;
     RECT  19.908 100.571 20.43 100.891 ;
     RECT  2.304 100.507 4.338 100.921 ;
     RECT  5.115 100.139 5.397 100.921 ;
     RECT  11.916 100.891 20.43 101.111 ;
     RECT  10.515 100.499 10.926 101.219 ;
     RECT  0.54 100.651 0.558 101.281 ;
     RECT  0.144 101.281 0.558 101.309 ;
     RECT  6.804 100.841 6.858 101.309 ;
     RECT  10.515 101.219 10.854 101.309 ;
     RECT  11.916 101.111 18.897 101.309 ;
     RECT  11.916 101.309 13.734 101.731 ;
     RECT  2.304 100.921 5.397 101.885 ;
     RECT  6.804 101.309 6.822 101.893 ;
     RECT  6.732 101.893 6.822 101.993 ;
     RECT  11.736 101.731 13.734 102.091 ;
     RECT  14.508 101.309 18.897 102.091 ;
     RECT  11.736 102.091 18.897 102.235 ;
     RECT  10.515 101.309 10.797 102.271 ;
     RECT  11.736 102.235 18.954 102.271 ;
     RECT  2.34 101.885 5.397 102.361 ;
     RECT  2.34 102.361 5.562 102.461 ;
     RECT  10.515 102.271 18.954 102.461 ;
     RECT  6.768 101.993 6.822 102.469 ;
     RECT  2.34 102.461 5.397 102.497 ;
     RECT  19.908 101.111 20.43 102.505 ;
     RECT  4.644 102.497 5.397 102.533 ;
     RECT  6.768 102.469 6.858 102.533 ;
     RECT  11.952 102.461 18.954 102.557 ;
     RECT  6.804 102.533 6.858 102.569 ;
     RECT  2.34 102.497 3.87 102.619 ;
     RECT  19.908 102.505 20.538 102.653 ;
     RECT  4.788 102.533 5.397 102.731 ;
     RECT  19.908 102.653 20.502 102.845 ;
     RECT  2.304 102.619 3.87 102.965 ;
     RECT  12.06 102.557 18.954 103 ;
     RECT  19.908 102.845 20.43 103 ;
     RECT  0.144 101.309 0.162 103.037 ;
     RECT  12.06 103 20.43 103.229 ;
     RECT  6.804 102.569 6.822 103.343 ;
     RECT  12.06 103.229 13.497 103.343 ;
     RECT  10.515 102.461 10.797 103.351 ;
     RECT  12.06 103.343 12.186 103.351 ;
     RECT  2.34 102.965 3.87 103.379 ;
     RECT  14.256 103.229 20.43 103.379 ;
     RECT  5.004 102.731 5.397 103.427 ;
     RECT  7.815 95.099 8.097 103.427 ;
     RECT  13.215 103.343 13.497 103.427 ;
     RECT  10.515 103.351 12.186 103.469 ;
     RECT  14.868 103.379 20.43 103.469 ;
     RECT  3.816 103.379 3.87 103.505 ;
     RECT  5.004 103.427 5.205 103.541 ;
     RECT  12.168 103.469 12.186 103.541 ;
     RECT  2.34 103.379 3.078 103.577 ;
     RECT  19.98 103.469 20.43 103.585 ;
     RECT  2.34 103.577 2.79 103.613 ;
     RECT  10.515 103.469 10.89 103.613 ;
     RECT  13.215 103.427 13.446 103.613 ;
     RECT  14.868 103.469 18.846 103.613 ;
     RECT  19.98 103.585 20.538 103.613 ;
     RECT  2.34 103.613 2.505 103.649 ;
     RECT  10.515 103.613 10.854 103.649 ;
     RECT  14.868 103.613 16.005 103.649 ;
     RECT  17.1 103.613 18.705 103.649 ;
     RECT  2.415 103.649 2.505 103.697 ;
     RECT  5.115 103.541 5.205 103.697 ;
     RECT  7.815 103.427 7.905 103.697 ;
     RECT  10.515 103.649 10.605 103.697 ;
     RECT  13.215 103.613 13.305 103.697 ;
     RECT  15.48 103.649 16.005 103.697 ;
     RECT  18.396 103.649 18.705 103.697 ;
     RECT  15.48 103.697 15.498 103.739 ;
     RECT  17.1 103.649 17.19 103.739 ;
     RECT  18.396 103.697 18.414 103.739 ;
     RECT  3.924 103.621 3.942 103.805 ;
     RECT  20.52 103.613 20.538 103.805 ;
    LAYER M4 ;
     RECT  0.085 1.392 0.108 1.416 ;
     RECT  0.085 55.488 0.108 55.512 ;
     RECT  0.108 5.28 2.408 103.8 ;
     RECT  2.408 2.148 2.512 103.8 ;
     RECT  2.512 2.418 2.704 103.8 ;
     RECT  2.704 5.856 2.729 5.88 ;
     RECT  2.704 36.768 2.729 45.24 ;
     RECT  2.704 48.96 2.729 57.336 ;
     RECT  2.704 58.464 2.729 63.096 ;
     RECT  2.704 12.192 2.765 12.6 ;
     RECT  2.704 14.112 2.765 16.824 ;
     RECT  2.729 36.768 2.765 44.664 ;
     RECT  2.729 48.96 2.765 53.304 ;
     RECT  2.704 64.128 2.765 64.728 ;
     RECT  2.704 66.528 2.765 70.584 ;
     RECT  2.704 71.712 2.765 71.928 ;
     RECT  2.704 89.472 2.765 90.936 ;
     RECT  2.765 14.112 2.801 16.632 ;
     RECT  2.704 85.728 2.801 85.944 ;
     RECT  2.704 87.648 2.801 88.392 ;
     RECT  2.704 92.448 2.801 94.968 ;
     RECT  2.704 10.656 2.837 10.68 ;
     RECT  2.801 14.112 2.837 16.296 ;
     RECT  2.704 19.872 2.837 25.272 ;
     RECT  2.704 26.592 2.837 27.192 ;
     RECT  2.704 28.704 2.837 31.416 ;
     RECT  2.765 40.416 2.837 44.664 ;
     RECT  2.765 49.488 2.837 53.304 ;
     RECT  2.729 58.464 2.837 62.52 ;
     RECT  2.765 66.528 2.837 66.552 ;
     RECT  2.765 67.68 2.837 70.584 ;
     RECT  2.704 73.056 2.837 73.272 ;
     RECT  2.704 79.296 2.837 82.488 ;
     RECT  2.801 92.448 2.837 94.584 ;
     RECT  2.704 96.192 2.837 103.8 ;
     RECT  2.704 33.312 2.873 35.064 ;
     RECT  2.837 40.416 2.873 41.784 ;
     RECT  2.837 79.296 2.873 81.192 ;
     RECT  2.837 58.8 2.909 62.52 ;
     RECT  2.765 12.192 2.945 12.504 ;
     RECT  2.704 74.592 2.945 77.88 ;
     RECT  2.837 98.784 2.945 100.536 ;
     RECT  2.704 18.528 2.981 18.744 ;
     RECT  2.837 28.704 2.981 31.368 ;
     RECT  2.909 58.8 2.981 61.944 ;
     RECT  2.837 96.192 2.981 96.216 ;
     RECT  2.837 43.104 3.017 44.664 ;
     RECT  2.837 49.488 3.017 52.248 ;
     RECT  2.981 28.992 3.053 31.368 ;
     RECT  2.837 102.144 3.053 103.8 ;
     RECT  2.837 19.872 3.089 21.816 ;
     RECT  2.837 26.592 3.089 26.76 ;
     RECT  2.981 60.384 3.089 61.944 ;
     RECT  2.704 46.272 3.161 47.16 ;
     RECT  2.765 37.92 3.197 39.288 ;
     RECT  2.801 87.648 3.197 88.248 ;
     RECT  2.945 74.592 3.233 77.304 ;
     RECT  3.197 37.92 3.269 39.096 ;
     RECT  3.161 46.272 3.269 47.064 ;
     RECT  3.017 50.16 3.269 52.248 ;
     RECT  3.233 74.592 3.269 75.768 ;
     RECT  3.089 60.384 3.305 61.464 ;
     RECT  3.053 102.144 3.305 102.168 ;
     RECT  3.053 103.2 3.305 103.8 ;
     RECT  2.837 23.328 3.341 24.984 ;
     RECT  3.017 43.872 3.377 44.664 ;
     RECT  2.837 93.216 3.377 93.24 ;
     RECT  2.837 15.264 3.413 16.296 ;
     RECT  3.053 30.432 3.449 31.368 ;
     RECT  3.089 26.592 3.593 26.712 ;
     RECT  2.765 89.712 3.629 90.552 ;
     RECT  3.449 30.672 3.845 31.368 ;
     RECT  3.629 90 3.953 90.552 ;
     RECT  3.305 103.776 3.953 103.8 ;
     RECT  3.413 15.264 4.025 15.864 ;
     RECT  3.089 19.872 4.025 20.376 ;
     RECT  3.341 24.096 4.025 24.984 ;
     RECT  3.269 46.272 4.025 46.392 ;
     RECT  2.729 54.624 4.025 57.336 ;
     RECT  2.981 58.8 4.025 58.824 ;
     RECT  3.089 21.792 4.061 21.816 ;
     RECT  3.269 38.112 4.061 39.096 ;
     RECT  3.269 50.16 4.061 51 ;
     RECT  4.025 55.488 4.061 57.336 ;
     RECT  2.837 68.448 4.061 69.24 ;
     RECT  3.269 74.592 4.061 75.192 ;
     RECT  4.025 15.264 4.097 15.48 ;
     RECT  4.061 69.216 4.097 69.24 ;
     RECT  3.197 88.224 4.097 88.248 ;
     RECT  2.945 12.192 4.133 12.216 ;
     RECT  3.593 26.592 4.133 26.616 ;
     RECT  2.873 35.04 4.133 35.064 ;
     RECT  2.873 41.184 4.133 41.784 ;
     RECT  2.837 53.28 4.133 53.304 ;
     RECT  2.945 98.784 4.133 98.808 ;
     RECT  2.704 9.312 4.237 9.336 ;
     RECT  4.061 57.312 4.597 57.336 ;
     RECT  4.061 39.072 4.633 39.096 ;
     RECT  4.237 9.312 5.108 10.152 ;
     RECT  4.097 15.456 5.108 15.48 ;
     RECT  2.981 18.528 5.108 18.552 ;
     RECT  4.025 24.336 5.108 24.984 ;
     RECT  3.053 28.992 5.108 29.016 ;
     RECT  3.845 30.672 5.108 30.696 ;
     RECT  2.873 33.312 5.108 33.864 ;
     RECT  2.765 36.768 5.108 36.792 ;
     RECT  4.633 39.072 5.108 39.288 ;
     RECT  4.133 41.52 5.108 41.784 ;
     RECT  3.377 44.64 5.108 44.664 ;
     RECT  4.025 46.272 5.108 46.296 ;
     RECT  4.061 50.976 5.108 51 ;
     RECT  4.061 55.488 5.108 56.232 ;
     RECT  4.597 57.312 5.108 58.104 ;
     RECT  3.305 60.384 5.108 60.984 ;
     RECT  2.765 64.608 5.108 64.728 ;
     RECT  2.837 70.56 5.108 70.584 ;
     RECT  2.765 71.904 5.108 71.928 ;
     RECT  2.837 73.056 5.108 73.08 ;
     RECT  4.061 75.168 5.108 75.192 ;
     RECT  3.233 77.28 5.108 77.304 ;
     RECT  2.873 79.296 5.108 80.952 ;
     RECT  2.704 83.808 5.108 83.832 ;
     RECT  3.953 90.528 5.108 90.552 ;
     RECT  2.837 94.56 5.108 94.584 ;
     RECT  2.945 100.512 5.108 100.536 ;
     RECT  5.108 2.148 5.212 103.692 ;
     RECT  5.212 2.418 5.404 103.422 ;
     RECT  5.404 55.392 5.501 55.512 ;
     RECT  5.501 55.392 6.829 55.416 ;
     RECT  5.404 10.128 7.808 10.152 ;
     RECT  5.404 30.672 7.808 30.696 ;
     RECT  6.829 55.392 7.808 55.512 ;
     RECT  6.829 98.256 7.808 98.28 ;
     RECT  7.808 2.148 7.912 103.692 ;
     RECT  7.912 2.418 8.104 103.422 ;
     RECT  8.104 10.128 9.685 10.152 ;
     RECT  10.033 57.312 10.141 57.336 ;
     RECT  10.141 57.312 10.177 57.432 ;
     RECT  9.685 10.128 10.508 10.296 ;
     RECT  8.104 30.672 10.508 30.696 ;
     RECT  8.104 55.488 10.508 55.512 ;
     RECT  10.177 57.312 10.508 58.2 ;
     RECT  10.508 2.148 10.612 103.692 ;
     RECT  10.612 2.418 10.804 103.422 ;
     RECT  10.804 57.312 10.829 58.2 ;
     RECT  10.804 41.952 10.973 41.976 ;
     RECT  11.869 102.384 11.941 102.408 ;
     RECT  10.829 57.936 12.005 58.2 ;
     RECT  10.804 68.736 12.037 68.76 ;
     RECT  12.005 74.64 12.037 74.664 ;
     RECT  12.005 94.128 12.037 94.152 ;
     RECT  12.021 95.136 12.037 95.16 ;
     RECT  10.804 10.128 12.044 10.152 ;
     RECT  12.037 17.616 12.044 18.6 ;
     RECT  12.037 19.968 12.044 19.992 ;
     RECT  11.797 23.568 12.044 23.592 ;
     RECT  12.037 62.304 12.044 62.328 ;
     RECT  12.037 63.792 12.044 64.584 ;
     RECT  12.005 66.144 12.044 66.168 ;
     RECT  12.037 67.68 12.044 67.704 ;
     RECT  12.037 68.736 12.044 69.24 ;
     RECT  12.037 84.672 12.044 84.696 ;
     RECT  12.021 85.92 12.044 85.944 ;
     RECT  12.037 92.256 12.044 92.52 ;
     RECT  12.044 10.128 12.049 10.2 ;
     RECT  10.804 30.672 12.049 30.696 ;
     RECT  12.044 44.736 12.049 44.76 ;
     RECT  11.989 46.896 12.049 47.304 ;
     RECT  11.989 50.112 12.049 50.856 ;
     RECT  12.044 62.304 12.049 66.168 ;
     RECT  12.044 72.24 12.049 72.264 ;
     RECT  12.037 76.896 12.049 77.688 ;
     RECT  12.037 94.128 12.049 95.16 ;
     RECT  12.044 22.992 12.085 23.592 ;
     RECT  12.049 39.264 12.085 39.288 ;
     RECT  10.804 40.32 12.085 40.344 ;
     RECT  12.049 43.872 12.085 44.76 ;
     RECT  12.049 46.32 12.085 47.64 ;
     RECT  12.044 70.992 12.085 71.016 ;
     RECT  12.049 72.24 12.085 73.032 ;
     RECT  12.037 74.64 12.085 75.528 ;
     RECT  12.049 76.896 12.085 77.976 ;
     RECT  12.005 82.032 12.085 82.68 ;
     RECT  12.049 49.536 12.089 50.856 ;
     RECT  10.804 52.176 12.089 53.064 ;
     RECT  12.049 62.208 12.089 66.168 ;
     RECT  12.085 74.64 12.089 77.976 ;
     RECT  12.044 17.616 12.124 19.992 ;
     RECT  12.089 75.216 12.124 77.976 ;
     RECT  12.037 79.152 12.124 80.04 ;
     RECT  12.044 84.672 12.124 85.944 ;
     RECT  12.049 94.032 12.124 95.16 ;
     RECT  12.124 19.2 12.125 19.992 ;
     RECT  12.125 19.2 12.131 19.224 ;
     RECT  12.085 22.464 12.131 25.272 ;
     RECT  12.085 39.264 12.131 40.344 ;
     RECT  12.085 43.872 12.131 47.64 ;
     RECT  12.089 62.208 12.131 65.448 ;
     RECT  12.044 67.68 12.131 69.24 ;
     RECT  12.085 70.992 12.131 73.032 ;
     RECT  12.044 87.696 12.131 87.72 ;
     RECT  12.044 96.72 12.131 97.512 ;
     RECT  12.124 94.032 12.133 94.056 ;
     RECT  12.131 23.904 12.179 25.272 ;
     RECT  12.131 45.552 12.179 47.64 ;
     RECT  12.124 76.368 12.179 77.976 ;
     RECT  12.131 22.464 12.229 22.488 ;
     RECT  12.013 36.384 12.229 36.408 ;
     RECT  12.085 37.584 12.229 37.608 ;
     RECT  12.131 43.872 12.229 44.088 ;
     RECT  12.179 46.8 12.229 47.64 ;
     RECT  12.131 62.208 12.229 64.632 ;
     RECT  12.131 68.976 12.229 69.24 ;
     RECT  12.179 76.464 12.229 77.976 ;
     RECT  12.013 101.328 12.265 101.352 ;
     RECT  11.941 102.384 12.265 102.552 ;
     RECT  12.085 81.552 12.337 82.968 ;
     RECT  12.124 85.488 12.469 85.944 ;
     RECT  12.229 80.064 12.589 80.28 ;
     RECT  12.337 81.552 12.589 83.208 ;
     RECT  12.049 9.888 12.661 10.2 ;
     RECT  12.089 50.544 12.661 50.856 ;
     RECT  10.804 55.488 12.661 55.512 ;
     RECT  12.005 56.976 12.661 58.2 ;
     RECT  12.661 33.936 12.805 33.96 ;
     RECT  12.229 36.384 12.805 37.704 ;
     RECT  12.661 87.552 12.805 87.576 ;
     RECT  12.805 36.384 12.877 37.992 ;
     RECT  12.131 39.264 12.877 39.912 ;
     RECT  12.085 99.552 12.949 99.576 ;
     RECT  12.044 92.256 13.057 93 ;
     RECT  12.805 33.936 13.093 34.68 ;
     RECT  12.661 40.992 13.093 41.016 ;
     RECT  13.057 92.256 13.201 93.24 ;
     RECT  12.661 9.888 13.208 10.248 ;
     RECT  12.265 14.784 13.208 14.808 ;
     RECT  12.124 17.616 13.208 17.64 ;
     RECT  12.661 21.024 13.208 21.048 ;
     RECT  12.229 22.032 13.208 22.488 ;
     RECT  12.179 23.904 13.208 23.928 ;
     RECT  12.179 25.248 13.208 25.272 ;
     RECT  12.049 30.624 13.208 30.696 ;
     RECT  13.093 33.936 13.208 34.776 ;
     RECT  12.877 36.384 13.208 39.912 ;
     RECT  13.093 40.992 13.208 41.496 ;
     RECT  12.229 43.104 13.208 44.088 ;
     RECT  12.179 45.552 13.208 45.576 ;
     RECT  12.229 46.8 13.208 48.408 ;
     RECT  12.089 49.536 13.208 49.56 ;
     RECT  12.661 50.544 13.208 50.904 ;
     RECT  12.089 52.176 13.208 52.44 ;
     RECT  12.661 55.488 13.208 58.2 ;
     RECT  12.049 59.232 13.208 59.256 ;
     RECT  12.229 61.104 13.208 61.128 ;
     RECT  12.229 62.16 13.208 64.632 ;
     RECT  12.229 66.768 13.208 67.608 ;
     RECT  12.229 68.976 13.208 70.008 ;
     RECT  12.131 71.616 13.208 73.032 ;
     RECT  12.124 75.216 13.208 75.24 ;
     RECT  12.229 76.464 13.208 78.648 ;
     RECT  12.589 80.064 13.208 83.208 ;
     RECT  12.469 85.488 13.208 86.232 ;
     RECT  12.805 87.36 13.208 87.576 ;
     RECT  12.049 89.424 13.208 89.448 ;
     RECT  13.201 90.528 13.208 90.552 ;
     RECT  13.201 92.16 13.208 93.24 ;
     RECT  12.124 95.136 13.208 95.16 ;
     RECT  12.265 98.448 13.208 98.472 ;
     RECT  12.949 99.456 13.208 99.576 ;
     RECT  12.265 101.328 13.208 102.552 ;
     RECT  13.208 2.148 13.312 103.692 ;
     RECT  13.312 2.418 13.504 103.422 ;
     RECT  13.504 90.528 13.619 92.184 ;
     RECT  13.504 34.752 13.637 39.288 ;
     RECT  13.504 14.4 13.673 16.104 ;
     RECT  13.619 90.528 13.68 91.512 ;
     RECT  13.504 9.072 13.709 10.776 ;
     RECT  13.504 24.48 13.709 27.336 ;
     RECT  13.637 34.752 13.709 38.232 ;
     RECT  13.504 45.552 13.709 45.768 ;
     RECT  13.504 58.896 13.709 59.256 ;
     RECT  13.504 66.768 13.709 75.24 ;
     RECT  13.673 14.448 13.715 16.104 ;
     RECT  13.504 18.96 13.715 18.984 ;
     RECT  13.709 24.48 13.715 24.504 ;
     RECT  13.504 29.04 13.715 31.368 ;
     RECT  13.504 33.6 13.715 33.624 ;
     RECT  13.504 46.8 13.715 53.064 ;
     RECT  13.504 84.336 13.715 88.248 ;
     RECT  13.709 35.328 13.745 38.232 ;
     RECT  13.504 60.432 13.745 62.76 ;
     RECT  13.68 91.44 13.745 91.512 ;
     RECT  13.709 9.072 13.753 9.096 ;
     RECT  13.709 26.112 13.753 27.336 ;
     RECT  13.715 29.952 13.753 31.368 ;
     RECT  13.504 76.464 13.753 78.696 ;
     RECT  13.504 99.072 13.753 100.344 ;
     RECT  13.715 14.448 13.756 15.384 ;
     RECT  13.753 26.112 13.756 26.184 ;
     RECT  13.753 29.952 13.756 30.744 ;
     RECT  13.715 49.92 13.756 52.584 ;
     RECT  13.753 99.072 13.756 99.48 ;
     RECT  13.745 35.328 13.763 35.352 ;
     RECT  13.745 36.48 13.763 38.232 ;
     RECT  13.715 84.336 13.763 84.36 ;
     RECT  13.715 85.728 13.763 88.248 ;
     RECT  13.504 95.856 13.763 95.88 ;
     RECT  13.504 17.616 13.817 17.688 ;
     RECT  13.504 57.888 14.033 57.912 ;
     RECT  13.504 41.088 14.105 41.784 ;
     RECT  13.756 99.456 14.285 99.48 ;
     RECT  13.504 55.104 14.393 56.616 ;
     RECT  13.504 93.216 14.393 94.68 ;
     RECT  13.745 60.432 14.537 62.568 ;
     RECT  14.393 93.216 14.537 94.152 ;
     RECT  13.504 7.92 14.569 7.944 ;
     RECT  13.817 17.664 14.569 17.688 ;
     RECT  13.709 66.768 14.569 74.568 ;
     RECT  13.504 80.88 14.569 83.256 ;
     RECT  14.537 60.432 14.573 62.472 ;
     RECT  14.569 6.864 14.681 7.944 ;
     RECT  14.569 17.664 14.681 18.84 ;
     RECT  14.569 80.88 14.681 83.592 ;
     RECT  13.504 102.096 14.681 103.224 ;
     RECT  13.709 10.128 14.717 10.776 ;
     RECT  13.756 50.544 14.749 52.584 ;
     RECT  14.573 60.432 14.753 62.232 ;
     RECT  14.537 93.504 14.753 94.152 ;
     RECT  13.504 21.216 14.821 23.352 ;
     RECT  13.763 36.528 14.821 38.232 ;
     RECT  13.504 63.792 14.821 64.632 ;
     RECT  13.756 14.448 14.857 14.472 ;
     RECT  14.569 66.72 14.857 74.568 ;
     RECT  14.749 50.544 14.861 52.824 ;
     RECT  13.745 91.44 14.924 91.464 ;
     RECT  14.857 66.72 14.929 74.664 ;
     RECT  14.681 18.768 14.965 18.84 ;
     RECT  13.504 98.064 14.965 98.088 ;
     RECT  13.709 58.896 15.061 59.208 ;
     RECT  14.753 60.432 15.061 62.184 ;
     RECT  14.929 66.576 15.145 74.664 ;
     RECT  13.709 45.744 15.157 45.768 ;
     RECT  13.763 85.728 15.164 86.232 ;
     RECT  13.753 27.312 15.181 27.336 ;
     RECT  13.504 43.104 15.205 44.424 ;
     RECT  15.157 45.6 15.205 45.768 ;
     RECT  13.715 46.8 15.205 48.408 ;
     RECT  14.924 90.48 15.205 91.464 ;
     RECT  15.001 29.04 15.217 29.064 ;
     RECT  15.061 58.896 15.217 62.184 ;
     RECT  14.105 41.76 15.253 41.784 ;
     RECT  15.205 43.104 15.253 48.408 ;
     RECT  13.756 30.672 15.26 30.744 ;
     RECT  15.205 90.48 15.281 91.896 ;
     RECT  14.681 7.2 15.289 7.944 ;
     RECT  15.181 27.312 15.289 27.624 ;
     RECT  13.763 87.504 15.289 88.248 ;
     RECT  13.756 26.112 15.301 26.136 ;
     RECT  15.289 27.312 15.301 27.72 ;
     RECT  15.164 85.632 15.308 86.232 ;
     RECT  15.289 87.504 15.308 88.68 ;
     RECT  15.145 65.952 15.317 74.664 ;
     RECT  14.857 14.448 15.325 14.664 ;
     RECT  14.821 20.832 15.325 23.352 ;
     RECT  14.393 55.104 15.325 56.376 ;
     RECT  15.308 85.632 15.325 88.68 ;
     RECT  15.325 85.488 15.349 88.68 ;
     RECT  13.753 76.464 15.361 78.408 ;
     RECT  15.26 30.336 15.469 30.744 ;
     RECT  15.217 58.704 15.469 62.184 ;
     RECT  15.317 65.952 15.469 75.288 ;
     RECT  15.361 76.32 15.469 78.408 ;
     RECT  15.325 54.864 15.577 56.376 ;
     RECT  14.681 102.144 15.649 103.224 ;
     RECT  14.861 50.544 15.757 52.296 ;
     RECT  15.325 13.824 15.793 14.664 ;
     RECT  14.965 97.536 15.829 98.088 ;
     RECT  13.504 5.856 15.865 5.88 ;
     RECT  15.289 7.2 15.865 8.856 ;
     RECT  15.301 26.112 15.865 27.72 ;
     RECT  15.829 97.536 15.865 98.376 ;
     RECT  15.865 5.856 15.908 8.856 ;
     RECT  14.717 10.128 15.908 10.152 ;
     RECT  15.793 13.056 15.908 14.664 ;
     RECT  15.181 15.792 15.908 15.816 ;
     RECT  14.681 17.664 15.908 17.688 ;
     RECT  14.965 18.768 15.908 19.56 ;
     RECT  15.325 20.832 15.908 23.4 ;
     RECT  15.865 24.624 15.908 27.72 ;
     RECT  15.217 29.04 15.908 29.304 ;
     RECT  15.469 30.336 15.908 31.128 ;
     RECT  15.865 33.552 15.908 33.576 ;
     RECT  14.821 34.704 15.908 38.232 ;
     RECT  15.865 40.416 15.908 40.44 ;
     RECT  15.253 41.76 15.908 48.408 ;
     RECT  15.757 49.584 15.908 52.296 ;
     RECT  15.469 53.568 15.908 53.592 ;
     RECT  15.577 54.864 15.908 56.616 ;
     RECT  15.469 58.656 15.908 62.184 ;
     RECT  14.821 63.504 15.908 64.632 ;
     RECT  15.469 65.952 15.908 78.408 ;
     RECT  14.681 80.88 15.908 81.192 ;
     RECT  14.681 82.32 15.908 82.824 ;
     RECT  15.349 85.44 15.908 88.68 ;
     RECT  15.281 90.48 15.908 92.376 ;
     RECT  14.753 93.504 15.908 93.528 ;
     RECT  15.865 94.944 15.908 94.968 ;
     RECT  15.865 97.536 15.908 98.472 ;
     RECT  15.865 101.136 15.908 101.16 ;
     RECT  15.649 102.144 15.908 103.32 ;
     RECT  15.908 2.148 16.012 103.692 ;
     RECT  16.012 2.418 16.204 103.422 ;
     RECT  16.204 43.872 16.229 44.424 ;
     RECT  16.204 45.744 16.229 51.432 ;
     RECT  16.204 40.416 16.301 40.44 ;
     RECT  16.204 28.704 16.337 29.304 ;
     RECT  16.204 13.056 16.373 14.808 ;
     RECT  16.204 27.456 16.373 27.72 ;
     RECT  16.204 97.296 16.373 98.472 ;
     RECT  16.373 13.056 16.409 14.664 ;
     RECT  16.373 27.6 16.409 27.72 ;
     RECT  16.204 65.952 16.481 73.8 ;
     RECT  16.409 13.056 16.517 13.848 ;
     RECT  16.204 101.136 16.553 101.16 ;
     RECT  16.337 29.04 16.661 29.304 ;
     RECT  16.204 33.552 16.661 33.576 ;
     RECT  16.204 37.392 16.661 38.184 ;
     RECT  16.229 45.792 16.661 51.432 ;
     RECT  16.481 65.952 16.661 73.56 ;
     RECT  16.204 17.616 16.697 20.136 ;
     RECT  16.204 21.12 16.733 25.848 ;
     RECT  16.661 45.984 16.841 51.432 ;
     RECT  16.204 6.576 16.913 10.92 ;
     RECT  16.733 21.12 16.913 25.656 ;
     RECT  16.409 27.696 16.913 27.72 ;
     RECT  16.661 68.928 16.913 73.56 ;
     RECT  16.204 82.8 16.913 82.824 ;
     RECT  16.913 9.312 16.931 10.92 ;
     RECT  16.697 17.616 16.931 18.648 ;
     RECT  16.697 20.112 16.931 20.136 ;
     RECT  16.913 24.624 16.931 25.656 ;
     RECT  16.204 87.648 16.931 91.416 ;
     RECT  16.913 6.576 16.949 7.992 ;
     RECT  16.949 7.248 16.957 7.992 ;
     RECT  16.931 25.632 16.977 25.656 ;
     RECT  16.373 97.536 17.057 98.472 ;
     RECT  16.661 29.28 17.093 29.304 ;
     RECT  16.204 42.192 17.129 42.744 ;
     RECT  16.931 87.648 17.129 88.92 ;
     RECT  16.229 43.872 17.197 44.376 ;
     RECT  16.204 15.984 17.233 16.008 ;
     RECT  16.913 21.12 17.233 21.96 ;
     RECT  16.841 50.16 17.233 51.432 ;
     RECT  16.204 58.176 17.233 59.256 ;
     RECT  16.204 30.288 17.237 31.128 ;
     RECT  16.841 45.984 17.237 49.032 ;
     RECT  16.204 53.568 17.237 56.616 ;
     RECT  16.204 81.168 17.237 81.192 ;
     RECT  16.204 94.56 17.237 95.016 ;
     RECT  17.129 87.936 17.273 88.92 ;
     RECT  16.517 13.056 17.309 13.08 ;
     RECT  17.129 42.192 17.309 42.6 ;
     RECT  16.204 60.672 17.309 62.184 ;
     RECT  16.204 63.504 17.309 64.392 ;
     RECT  16.204 75.408 17.341 78.696 ;
     RECT  17.233 50.16 17.413 51.768 ;
     RECT  17.233 15.984 17.417 16.248 ;
     RECT  17.237 54.096 17.417 56.616 ;
     RECT  16.661 65.952 17.521 67.704 ;
     RECT  16.204 85.44 17.557 86.232 ;
     RECT  17.309 63.6 17.629 64.392 ;
     RECT  17.521 65.52 17.629 67.704 ;
     RECT  17.309 60.672 17.845 62.04 ;
     RECT  17.341 75.216 18.061 78.696 ;
     RECT  17.485 98.496 18.169 98.52 ;
     RECT  17.629 63.6 18.277 67.704 ;
     RECT  16.913 68.928 18.277 73.368 ;
     RECT  16.957 7.248 18.608 7.272 ;
     RECT  16.931 9.744 18.608 10.92 ;
     RECT  18.529 11.952 18.608 11.976 ;
     RECT  17.417 16.224 18.608 16.248 ;
     RECT  16.931 18.624 18.608 18.648 ;
     RECT  17.233 20.304 18.608 21.96 ;
     RECT  16.913 23.52 18.608 23.544 ;
     RECT  16.931 24.624 18.608 24.648 ;
     RECT  18.313 27.36 18.608 27.384 ;
     RECT  17.237 30.288 18.608 30.744 ;
     RECT  17.449 31.824 18.608 31.848 ;
     RECT  16.204 34.56 18.608 36.264 ;
     RECT  16.661 37.584 18.608 38.184 ;
     RECT  17.449 41.52 18.608 41.544 ;
     RECT  17.309 42.576 18.608 42.6 ;
     RECT  17.197 43.824 18.608 44.376 ;
     RECT  17.237 45.984 18.608 48.936 ;
     RECT  17.413 50.16 18.608 51.912 ;
     RECT  17.449 52.944 18.608 52.968 ;
     RECT  17.417 54.096 18.608 55.272 ;
     RECT  17.417 56.592 18.608 56.616 ;
     RECT  17.233 57.888 18.608 59.256 ;
     RECT  17.845 60.24 18.608 62.04 ;
     RECT  18.277 63.6 18.608 73.368 ;
     RECT  18.061 74.448 18.608 78.696 ;
     RECT  16.204 79.68 18.608 79.8 ;
     RECT  17.557 84.48 18.608 86.232 ;
     RECT  17.273 87.936 18.608 87.96 ;
     RECT  16.931 90.768 18.608 90.792 ;
     RECT  18.169 98.496 18.608 98.616 ;
     RECT  17.593 99.6 18.608 99.624 ;
     RECT  16.204 102.144 18.608 103.32 ;
     RECT  18.608 2.148 18.712 103.692 ;
     RECT  18.712 2.418 18.904 103.422 ;
     RECT  18.904 76.848 18.929 76.872 ;
     RECT  18.904 64.032 19.001 65.544 ;
     RECT  18.904 5.472 19.897 7.416 ;
     RECT  18.904 9.504 19.897 9.72 ;
     RECT  18.904 10.848 19.897 10.872 ;
     RECT  18.904 11.952 19.897 11.976 ;
     RECT  18.904 14.304 19.897 15.096 ;
     RECT  18.904 18.336 19.897 18.552 ;
     RECT  18.904 21.024 19.897 21.048 ;
     RECT  18.904 22.176 19.897 22.2 ;
     RECT  18.904 23.904 19.897 24.888 ;
     RECT  18.904 26.4 19.897 27.384 ;
     RECT  18.904 29.472 19.897 29.496 ;
     RECT  18.904 33.312 19.897 37.944 ;
     RECT  18.904 39.072 19.897 40.248 ;
     RECT  18.904 42.528 19.897 42.744 ;
     RECT  18.904 46.224 19.897 46.248 ;
     RECT  18.904 47.712 19.897 47.736 ;
     RECT  18.904 48.864 19.897 51 ;
     RECT  18.904 52.704 19.897 53.496 ;
     RECT  18.904 54.912 19.897 55.8 ;
     RECT  18.904 61.92 19.897 61.944 ;
     RECT  19.001 64.032 19.897 65.4 ;
     RECT  18.904 66.528 19.897 69.48 ;
     RECT  18.904 70.56 19.897 71.928 ;
     RECT  18.904 73.44 19.897 75.768 ;
     RECT  18.904 78.432 19.897 78.456 ;
     RECT  18.904 80.16 19.897 80.184 ;
     RECT  18.904 81.312 19.897 83.64 ;
     RECT  18.904 84.768 19.897 84.792 ;
     RECT  18.904 86.688 19.897 86.712 ;
     RECT  18.904 88.8 19.897 89.4 ;
     RECT  18.904 92.448 19.897 92.472 ;
     RECT  18.904 93.6 19.897 93.624 ;
     RECT  18.904 95.328 19.897 95.352 ;
     RECT  18.904 97.824 19.897 98.616 ;
     RECT  18.904 99.936 19.897 100.92 ;
     RECT  18.904 102.432 19.897 103.032 ;
     RECT  19.897 66.528 19.933 83.64 ;
     RECT  19.897 84.768 19.933 84.984 ;
     RECT  19.897 91.104 19.933 103.032 ;
     RECT  19.933 91.104 19.969 103.224 ;
     RECT  18.904 57.312 20.113 60.216 ;
     RECT  19.897 61.344 20.113 65.4 ;
     RECT  19.897 86.496 20.113 86.904 ;
     RECT  19.897 88.032 20.113 89.592 ;
     RECT  19.897 16.8 20.149 29.688 ;
     RECT  19.897 52.704 20.149 55.8 ;
     RECT  20.113 57.312 20.149 65.4 ;
     RECT  19.933 66.528 20.149 84.984 ;
     RECT  20.113 86.496 20.149 89.592 ;
     RECT  19.969 91.104 20.149 103.608 ;
     RECT  19.897 5.472 20.221 15.096 ;
     RECT  20.149 16.416 20.221 29.688 ;
     RECT  19.897 32.736 20.221 41.208 ;
     RECT  19.897 42.336 20.221 51.384 ;
     RECT  20.221 5.472 20.257 29.688 ;
     RECT  19.897 30.816 20.257 31.608 ;
     RECT  20.149 57.312 20.329 89.592 ;
     RECT  20.149 90.72 20.329 103.608 ;
     RECT  20.257 5.472 20.401 31.608 ;
     RECT  20.221 32.736 20.401 51.384 ;
     RECT  20.149 52.704 20.401 56.184 ;
     RECT  20.329 57.312 20.401 103.608 ;
     RECT  20.401 5.472 20.509 103.608 ;
     RECT  20.509 5.472 21.409 103.8 ;
     RECT  21.409 5.28 21.516 103.8 ;
    LAYER M5 ;
     RECT  0.192 1.285 0.216 1.381 ;
     RECT  0.096 1.381 0.216 1.427 ;
     RECT  2.4 2.137 2.52 2.151 ;
     RECT  5.1 2.137 5.22 2.151 ;
     RECT  7.8 2.137 7.92 2.151 ;
     RECT  9.696 2.137 10.62 2.151 ;
     RECT  13.2 2.137 13.32 2.151 ;
     RECT  15.9 2.137 16.02 2.151 ;
     RECT  18.6 2.137 18.72 2.151 ;
     RECT  15.9 2.151 16.212 7.957 ;
     RECT  13.2 2.151 13.512 9.061 ;
     RECT  15.9 7.957 16.92 9.347 ;
     RECT  9.696 2.151 10.812 10.307 ;
     RECT  13.2 9.061 13.704 10.595 ;
     RECT  15.9 9.347 16.212 13.477 ;
     RECT  13.2 10.595 13.512 15.349 ;
     RECT  12.096 10.165 12.12 17.605 ;
     RECT  15.9 13.477 16.344 17.605 ;
     RECT  13.2 15.349 13.704 18.995 ;
     RECT  12.048 17.605 12.12 20.003 ;
     RECT  15.9 17.605 16.92 20.147 ;
     RECT  15.9 20.147 16.344 21.155 ;
     RECT  13.2 18.995 13.512 21.637 ;
     RECT  12.096 20.003 12.12 22.453 ;
     RECT  14.832 21.109 14.856 22.597 ;
     RECT  15.9 21.155 16.212 22.597 ;
     RECT  14.832 22.597 16.212 22.643 ;
     RECT  15.072 22.643 16.212 22.741 ;
     RECT  13.2 21.637 13.704 22.787 ;
     RECT  15.072 22.741 16.584 23.411 ;
     RECT  12.096 22.453 12.168 23.893 ;
     RECT  13.2 22.787 13.512 23.893 ;
     RECT  12.096 23.893 13.512 23.939 ;
     RECT  12.144 23.939 13.512 24.469 ;
     RECT  12.144 24.469 13.704 24.611 ;
     RECT  15.072 23.411 16.212 24.661 ;
     RECT  15.072 24.661 16.92 25.667 ;
     RECT  12.24 24.611 13.704 26.819 ;
     RECT  12.24 26.819 13.512 29.029 ;
     RECT  12.24 29.029 13.704 31.379 ;
     RECT  12.24 31.379 13.512 33.589 ;
     RECT  2.4 2.151 2.712 33.685 ;
     RECT  2.112 33.685 2.712 33.875 ;
     RECT  15.072 25.667 16.212 35.171 ;
     RECT  12.24 33.589 13.704 35.317 ;
     RECT  15.216 35.171 16.212 36.133 ;
     RECT  12.24 35.317 13.752 36.515 ;
     RECT  12.24 36.515 13.512 39.877 ;
     RECT  12.096 39.877 13.512 39.923 ;
     RECT  14.832 36.133 16.212 41.795 ;
     RECT  12.096 39.923 12.12 43.861 ;
     RECT  2.4 33.875 2.712 44.629 ;
     RECT  2.304 44.629 2.712 44.867 ;
     RECT  15.072 41.795 16.212 46.645 ;
     RECT  15.072 46.645 16.872 46.835 ;
     RECT  12.096 43.861 12.168 46.885 ;
     RECT  15.312 46.835 16.872 47.219 ;
     RECT  12 46.885 12.168 47.651 ;
     RECT  13.2 39.923 13.512 48.949 ;
     RECT  12 47.651 12.024 49.525 ;
     RECT  13.2 48.949 13.704 49.525 ;
     RECT  12 49.525 13.704 50.579 ;
     RECT  12 50.579 12.024 50.867 ;
     RECT  13.2 50.579 13.704 53.075 ;
     RECT  15.312 47.219 16.212 55.429 ;
     RECT  0.096 1.427 0.12 55.523 ;
     RECT  15.216 55.429 16.212 56.197 ;
     RECT  15.072 56.197 16.212 56.341 ;
     RECT  12.048 56.965 12.072 57.541 ;
     RECT  12.048 57.541 12.12 58.163 ;
     RECT  15.072 56.341 16.728 59.747 ;
     RECT  15.36 59.747 16.728 60.661 ;
     RECT  13.2 53.075 13.512 60.709 ;
     RECT  15.36 60.661 16.92 61.667 ;
     RECT  12.096 58.163 12.12 62.293 ;
     RECT  13.2 60.709 13.704 62.771 ;
     RECT  15.36 61.667 16.728 66.085 ;
     RECT  12.048 62.293 12.12 66.179 ;
     RECT  15.36 66.085 17.064 66.755 ;
     RECT  12.096 66.179 12.12 67.669 ;
     RECT  13.2 62.771 13.512 67.717 ;
     RECT  13.2 67.717 13.752 68.435 ;
     RECT  12.048 67.669 12.12 69.251 ;
     RECT  15.36 66.755 16.728 70.645 ;
     RECT  12.096 69.251 12.12 74.629 ;
     RECT  12.048 74.629 12.12 75.205 ;
     RECT  15.36 70.645 16.968 75.299 ;
     RECT  2.4 44.867 2.712 75.637 ;
     RECT  2.4 75.637 2.856 75.779 ;
     RECT  13.2 68.435 13.512 76.885 ;
     RECT  12.048 75.205 12.168 77.987 ;
     RECT  14.832 78.277 14.856 78.419 ;
     RECT  13.2 76.885 13.704 78.707 ;
     RECT  12.048 77.987 12.12 80.051 ;
     RECT  13.2 78.707 13.512 81.445 ;
     RECT  12.096 80.051 12.12 81.541 ;
     RECT  13.2 81.445 13.704 81.541 ;
     RECT  12.096 81.541 13.704 82.021 ;
     RECT  12.048 82.021 13.704 82.691 ;
     RECT  12.096 82.691 13.704 83.267 ;
     RECT  12.096 83.267 13.512 84.325 ;
     RECT  12.096 84.325 13.752 84.661 ;
     RECT  15.9 75.299 16.968 85.429 ;
     RECT  15.36 85.429 16.968 85.621 ;
     RECT  15.216 85.621 16.968 85.717 ;
     RECT  14.976 85.717 16.968 85.811 ;
     RECT  12.048 84.661 13.752 85.955 ;
     RECT  12.096 85.955 13.752 86.243 ;
     RECT  13.2 86.243 13.752 86.819 ;
     RECT  14.976 85.811 16.212 89.845 ;
     RECT  13.2 86.819 13.512 90.517 ;
     RECT  14.976 89.845 16.92 91.427 ;
     RECT  12.096 86.243 12.12 92.245 ;
     RECT  12.048 92.245 12.12 93.011 ;
     RECT  12.048 93.011 12.072 94.021 ;
     RECT  13.2 90.517 13.608 94.405 ;
     RECT  12.048 94.021 12.12 95.171 ;
     RECT  13.2 94.405 13.752 95.891 ;
     RECT  12.096 95.171 12.12 97.523 ;
     RECT  14.976 91.427 16.212 97.571 ;
     RECT  13.2 95.891 13.512 99.061 ;
     RECT  13.2 99.061 13.704 100.355 ;
     RECT  2.4 75.779 2.712 103.689 ;
     RECT  5.1 2.151 5.412 103.689 ;
     RECT  7.8 2.151 8.112 103.689 ;
     RECT  10.5 10.307 10.812 103.689 ;
     RECT  13.2 100.355 13.512 103.689 ;
     RECT  15.9 97.571 16.212 103.689 ;
     RECT  18.6 2.151 18.912 103.689 ;
     RECT  2.4 103.689 2.52 103.703 ;
     RECT  5.1 103.689 5.22 103.703 ;
     RECT  7.8 103.689 7.92 103.703 ;
     RECT  10.5 103.689 10.62 103.703 ;
     RECT  13.2 103.689 13.32 103.703 ;
     RECT  15.9 103.689 16.02 103.703 ;
     RECT  18.6 103.689 18.72 103.703 ;
     RECT  10.812 10.165 12.096 17.605 ;
     RECT  12.12 10.165 13.2 22.453 ;
     RECT  10.812 17.605 12.048 20.003 ;
     RECT  10.812 20.003 12.096 23.939 ;
     RECT  13.512 21.109 14.832 21.637 ;
     RECT  14.856 21.109 15.9 22.597 ;
     RECT  13.704 21.637 14.832 22.643 ;
     RECT  12.168 22.453 13.2 23.893 ;
     RECT  13.704 22.643 15.072 22.787 ;
     RECT  16.212 23.411 16.584 24.661 ;
     RECT  10.812 23.939 12.144 24.611 ;
     RECT  13.704 24.469 15.072 26.819 ;
     RECT  10.812 24.611 12.24 39.877 ;
     RECT  13.704 29.029 15.072 31.379 ;
     RECT  13.704 33.589 15.072 35.171 ;
     RECT  13.704 35.171 15.216 35.317 ;
     RECT  13.752 35.317 15.216 36.133 ;
     RECT  13.752 36.133 14.832 36.515 ;
     RECT  13.512 36.515 14.832 41.795 ;
     RECT  10.812 39.877 12.096 46.885 ;
     RECT  12.12 39.923 13.2 43.861 ;
     RECT  12.168 43.861 13.2 47.651 ;
     RECT  10.812 46.885 12 50.867 ;
     RECT  12.024 47.651 13.2 49.525 ;
     RECT  12.024 50.579 13.2 50.867 ;
     RECT  10.812 56.965 12.048 58.163 ;
     RECT  12.072 56.965 13.2 57.541 ;
     RECT  12.12 57.541 13.2 75.205 ;
     RECT  10.812 58.163 12.096 62.293 ;
     RECT  10.812 62.293 12.048 66.179 ;
     RECT  10.812 66.179 12.096 67.669 ;
     RECT  10.812 67.669 12.048 69.251 ;
     RECT  10.812 69.251 12.096 74.629 ;
     RECT  10.812 74.629 12.048 80.051 ;
     RECT  12.168 75.205 13.2 77.987 ;
     RECT  12.12 77.987 13.2 81.541 ;
     RECT  13.704 78.277 14.832 78.419 ;
     RECT  14.856 78.277 15.9 78.419 ;
     RECT  10.812 80.051 12.096 82.021 ;
     RECT  10.812 82.021 12.048 82.691 ;
     RECT  10.812 82.691 12.096 84.661 ;
     RECT  13.512 83.267 13.704 84.325 ;
     RECT  10.812 84.661 12.048 85.955 ;
     RECT  13.752 85.621 15.216 85.717 ;
     RECT  13.752 85.717 14.976 86.819 ;
     RECT  10.812 85.955 12.096 92.245 ;
     RECT  12.12 86.243 13.2 93.011 ;
     RECT  13.512 86.819 14.976 90.517 ;
     RECT  13.608 90.517 14.976 94.405 ;
     RECT  10.812 92.245 12.048 95.171 ;
     RECT  12.072 93.011 13.2 94.021 ;
     RECT  12.12 94.021 13.2 97.523 ;
     RECT  13.752 94.405 14.976 95.891 ;
     RECT  10.812 95.171 12.096 97.523 ;
     RECT  13.512 95.891 14.976 97.571 ;
     RECT  13.512 97.571 13.704 99.061 ;
  END
END qwen_glue_w514
END LIBRARY
